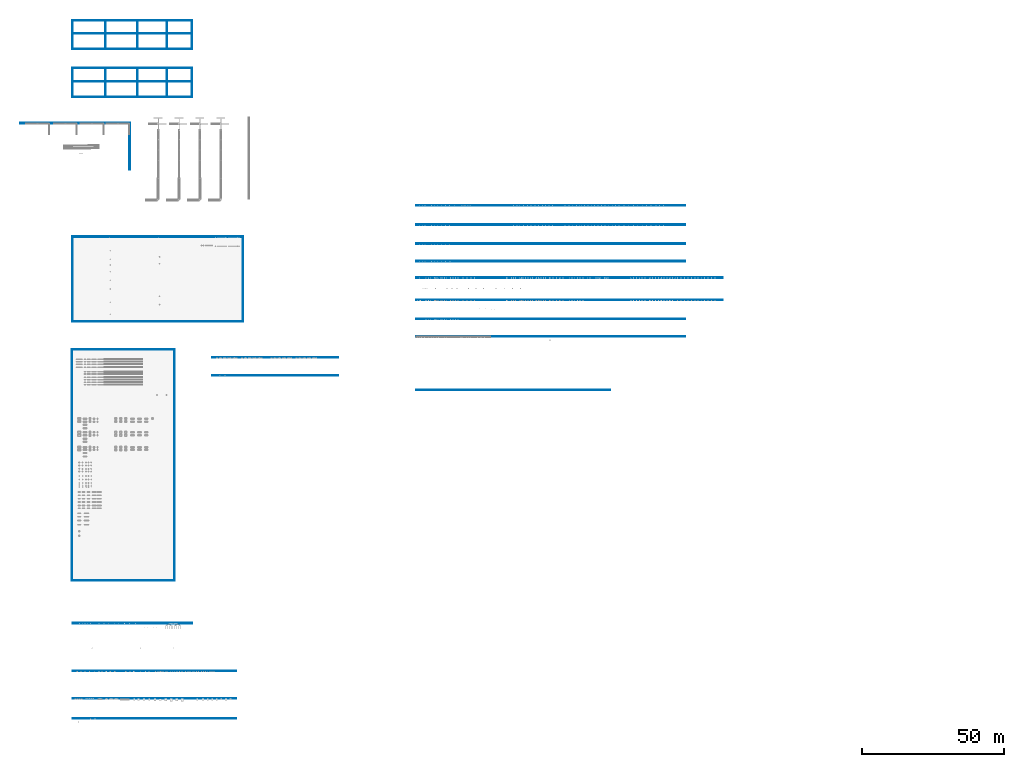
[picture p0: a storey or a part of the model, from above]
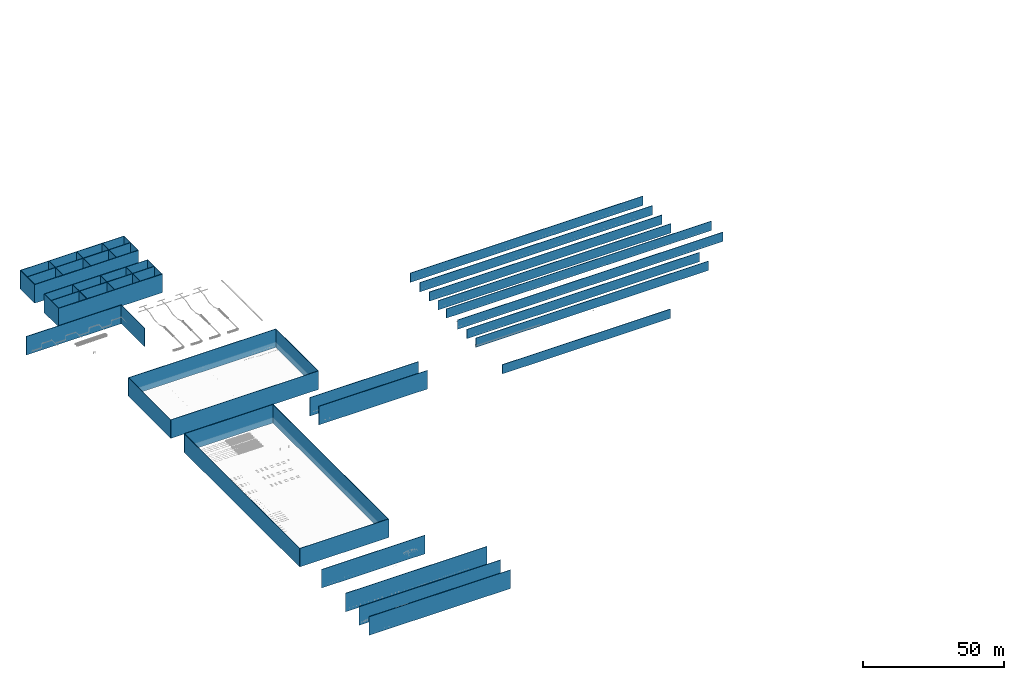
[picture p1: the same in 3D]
Properties of the parts of a building model (IFC2X3), part 1 of 5

# File
Description: ViewDefinition [CoordinationView_V2.0], RevitIdentifiers [ContentGUID: 6402ca86-c77d-4067-b1c1-b8176a6fbf7a, VersionGUID: b93e8563-b8f6-4420-bbab-752b2f349fee, NumberOfSaves: 58], CoordinateReference [CoordinateBase: Coordonnées partagées actuelles]
File name: 735-CAF31-Parvis-ELE.ifc
Time: 2026-01-16T10:17:38+01:00
Written by: ODA SDAI 24.6
Made in: Autodesk Revit 24.3.10.22 (FRA) - IFC 24.3.20.8

# IfcProject, PRO-DCE
LongName: REAMENAGEMENT DU PARVIS DE LA CAF RUE RIQUET A TOULOUSE; Phase: Etat du projet

# IfcSite, Default
RefLatitude: 48, 51, 23, 999633; RefLongitude: 2, 21, 3, 553905; RefElevation: 0 m

# IfcBuilding
Pset_BuildingCommon - NumberOfStoreys: 1

# IfcBuildingStorey: Niveau:Pointe 8 mm (3)
Name | LongName | Elevation (m)
Niveau 0 | Niveau 0 | 0
Niveau 1 | Niveau 1 | 4.58
Niveau 2 | Niveau 2 | 8

# IfcSpace: Espace 1 1:3743090, 1
In: Niveau 0
LongName: Espace 1; InteriorOrExteriorSpace: INTERNAL; Group: Par défaut:293242
Pset_SpaceCommon - Reference: Espace 1 1

# IfcSpace: Espace 2 2:3743092, 2
In: Niveau 0
LongName: Espace 2; InteriorOrExteriorSpace: INTERNAL; Group: Par défaut:293242
Pset_SpaceCommon - Reference: Espace 2 2

# IfcSpace: Espace 21:3744162, 21
In: Niveau 0
LongName: Espace; InteriorOrExteriorSpace: INTERNAL; Group: Par défaut:293242
Pset_SpaceCommon - Reference: Espace 21

# IfcSpace: Espace 22:3744163, 22
In: Niveau 0
LongName: Espace; InteriorOrExteriorSpace: INTERNAL; Group: Par défaut:293242
Pset_SpaceCommon - Reference: Espace 22

# IfcSpace: Espace 23:3744164, 23
In: Niveau 0
LongName: Espace; InteriorOrExteriorSpace: INTERNAL; Group: Par défaut:293242
Pset_SpaceCommon - Reference: Espace 23

# IfcSpace: Espace 24:3744165, 24
In: Niveau 0
LongName: Espace; InteriorOrExteriorSpace: INTERNAL; Group: Par défaut:293242
Pset_SpaceCommon - Reference: Espace 24

# IfcSpace: Espace 25:3744166, 25
In: Niveau 0
LongName: Espace; InteriorOrExteriorSpace: INTERNAL; Group: Par défaut:293242
Pset_SpaceCommon - Reference: Espace 25

# IfcSpace: Espace 26:3744167, 26
In: Niveau 0
LongName: Espace; InteriorOrExteriorSpace: INTERNAL; Group: Par défaut:293242
Pset_SpaceCommon - Reference: Espace 26

# IfcSpace: Espace 27:3744168, 27
In: Niveau 0
LongName: Espace; InteriorOrExteriorSpace: INTERNAL; Group: Par défaut:293242
Pset_SpaceCommon - Reference: Espace 27

# IfcSpace: Espace 28:3744169, 28
In: Niveau 0
LongName: Espace; InteriorOrExteriorSpace: INTERNAL; Group: Par défaut:293242
Pset_SpaceCommon - Reference: Espace 28

# IfcSpace: Espace 3 3:3743094, 3
In: Niveau 0
LongName: Espace 3; InteriorOrExteriorSpace: INTERNAL; Group: Par défaut:293242
Pset_SpaceCommon - Reference: Espace 3 3

# IfcSpace: Espace 4 4:3743096, 4
In: Niveau 0
LongName: Espace 4; InteriorOrExteriorSpace: INTERNAL; Group: Par défaut:293242
Pset_SpaceCommon - Reference: Espace 4 4

# IfcSpace: Espace 5 5:3743098, 5
In: Niveau 0
LongName: Espace 5; InteriorOrExteriorSpace: INTERNAL; Group: Par défaut:293242
Pset_SpaceCommon - Reference: Espace 5 5

# IfcSpace: Espace 6 6:3743100, 6
In: Niveau 0
LongName: Espace 6; InteriorOrExteriorSpace: INTERNAL; Group: Par défaut:293242
Pset_SpaceCommon - Reference: Espace 6 6

# IfcSpace: Espace 7 7:3743102, 7
In: Niveau 0
LongName: Espace 7; InteriorOrExteriorSpace: INTERNAL; Group: Par défaut:293242
Pset_SpaceCommon - Reference: Espace 7 7

# IfcSpace: Espace 8 8:3743104, 8
In: Niveau 0
LongName: Espace 8; InteriorOrExteriorSpace: INTERNAL; Group: Par défaut:293242
Pset_SpaceCommon - Reference: Espace 8 8

# IfcSpace: Pièce 1 21:3744182, 21
In: Niveau 0
LongName: Pièce 1; InteriorOrExteriorSpace: INTERNAL
Pset_SpaceCommon - Reference: Pièce 1 21

# IfcSpace: Pièce 1:3743132, 1
In: Niveau 0
LongName: Pièce; InteriorOrExteriorSpace: INTERNAL
Pset_SpaceCommon - Reference: Pièce 1

# IfcSpace: Pièce 2 22:3744183, 22
In: Niveau 0
LongName: Pièce 2; InteriorOrExteriorSpace: INTERNAL
Pset_SpaceCommon - Reference: Pièce 2 22

# IfcSpace: Pièce 2:3743134, 2
In: Niveau 0
LongName: Pièce; InteriorOrExteriorSpace: INTERNAL
Pset_SpaceCommon - Reference: Pièce 2

# IfcSpace: Pièce 3 23:3744184, 23
In: Niveau 0
LongName: Pièce 3; InteriorOrExteriorSpace: INTERNAL
Pset_SpaceCommon - Reference: Pièce 3 23

# IfcSpace: Pièce 3:3743136, 3
In: Niveau 0
LongName: Pièce; InteriorOrExteriorSpace: INTERNAL
Pset_SpaceCommon - Reference: Pièce 3

# IfcSpace: Pièce 4 24:3744185, 24
In: Niveau 0
LongName: Pièce 4; InteriorOrExteriorSpace: INTERNAL
Pset_SpaceCommon - Reference: Pièce 4 24

# IfcSpace: Pièce 4:3743138, 4
In: Niveau 0
LongName: Pièce; InteriorOrExteriorSpace: INTERNAL
Pset_SpaceCommon - Reference: Pièce 4

# IfcSpace: Pièce 5 25:3744186, 25
In: Niveau 0
LongName: Pièce 5; InteriorOrExteriorSpace: INTERNAL
Pset_SpaceCommon - Reference: Pièce 5 25

# IfcSpace: Pièce 5:3743140, 5
In: Niveau 0
LongName: Pièce; InteriorOrExteriorSpace: INTERNAL
Pset_SpaceCommon - Reference: Pièce 5

# IfcSpace: Pièce 6 26:3744187, 26
In: Niveau 0
LongName: Pièce 6; InteriorOrExteriorSpace: INTERNAL
Pset_SpaceCommon - Reference: Pièce 6 26

# IfcSpace: Pièce 6:3743142, 6
In: Niveau 0
LongName: Pièce; InteriorOrExteriorSpace: INTERNAL
Pset_SpaceCommon - Reference: Pièce 6

# IfcSpace: Pièce 7 27:3744188, 27
In: Niveau 0
LongName: Pièce 7; InteriorOrExteriorSpace: INTERNAL
Pset_SpaceCommon - Reference: Pièce 7 27

# IfcSpace: Pièce 7:3743144, 7
In: Niveau 0
LongName: Pièce; InteriorOrExteriorSpace: INTERNAL
Pset_SpaceCommon - Reference: Pièce 7

# IfcSpace: Pièce 8 28:3744189, 28
In: Niveau 0
LongName: Pièce 8; InteriorOrExteriorSpace: INTERNAL
Pset_SpaceCommon - Reference: Pièce 8 28

# IfcSpace: Pièce 8:3743146, 8
In: Niveau 0
LongName: Pièce; InteriorOrExteriorSpace: INTERNAL
Pset_SpaceCommon - Reference: Pièce 8

# IfcBuildingElementProxy: Armoire 950+500x1600:950+500x1600, Armoire 950+500x1600:950+500x1600:4182300
In: Niveau 0
Type - Material: A-PVC ARMOIRE 3 - POIGNE - RAL 7035, BETCE-BARILLET-RAL 9010, <Unnamed>, BETCE-ENVELOPPE-RAL 7035
Pset_BuildingElementProxyCommon - Reference: 950+500x1600; sets with these values: 2

# IfcBuildingElementProxy: Armoire double 3195x1600x630:3195X1600, Armoire double 3195x1600x630:3195X1600:4185073
In: Niveau 0
Type - Material: <Unnamed>, A-PEINTURE ARMOIRE 4 - POIGNE - RAL 7035, A-ACIER INOXIDABLE - BARILLET - RAL 9010, BETCE-BARILLET-RAL 9010, A-PEINTURE ARMOIRE 4 - ENVELOPPE - RAL 7035
Pset_BuildingElementProxyCommon - Reference: 3195X1600; sets with these values: 2

# IfcBuildingElementProxy: Armoire murale 2x725x1050:2x725x1050, Armoire murale 2x725x1050:2x725x1050:4176260
In: Niveau 0
Type - Material: A- PVC ARMOIRE 2 - POIGNE - RAL 7035, A- PVC ARMOIRE 2 - BARRILLET - RAL 9010, <Unnamed>, A- PVC ARMOIRE 2 - ENVELOPPE - RAL 7035
Pset_BuildingElementProxyCommon - Reference: 2x725x1050; sets with these values: 2

# IfcBuildingElementProxy: Armoire murale 600+350x1100:600+350X1100, Armoire murale 600+350x1100:600+350X1100:4174725
In: Niveau 0
Type - Material: A-PVC ARMOIRE - POIGNE -RAL 7035, A-PVC ARMOIRE - BARILLET -RAL 9010, <Unnamed>, A-PVC ARMOIRE - ENVELOPPE -RAL 7035
Pset_BuildingElementProxyCommon - Reference: 600+350X1100; sets with these values: 2

# IfcBuildingElementProxy: Armoire sur pied 2x600+300x2000:2x600+300x2000, Armoire sur pied 2x600+300x2000:2x600+300x2000:4173222
In: Niveau 0
Type - Material: BETCE-POIGNE-RAL 7035, BETCE-BARILLET-RAL 9010, <Unnamed>, BETCE-ENVELOPPE-RAL 7035
Pset_BuildingElementProxyCommon - Reference: 2x600+300x2000; sets with these values: 2

# IfcBuildingElementProxy: Arrêt d'urgence à voyant:A.U. GENERAL, Arrêt d'urgence à voyant:A.U. GENERAL:4813649
In: Niveau 0
Type - Material: PVC ROUGE, Verre, VOYANT ROUGE, VOYANT VERT
Pset_BuildingElementProxyCommon - Reference: A.U. GENERAL; sets with these values: 2

# IfcBuildingElementProxy: Arrêt d'urgence à voyant:A.U. VENTILLATION, Arrêt d'urgence à voyant:A.U. VENTILLATION:4813641
In: Niveau 0
Type - Material: PVC ROUGE, Verre, VOYANT ROUGE, VOYANT VERT
Pset_BuildingElementProxyCommon - Reference: A.U. VENTILLATION; sets with these values: 2

# IfcBuildingElementProxy: Arrêt d'urgence à voyant:Arrêt d'urgence à voyant, Arrêt d'urgence à voyant:Arrêt d'urgence à voyant:4811939
In: Niveau 0
Type - Material: PVC ROUGE, Verre, VOYANT ROUGE, VOYANT VERT
Pset_BuildingElementProxyCommon - Reference: Arrêt d'urgence à voyant; sets with these values: 2

# IfcBuildingElementProxy: Attente électrique-100e:FM CVC, Attente électrique-100e:FM CVC:4817656
In: Niveau 0
Type - Material: <Unnamed>
Pset_BuildingElementProxyCommon - Reference: FM CVC; sets with these values: 2

# IfcBuildingElementProxy: Attente électrique-100e:FM ELEC, Attente électrique-100e:FM ELEC:4817851
In: Niveau 0
Type - Material: <Unnamed>
Pset_BuildingElementProxyCommon - Reference: FM ELEC; sets with these values: 2

# IfcBuildingElementProxy: Attente électrique-50e:FM CVC (2)
In: Niveau 0
Type - Material: <Unnamed>
Pset_BuildingElementProxyCommon - Reference: FM CVC; sets with these values: 2
Name (Attente électrique-50e:FM CVC:...)
4815699
6239915

# IfcBuildingElementProxy: Attente électrique-50e:FM ELEC (7)
In: Niveau 0
Type - Material: <Unnamed>
Pset_BuildingElementProxyCommon - Reference: FM ELEC; sets with these values: 2
Name (Attente électrique-50e:FM ELEC:...)
4817803
6209736
6234142
6234843
6252051
6252059
6253986

# IfcBuildingElementProxy: Baie de brassage sur pied:24U-L=600_P=600_H=1226, Baie de brassage sur pied:24U-L=600_P=600_H=1226:4192028
In: Niveau 0
Type - Material: A-PVC NOIR, A-VERRE, <Unnamed>
Pset_BuildingElementProxyCommon - Reference: 24U-L=600_P=600_H=1226; sets with these values: 2

# IfcBuildingElementProxy: Baie de brassage sur pied:29U-L=600_P=600_H=1448, Baie de brassage sur pied:29U-L=600_P=600_H=1448:4192674
In: Niveau 0
Type - Material: A-PVC NOIR, A-VERRE, <Unnamed>
Pset_BuildingElementProxyCommon - Reference: 29U-L=600_P=600_H=1448; sets with these values: 2

# IfcBuildingElementProxy: Baie de brassage sur pied:33U-L=600_P=600_H=1626, Baie de brassage sur pied:33U-L=600_P=600_H=1626:4192862
In: Niveau 0
Type - Material: A-PVC NOIR, A-VERRE, <Unnamed>
Pset_BuildingElementProxyCommon - Reference: 33U-L=600_P=600_H=1626; sets with these values: 2

# IfcBuildingElementProxy: Baie de brassage sur pied:42U-L=600_P=600_H=2026, Baie de brassage sur pied:42U-L=600_P=600_H=2026:4192974
In: Niveau 0
Type - Material: A-PVC NOIR, A-VERRE, <Unnamed>
Pset_BuildingElementProxyCommon - Reference: 42U-L=600_P=600_H=2026; sets with these values: 2

# IfcBuildingElementProxy: Baie de brassage sur pied:42U-L=600_P=800_H=2026, Baie de brassage sur pied:42U-L=600_P=800_H=2026:4193102
In: Niveau 0
Type - Material: A-PVC NOIR, A-VERRE, <Unnamed>
Pset_BuildingElementProxyCommon - Reference: 42U-L=600_P=800_H=2026; sets with these values: 2

# IfcBuildingElementProxy: Baie de brassage sur pied:42U-L=800_P=1000_H=2026, Baie de brassage sur pied:42U-L=800_P=1000_H=2026:4193520
In: Niveau 0
Type - Material: A-PVC NOIR, A-VERRE, <Unnamed>
Pset_BuildingElementProxyCommon - Reference: 42U-L=800_P=1000_H=2026; sets with these values: 2

# IfcBuildingElementProxy: Baie de brassage sur pied:42U-L=800_P=600_H=2026, Baie de brassage sur pied:42U-L=800_P=600_H=2026:4193318
In: Niveau 0
Type - Material: A-PVC NOIR, A-VERRE, <Unnamed>
Pset_BuildingElementProxyCommon - Reference: 42U-L=800_P=600_H=2026; sets with these values: 2

# IfcBuildingElementProxy: Baie de brassage sur pied:42U-L=800_P=800_H=2026, Baie de brassage sur pied:42U-L=800_P=800_H=2026:4193430
In: Niveau 0
Type - Material: A-PVC NOIR, A-VERRE, <Unnamed>
Pset_BuildingElementProxyCommon - Reference: 42U-L=800_P=800_H=2026; sets with these values: 2

# IfcBuildingElementProxy: Baie de brassage sur pied:47U-L=800_P=1000_H=2248, Baie de brassage sur pied:47U-L=800_P=1000_H=2248:4193710
In: Niveau 0
Type - Material: A-PVC NOIR, A-VERRE, <Unnamed>
Pset_BuildingElementProxyCommon - Reference: 47U-L=800_P=1000_H=2248; sets with these values: 2

# IfcBuildingElementProxy: Baie de brassage sur pied:47U-L=800_P=800_H=2248, Baie de brassage sur pied:47U-L=800_P=800_H=2248:4193630
In: Niveau 0
Type - Material: A-PVC NOIR, A-VERRE, <Unnamed>
Pset_BuildingElementProxyCommon - Reference: 47U-L=800_P=800_H=2248; sets with these values: 2

# IfcBuildingElementProxy: Boitier sol 2x3 modules:2PCN+2RJ+1HDMI+1USB, Boitier sol 2x3 modules:2PCN+2RJ+1HDMI+1USB:5134745
In: Niveau 0
Type - Material: <Unnamed>, Legrand - Inox
Type - Pset_ManufacturerTypeInformation - Manufacturer: LEGRAND
Pset_BuildingElementProxyCommon - Reference: 2PCN+2RJ+1HDMI+1USB; sets with these values: 2

# IfcBuildingElementProxy: Boitier sol 3x3 modules:2PCN+2PCO+2RJ+1HDMI+1USB, Boitier sol 3x3 modules:2PCN+2PCO+2RJ+1HDMI+1USB:5141581
In: Niveau 0
Type - Material: <Unnamed>, Legrand - Inox
Type - Pset_ManufacturerTypeInformation - Manufacturer: LEGRAND
Pset_BuildingElementProxyCommon - Reference: 2PCN+2PCO+2RJ+1HDMI+1USB; sets with these values: 2

# IfcBuildingElementProxy: Boitier sol 3x3 modules:2PCN+2PCO+2RJ+2HDMI, Boitier sol 3x3 modules:2PCN+2PCO+2RJ+2HDMI:5141752
In: Niveau 0
Type - Material: <Unnamed>, Legrand - Inox
Type - Pset_ManufacturerTypeInformation - Manufacturer: LEGRAND
Pset_BuildingElementProxyCommon - Reference: 2PCN+2PCO+2RJ+2HDMI; sets with these values: 2

# IfcBuildingElementProxy: Boitier sol 3x3 modules:2PCN+2PCO+2RJ+2USB, Boitier sol 3x3 modules:2PCN+2PCO+2RJ+2USB:5141893
In: Niveau 0
Type - Material: <Unnamed>, Legrand - Inox
Type - Pset_ManufacturerTypeInformation - Manufacturer: LEGRAND
Pset_BuildingElementProxyCommon - Reference: 2PCN+2PCO+2RJ+2USB; sets with these values: 2

# IfcBuildingElementProxy: Boitier sol 3x4 modules:3PCN+3PCO+3RJ+1HDMI+1USB, Boitier sol 3x4 modules:3PCN+3PCO+3RJ+1HDMI+1USB:5148815
In: Niveau 0
Type - Material: <Unnamed>, Legrand - Inox
Type - Pset_ManufacturerTypeInformation - Manufacturer: LEGRAND
Pset_BuildingElementProxyCommon - Reference: 3PCN+3PCO+3RJ+1HDMI+1USB; sets with these values: 2

# IfcBuildingElementProxy: Boitier sol 3x4 modules:3PCN+3PCO+3RJ+2HDMI, Boitier sol 3x4 modules:3PCN+3PCO+3RJ+2HDMI:5148930
In: Niveau 0
Type - Material: <Unnamed>, Legrand - Inox
Type - Pset_ManufacturerTypeInformation - Manufacturer: LEGRAND
Pset_BuildingElementProxyCommon - Reference: 3PCN+3PCO+3RJ+2HDMI; sets with these values: 2

# IfcBuildingElementProxy: Boitier sol 3x4 modules:3PCN+3PCO+3RJ+2USB, Boitier sol 3x4 modules:3PCN+3PCO+3RJ+2USB:5149087
In: Niveau 0
Type - Material: <Unnamed>, Legrand - Inox
Type - Pset_ManufacturerTypeInformation - Manufacturer: LEGRAND
Pset_BuildingElementProxyCommon - Reference: 3PCN+3PCO+3RJ+2USB; sets with these values: 2

# IfcBuildingElementProxy: Boitier sol 4x4 modules:4PCN+4PCO+4RJ+1HDMI+1USB, Boitier sol 4x4 modules:4PCN+4PCO+4RJ+1HDMI+1USB:5157137
In: Niveau 0
Type - Material: <Unnamed>, Legrand - Inox
Type - Pset_ManufacturerTypeInformation - Manufacturer: LEGRAND
Pset_BuildingElementProxyCommon - Reference: 4PCN+4PCO+4RJ+1HDMI+1USB; sets with these values: 2

# IfcBuildingElementProxy: Boitier sol 4x4 modules:4PCN+4PCO+4RJ+2HDMI, Boitier sol 4x4 modules:4PCN+4PCO+4RJ+2HDMI:5157296
In: Niveau 0
Type - Material: <Unnamed>, Legrand - Inox
Type - Pset_ManufacturerTypeInformation - Manufacturer: LEGRAND
Pset_BuildingElementProxyCommon - Reference: 4PCN+4PCO+4RJ+2HDMI; sets with these values: 2

# IfcBuildingElementProxy: Boitier sol 4x4 modules:4PCN+4PCO+4RJ+2HDMI+2USB, Boitier sol 4x4 modules:4PCN+4PCO+4RJ+2HDMI+2USB:5157393
In: Niveau 0
Type - Material: <Unnamed>, Legrand - Inox
Type - Pset_ManufacturerTypeInformation - Manufacturer: LEGRAND
Pset_BuildingElementProxyCommon - Reference: 4PCN+4PCO+4RJ+2HDMI+2USB; sets with these values: 2

# IfcBuildingElementProxy: Boitier sol 4x4 modules:4PCN+4PCO+4RJ+2USB, Boitier sol 4x4 modules:4PCN+4PCO+4RJ+2USB:5157482
In: Niveau 0
Type - Material: <Unnamed>, Legrand - Inox
Type - Pset_ManufacturerTypeInformation - Manufacturer: LEGRAND
Pset_BuildingElementProxyCommon - Reference: 4PCN+4PCO+4RJ+2USB; sets with these values: 2

# IfcBuildingElementProxy: Bouton poussoir domotique encastré:BLEU, Bouton poussoir domotique encastré:BLEU:5246806
In: Niveau 0
Type - Material: BETCE-CADRE MARRON 152-112-16, <Unnamed>
Pset_BuildingElementProxyCommon - Reference: BLEU; sets with these values: 2

# IfcBuildingElementProxy: Bouton poussoir domotique encastré:MAGENTA, Bouton poussoir domotique encastré:MAGENTA:5247162
In: Niveau 0
Type - Material: BETCE-CADRE MARRON 152-112-16, <Unnamed>
Pset_BuildingElementProxyCommon - Reference: MAGENTA; sets with these values: 2

# IfcBuildingElementProxy: Bouton poussoir domotique encastré:MARRON, Bouton poussoir domotique encastré:MARRON:5247234
In: Niveau 0
Type - Material: BETCE-CADRE MARRON 152-112-16, <Unnamed>
Pset_BuildingElementProxyCommon - Reference: MARRON; sets with these values: 2

# IfcBuildingElementProxy: Bouton poussoir domotique encastré:NOIR, Bouton poussoir domotique encastré:NOIR:5247298
In: Niveau 0
Type - Material: BETCE-CADRE MARRON 152-112-16, <Unnamed>
Pset_BuildingElementProxyCommon - Reference: NOIR; sets with these values: 2

# IfcBuildingElementProxy: Bouton poussoir domotique encastré:ORANGE, Bouton poussoir domotique encastré:ORANGE:5247380
In: Niveau 0
Type - Material: BETCE-CADRE MARRON 152-112-16, <Unnamed>
Pset_BuildingElementProxyCommon - Reference: ORANGE; sets with these values: 2

# IfcBuildingElementProxy: Bouton poussoir domotique encastré:ROUGE, Bouton poussoir domotique encastré:ROUGE:5247480
In: Niveau 0
Type - Material: BETCE-CADRE MARRON 152-112-16, <Unnamed>
Pset_BuildingElementProxyCommon - Reference: ROUGE; sets with these values: 2

# IfcBuildingElementProxy: Bouton poussoir domotique encastré:VERT, Bouton poussoir domotique encastré:VERT:5247558
In: Niveau 0
Type - Material: BETCE-CADRE MARRON 152-112-16, <Unnamed>
Pset_BuildingElementProxyCommon - Reference: VERT; sets with these values: 2

# IfcBuildingElementProxy: Bouton poussoir encastré controle acces:BP sortie, Bouton poussoir encastré controle acces:BP sortie:4091872
In: Niveau 0
Type - Material: BETCE-DOIGT-BLANC, BETCE-ENJOLIVEUR-BLANC, <Unnamed>
Pset_BuildingElementProxyCommon - Reference: BP sortie; sets with these values: 2

# IfcBuildingElementProxy: Bouton poussoir saillie controle acces:BP sortie, Bouton poussoir saillie controle acces:BP sortie:6006362
In: Niveau 0
Type - Material: BETCE-CADRE-BLANC, BETCE-DOIGT-BLANC, BETCE-ENJOLIVEUR-BLANC
Pset_BuildingElementProxyCommon - Reference: BP sortie; sets with these values: 2

# IfcBuildingElementProxy: Centrale:Centrale control d'accés, Centrale:Centrale control d'accés:4087308
In: Niveau 0
Type - Material: <Unnamed>
Pset_BuildingElementProxyCommon - Reference: Centrale control d'accés; sets with these values: 2

# IfcBuildingElementProxy: Centrale:Centrale intrusion, Centrale:Centrale intrusion:4087595
In: Niveau 0
Type - Material: <Unnamed>
Pset_BuildingElementProxyCommon - Reference: Centrale intrusion; sets with these values: 2

# IfcBuildingElementProxy: Clavier:Clavier intrusion, Clavier:Clavier intrusion:4090489
In: Niveau 0
Type - Material: <Unnamed>
Type - Pset_ElementShading - Color: Black RAL9005
Type - Pset_ManufacturerTypeInformation - Manufacturer: Urmet S.p.A.Urmet S.p.A.
Classification: 80KP5300113 (Uniformat)
Pset_BuildingElementProxyCommon - Reference: Clavier intrusion; sets with these values: 2

# IfcBuildingElementProxy: Coffret UTL:UTL contrôle accés - alim non secourue-8E/4S, Coffret UTL:UTL contrôle accés - alim non secourue-8E/4S:4084620
In: Niveau 0
Type - Material: <Unnamed>
Pset_BuildingElementProxyCommon - Reference: UTL contrôle accés - alim non secourue-8E/4S; sets with these values: 2

# IfcBuildingElementProxy: Coffret UTL:UTL contrôle accés - alim secourue-8E/4S, Coffret UTL:UTL contrôle accés - alim secourue-8E/4S:4085028
In: Niveau 0
Type - Material: <Unnamed>
Pset_BuildingElementProxyCommon - Reference: UTL contrôle accés - alim secourue-8E/4S; sets with these values: 2

# IfcBuildingElementProxy: Coffret UTL:UTL intrusion - alim non secourue-8E/4S, Coffret UTL:UTL intrusion - alim non secourue-8E/4S:4085036
In: Niveau 0
Type - Material: <Unnamed>
Pset_BuildingElementProxyCommon - Reference: UTL intrusion - alim non secourue-8E/4S; sets with these values: 2

# IfcBuildingElementProxy: Coffret UTL:UTL intrusion - alim secourue-8E/4S, Coffret UTL:UTL intrusion - alim secourue-8E/4S:4085044
In: Niveau 0
Type - Material: <Unnamed>
Pset_BuildingElementProxyCommon - Reference: UTL intrusion - alim secourue-8E/4S; sets with these values: 2

# IfcBuildingElementProxy: Coffret de brassage mural:12U-600x600x635, Coffret de brassage mural:12U-600x600x635:4200865
In: Niveau 0
Type - Material: A-PVC NOIR, A-VERRE
Pset_BuildingElementProxyCommon - Reference: 12U-600x600x635; sets with these values: 2

# IfcBuildingElementProxy: Coffret de brassage mural:15U-600x600x770, Coffret de brassage mural:15U-600x600x770:4200817
In: Niveau 0
Type - Material: A-PVC NOIR, A-VERRE
Pset_BuildingElementProxyCommon - Reference: 15U-600x600x770; sets with these values: 2

# IfcBuildingElementProxy: Coffret de brassage mural:18U-600x600x900, Coffret de brassage mural:18U-600x600x900:4200691
In: Niveau 0
Type - Material: A-PVC NOIR, A-VERRE
Pset_BuildingElementProxyCommon - Reference: 18U-600x600x900; sets with these values: 2

# IfcBuildingElementProxy: Coffret de brassage mural:22U-600x600x1200, Coffret de brassage mural:22U-600x600x1200:4198581
In: Niveau 0
Type - Material: A-PVC NOIR, A-VERRE
Pset_BuildingElementProxyCommon - Reference: 22U-600x600x1200; sets with these values: 2

# IfcBuildingElementProxy: Coffret de brassage mural:6U-600x450x368, Coffret de brassage mural:6U-600x450x368:4201155
In: Niveau 0
Type - Material: A-PVC NOIR, A-VERRE
Pset_BuildingElementProxyCommon - Reference: 6U-600x450x368; sets with these values: 2

# IfcBuildingElementProxy: Coffret de brassage mural:6U-600x600x368, Coffret de brassage mural:6U-600x600x368:4201077
In: Niveau 0
Type - Material: A-PVC NOIR, A-VERRE
Pset_BuildingElementProxyCommon - Reference: 6U-600x600x368; sets with these values: 2

# IfcBuildingElementProxy: Coffret de brassage mural:9U-600x450x500, Coffret de brassage mural:9U-600x450x500:4201009
In: Niveau 0
Type - Material: A-PVC NOIR, A-VERRE
Pset_BuildingElementProxyCommon - Reference: 9U-600x450x500; sets with these values: 2

# IfcBuildingElementProxy: Coffret de brassage mural:9U-600x600x500, Coffret de brassage mural:9U-600x600x500:4200919
In: Niveau 0
Type - Material: A-PVC NOIR, A-VERRE
Pset_BuildingElementProxyCommon - Reference: 9U-600x600x500; sets with these values: 2

# IfcBuildingElementProxy: Coffret mural 18 modules avec porte:18M-1R, Coffret mural 18 modules avec porte:18M-1R:4139435
In: Niveau 0
Type - Material: BETCE-ANNEAU-CHROME, BETCE-TABLEAU-BLANC
Pset_BuildingElementProxyCommon - Reference: 18M-1R; sets with these values: 2

# IfcBuildingElementProxy: Coffret mural 18 modules avec porte:36M-2R, Coffret mural 18 modules avec porte:36M-2R:4154643
In: Niveau 0
Type - Material: BETCE-ANNEAU-CHROME, BETCE-TABLEAU-BLANC
Pset_BuildingElementProxyCommon - Reference: 36M-2R; sets with these values: 2

# IfcBuildingElementProxy: Coffret mural 18 modules avec porte:54M-3R, Coffret mural 18 modules avec porte:54M-3R:4154651
In: Niveau 0
Type - Material: BETCE-ANNEAU-CHROME, BETCE-TABLEAU-BLANC
Pset_BuildingElementProxyCommon - Reference: 54M-3R; sets with these values: 2

# IfcBuildingElementProxy: Coffret mural 18 modules avec porte:72M-4R, Coffret mural 18 modules avec porte:72M-4R:4154659
In: Niveau 0
Type - Material: BETCE-ANNEAU-CHROME, BETCE-TABLEAU-BLANC
Pset_BuildingElementProxyCommon - Reference: 72M-4R; sets with these values: 2

# IfcBuildingElementProxy: Coffret mural 18 modules:18M-1R, Coffret mural 18 modules:18M-1R:4156919
In: Niveau 0
Type - Material: BETCE-TABLEAU-BLANC
Pset_BuildingElementProxyCommon - Reference: 18M-1R; sets with these values: 2

# IfcBuildingElementProxy: Coffret mural 18 modules:36M-2R, Coffret mural 18 modules:36M-2R:4157181
In: Niveau 0
Type - Material: BETCE-TABLEAU-BLANC
Pset_BuildingElementProxyCommon - Reference: 36M-2R; sets with these values: 2

# IfcBuildingElementProxy: Coffret mural 18 modules:54M-3R, Coffret mural 18 modules:54M-3R:4157189
In: Niveau 0
Type - Material: BETCE-TABLEAU-BLANC
Pset_BuildingElementProxyCommon - Reference: 54M-3R; sets with these values: 2

# IfcBuildingElementProxy: Coffret mural 18 modules:72M-4R (2)
In: Niveau 0
Type - Material: BETCE-TABLEAU-BLANC
Pset_BuildingElementProxyCommon - Reference: 72M-4R; sets with these values: 2
Name (Coffret mural 18 modules:72M-4R:...)
4157197
6049605

# IfcBuildingElementProxy: Contact porte:Contact de porte, Contact porte:Contact de porte:4078686
In: Niveau 0
Type - Material: BETCE-CONTACT DE PORTE-BLANC
Pset_BuildingElementProxyCommon - Reference: Contact de porte; sets with these values: 2

# IfcBuildingElementProxy: Déclencheur manuel saillie controle acces:DM VERT, Déclencheur manuel saillie controle acces:DM VERT:4097846
In: Niveau 0
Type - Material: BETCE-DOIGT BLANC, BETCE-DM VERT
Pset_BuildingElementProxyCommon - Reference: DM VERT; sets with these values: 2

# IfcBuildingElementProxy: Détecteur intrusion:Détecteur, Détecteur intrusion:Détecteur:4077187
In: Niveau 0
Type - Material: BETCE-DETECTEUR INTRUSION-CELLULE-NOIR, BETCE-DETECTEUR INTRUSION-ENVELOPPE-BLANC
Pset_BuildingElementProxyCommon - Reference: Détecteur; sets with these values: 2

# IfcBuildingElementProxy: Détecteur mural 280° saillie:MURAL, Détecteur mural 280° saillie:MURAL:3557888
In: Niveau 0
Type - Material: Blanc froid, Verre
Type - Pset_ManufacturerTypeInformation - Manufacturer: B.E.G
Classification: D5010200 Low Tension Service & Distribution (Uniformat)
Pset_BuildingElementProxyCommon - Reference: MURAL; sets with these values: 2

# IfcBuildingElementProxy: Détecteur mural 280° saillie:MURAL DALI, Détecteur mural 280° saillie:MURAL DALI:3558010
In: Niveau 0
Type - Material: Blanc froid, Verre
Type - Pset_ManufacturerTypeInformation - Manufacturer: B.E.G
Classification: D5010200 Low Tension Service & Distribution (Uniformat)
Pset_BuildingElementProxyCommon - Reference: MURAL DALI; sets with these values: 2

# IfcBuildingElementProxy: Détecteur plafond 360° encastré:COULOIR, Détecteur plafond 360° encastré:COULOIR:3506113
In: Niveau 0
Type - Material: Blanc, Verre optique
Type - Pset_ManufacturerTypeInformation - Manufacturer: Legrand
Pset_BuildingElementProxyCommon - Reference: COULOIR; sets with these values: 2

# IfcBuildingElementProxy: Détecteur plafond 360° encastré:COULOIR-DALI, Détecteur plafond 360° encastré:COULOIR-DALI:3506451
In: Niveau 0
Type - Material: Blanc, Verre optique
Type - Pset_ManufacturerTypeInformation - Manufacturer: Legrand
Pset_BuildingElementProxyCommon - Reference: COULOIR-DALI; sets with these values: 2

# IfcBuildingElementProxy: Détecteur plafond 360° encastré:SALLE, Détecteur plafond 360° encastré:SALLE:3506462
In: Niveau 0
Type - Material: Blanc, Verre optique
Type - Pset_ManufacturerTypeInformation - Manufacturer: Legrand
Pset_BuildingElementProxyCommon - Reference: SALLE; sets with these values: 2

# IfcBuildingElementProxy: Détecteur plafond 360° encastré:SALLE-DALI, Détecteur plafond 360° encastré:SALLE-DALI:3506600
In: Niveau 0
Type - Material: Blanc, Verre optique
Type - Pset_ManufacturerTypeInformation - Manufacturer: Legrand
Pset_BuildingElementProxyCommon - Reference: SALLE-DALI; sets with these values: 2

# IfcBuildingElementProxy: Détecteur plafond 360° présence encastré:PRESENCE, Détecteur plafond 360° présence encastré:PRESENCE:3545483
In: Niveau 0
Type - Material: Gris, Verre, Blanc froid
Type - Pset_ManufacturerTypeInformation - Manufacturer: B.E.G.
Classification: D5010200 Low Tension Service & Distribution (Uniformat)
Pset_BuildingElementProxyCommon - Reference: PRESENCE; sets with these values: 2

# IfcBuildingElementProxy: Détecteur plafond 360° présence encastré:PRESENCE DALI, Détecteur plafond 360° présence encastré:PRESENCE DALI:3545034
In: Niveau 0
Type - Material: Gris, Verre, Blanc froid
Type - Pset_ManufacturerTypeInformation - Manufacturer: B.E.G.
Classification: D5010200 Low Tension Service & Distribution (Uniformat)
Pset_BuildingElementProxyCommon - Reference: PRESENCE DALI; sets with these values: 2

# IfcBuildingElementProxy: Détecteur plafond 360° présence saillie:PRESENCE, Détecteur plafond 360° présence saillie:PRESENCE:3553720
In: Niveau 0
Type - Material: Verre, Blanc froid
Type - Pset_ManufacturerTypeInformation - Manufacturer: B.E.G.
Classification: D5010200 Low Tension Service & Distribution (Uniformat)
Pset_BuildingElementProxyCommon - Reference: PRESENCE; sets with these values: 2

# IfcBuildingElementProxy: Détecteur plafond 360° présence saillie:PRESENCE DALI, Détecteur plafond 360° présence saillie:PRESENCE DALI:3554039
In: Niveau 0
Type - Material: Verre, Blanc froid
Type - Pset_ManufacturerTypeInformation - Manufacturer: B.E.G.
Classification: D5010200 Low Tension Service & Distribution (Uniformat)
Pset_BuildingElementProxyCommon - Reference: PRESENCE DALI; sets with these values: 2

# IfcBuildingElementProxy: Détecteur plafond 360° saillie:COULOIR, Détecteur plafond 360° saillie:COULOIR:3530025
In: Niveau 0
Type - Material: Verre, Blanc froid
Type - Pset_ManufacturerTypeInformation - Manufacturer: B.E.G.
Classification: D5010200 Low Tension Service & Distribution (Uniformat)
Pset_BuildingElementProxyCommon - Reference: COULOIR; sets with these values: 2

# IfcBuildingElementProxy: Détecteur plafond 360° saillie:COULOIR DALI, Détecteur plafond 360° saillie:COULOIR DALI:3530017
In: Niveau 0
Type - Material: Verre, Blanc froid
Type - Pset_ManufacturerTypeInformation - Manufacturer: B.E.G.
Classification: D5010200 Low Tension Service & Distribution (Uniformat)
Pset_BuildingElementProxyCommon - Reference: COULOIR DALI; sets with these values: 2

# IfcBuildingElementProxy: Détecteur plafond 360° saillie:SALLE, Détecteur plafond 360° saillie:SALLE:3530009
In: Niveau 0
Type - Material: Verre, Blanc froid
Type - Pset_ManufacturerTypeInformation - Manufacturer: B.E.G.
Classification: D5010200 Low Tension Service & Distribution (Uniformat)
Pset_BuildingElementProxyCommon - Reference: SALLE; sets with these values: 2

# IfcBuildingElementProxy: Détecteur plafond 360° saillie:SALLE DALI, Détecteur plafond 360° saillie:SALLE DALI:3529603
In: Niveau 0
Type - Material: Verre, Blanc froid
Type - Pset_ManufacturerTypeInformation - Manufacturer: B.E.G.
Classification: D5010200 Low Tension Service & Distribution (Uniformat)
Pset_BuildingElementProxyCommon - Reference: SALLE DALI; sets with these values: 2

# IfcBuildingElementProxy: Eclairage de sécurité encastré plafond:AMBIANCE, Eclairage de sécurité encastré plafond:AMBIANCE:3963456
In: Niveau 0
Type - Material: BETCE-ENVELOPPE-BLANC, BETCE-ETIQUETTE-VERT 0-193-0, BETCE-VITRE BAES-BLEU, BETCE-ETIQUETTE-BLANC
Pset_BuildingElementProxyCommon - Reference: AMBIANCE; sets with these values: 2

# IfcBuildingElementProxy: Eclairage de sécurité encastré plafond:BAS, Eclairage de sécurité encastré plafond:BAS:3963581
In: Niveau 0
Type - Material: BETCE-VITRE BAES-BLEU, BETCE-ETIQUETTE-BLANC, BETCE-ENVELOPPE-BLANC, BETCE-ETIQUETTE-VERT 0-193-0
Pset_BuildingElementProxyCommon - Reference: BAS; sets with these values: 2

# IfcBuildingElementProxy: Eclairage de sécurité encastré plafond:DROITE, Eclairage de sécurité encastré plafond:DROITE:3963708
In: Niveau 0
Type - Material: BETCE-ENVELOPPE-BLANC, BETCE-ETIQUETTE-VERT 0-193-0, BETCE-VITRE BAES-BLEU, BETCE-ETIQUETTE-BLANC
Pset_BuildingElementProxyCommon - Reference: DROITE; sets with these values: 2

# IfcBuildingElementProxy: Eclairage de sécurité encastré plafond:GAUCHE, Eclairage de sécurité encastré plafond:GAUCHE:3963800
In: Niveau 0
Type - Material: BETCE-ETIQUETTE-VERT 0-193-0, BETCE-ENVELOPPE-BLANC, BETCE-VITRE BAES-BLEU, BETCE-ETIQUETTE-BLANC
Pset_BuildingElementProxyCommon - Reference: GAUCHE; sets with these values: 2

# IfcBuildingElementProxy: Eclairage de sécurité encastré plafond:GAUCHE/DROITE, Eclairage de sécurité encastré plafond:GAUCHE/DROITE:3963856
In: Niveau 0
Type - Material: BETCE-ENVELOPPE-BLANC, BETCE-ETIQUETTE-VERT 0-193-0, BETCE-VITRE BAES-BLEU, BETCE-ETIQUETTE-BLANC
Pset_BuildingElementProxyCommon - Reference: GAUCHE/DROITE; sets with these values: 2

# IfcBuildingElementProxy: Eclairage de sécurité encastré plafond:SORTIE, Eclairage de sécurité encastré plafond:SORTIE:5908347
In: Niveau 0
Type - Material: BETCE-ETIQUETTE-VERT 0-193-0, BETCE-ETIQUETTE-BLANC, BETCE-VITRE BAES-BLEU
Pset_BuildingElementProxyCommon - Reference: SORTIE; sets with these values: 2

# IfcBuildingElementProxy: Eclairage de sécurité saillie mur:AMBIANCE, Eclairage de sécurité saillie mur:AMBIANCE:3964783
In: Niveau 0
Type - Material: BETCE-ETIQUETTE-BLANC, BETCE-ETIQUETTE-VERT 0-193-0, BETCE-VITRE BAES-BLEU, BETCE-ENVELOPPE BAES-BLANC
Pset_BuildingElementProxyCommon - Reference: AMBIANCE; sets with these values: 2

# IfcBuildingElementProxy: Eclairage de sécurité saillie mur:BAS, Eclairage de sécurité saillie mur:BAS:3964784
In: Niveau 0
Type - Material: BETCE-ENVELOPPE BAES-BLANC, BETCE-ETIQUETTE-VERT 0-193-0, BETCE-VITRE BAES-BLEU
Pset_BuildingElementProxyCommon - Reference: BAS; sets with these values: 2

# IfcBuildingElementProxy: Eclairage de sécurité saillie mur:DROITE, Eclairage de sécurité saillie mur:DROITE:3964785
In: Niveau 0
Type - Material: BETCE-ENVELOPPE BAES-BLANC, BETCE-ETIQUETTE-VERT 0-193-0, BETCE-VITRE BAES-BLEU
Pset_BuildingElementProxyCommon - Reference: DROITE; sets with these values: 2

# IfcBuildingElementProxy: Eclairage de sécurité saillie mur:GAUCHE, Eclairage de sécurité saillie mur:GAUCHE:3964786
In: Niveau 0
Type - Material: BETCE-ENVELOPPE BAES-BLANC, BETCE-ETIQUETTE-VERT 0-193-0, BETCE-VITRE BAES-BLEU
Pset_BuildingElementProxyCommon - Reference: GAUCHE; sets with these values: 2

# IfcBuildingElementProxy: Eclairage de sécurité saillie mur:GAUCHE/DROITE, Eclairage de sécurité saillie mur:GAUCHE/DROITE:3964787
In: Niveau 0
Type - Material: BETCE-ENVELOPPE BAES-BLANC, BETCE-ETIQUETTE-VERT 0-193-0, BETCE-VITRE BAES-BLEU
Pset_BuildingElementProxyCommon - Reference: GAUCHE/DROITE; sets with these values: 2

# IfcBuildingElementProxy: Eclairage de sécurité saillie mur:SORTIE, Eclairage de sécurité saillie mur:SORTIE:5859476
In: Niveau 0
Type - Material: BETCE-ETIQUETTE-BLANC, BETCE-ETIQUETTE-VERT 0-193-0, BETCE-VITRE BAES-BLEU, BETCE-ENVELOPPE BAES-BLANC
Pset_BuildingElementProxyCommon - Reference: SORTIE; sets with these values: 2

# IfcBuildingElementProxy: Eclairage de sécurité saillie plafond:AMBIANCE, Eclairage de sécurité saillie plafond:AMBIANCE:3982495
In: Niveau 0
Type - Material: BETCE-ETIQUETTE-BLANC, BETCE-ETIQUETTE-VERT 0-193-0, BETCE-VITRE BAES-BLEU, BETCE-ENVELOPPE-BLANC
Pset_BuildingElementProxyCommon - Reference: AMBIANCE; sets with these values: 2

# IfcBuildingElementProxy: Eclairage de sécurité saillie plafond:BAS, Eclairage de sécurité saillie plafond:BAS:3982553
In: Niveau 0
Type - Material: BETCE-ENVELOPPE-BLANC, BETCE-ETIQUETTE-VERT 0-193-0, BETCE-VITRE BAES-BLEU
Pset_BuildingElementProxyCommon - Reference: BAS; sets with these values: 2

# IfcBuildingElementProxy: Eclairage de sécurité saillie plafond:DROITE, Eclairage de sécurité saillie plafond:DROITE:3982633
In: Niveau 0
Type - Material: BETCE-ENVELOPPE-BLANC, BETCE-ETIQUETTE-VERT 0-193-0, BETCE-VITRE BAES-BLEU
Pset_BuildingElementProxyCommon - Reference: DROITE; sets with these values: 2

# IfcBuildingElementProxy: Eclairage de sécurité saillie plafond:GAUCHE, Eclairage de sécurité saillie plafond:GAUCHE:3982785
In: Niveau 0
Type - Material: BETCE-ENVELOPPE-BLANC, BETCE-ETIQUETTE-VERT 0-193-0, BETCE-VITRE BAES-BLEU
Pset_BuildingElementProxyCommon - Reference: GAUCHE; sets with these values: 2

# IfcBuildingElementProxy: Eclairage de sécurité saillie plafond:GAUCHE/DROITE, Eclairage de sécurité saillie plafond:GAUCHE/DROITE:3982839
In: Niveau 0
Type - Material: BETCE-ETIQUETTE-BLANC, BETCE-ETIQUETTE-VERT 0-193-0, BETCE-VITRE BAES-BLEU, BETCE-ENVELOPPE-BLANC
Pset_BuildingElementProxyCommon - Reference: GAUCHE/DROITE; sets with these values: 2

# IfcBuildingElementProxy: Eclairage de sécurité saillie plafond:SORTIE, Eclairage de sécurité saillie plafond:SORTIE:5873606
In: Niveau 0
Type - Material: BETCE-ETIQUETTE-VERT 0-193-0, BETCE-ENVELOPPE-BLANC, BETCE-VITRE BAES-BLEU
Pset_BuildingElementProxyCommon - Reference: SORTIE; sets with these values: 2

# IfcBuildingElementProxy: Eclairage de sécurité saillie étanche mur:AMBIANCE, Eclairage de sécurité saillie étanche mur:AMBIANCE:3964788
In: Niveau 0
Type - Material: BETCE-ETIQUETTE-BLANC, BETCE-ETIQUETTE-VERT 0-193-0, BETCE-VITRE BAES-BLEU, BETCE-ENVELOPPE BAES-BLANC
Pset_BuildingElementProxyCommon - Reference: AMBIANCE; sets with these values: 2

# IfcBuildingElementProxy: Eclairage de sécurité saillie étanche mur:BAS, Eclairage de sécurité saillie étanche mur:BAS:3964789
In: Niveau 0
Type - Material: BETCE-ENVELOPPE BAES-BLANC, BETCE-ETIQUETTE-VERT 0-193-0, BETCE-VITRE BAES-BLEU
Pset_BuildingElementProxyCommon - Reference: BAS; sets with these values: 2

# IfcBuildingElementProxy: Eclairage de sécurité saillie étanche mur:DROITE (2)
In: Niveau 0
Type - Material: BETCE-ENVELOPPE BAES-BLANC, BETCE-ETIQUETTE-VERT 0-193-0, BETCE-VITRE BAES-BLEU
Pset_BuildingElementProxyCommon - Reference: DROITE; sets with these values: 2
Name (Eclairage de sécurité saillie étanche mur:DROITE:...)
3964790
6178227

# IfcBuildingElementProxy: Eclairage de sécurité saillie étanche mur:GAUCHE (2)
In: Niveau 0
Type - Material: BETCE-ENVELOPPE BAES-BLANC, BETCE-ETIQUETTE-VERT 0-193-0, BETCE-VITRE BAES-BLEU
Pset_BuildingElementProxyCommon - Reference: GAUCHE; sets with these values: 2
Name (Eclairage de sécurité saillie étanche mur:GAUCHE:...)
3964791
6178125

# IfcBuildingElementProxy: Eclairage de sécurité saillie étanche mur:GAUCHE/DROITE, Eclairage de sécurité saillie étanche mur:GAUCHE/DROITE:3964792
In: Niveau 0
Type - Material: BETCE-ENVELOPPE BAES-BLANC, BETCE-ETIQUETTE-VERT 0-193-0, BETCE-VITRE BAES-BLEU
Pset_BuildingElementProxyCommon - Reference: GAUCHE/DROITE; sets with these values: 2

# IfcBuildingElementProxy: Eclairage de sécurité saillie étanche mur:SORTIE, Eclairage de sécurité saillie étanche mur:SORTIE:5859841
In: Niveau 0
Type - Material: BETCE-ETIQUETTE-BLANC, BETCE-ETIQUETTE-VERT 0-193-0, BETCE-VITRE BAES-BLEU, BETCE-ENVELOPPE BAES-BLANC
Pset_BuildingElementProxyCommon - Reference: SORTIE; sets with these values: 2

# IfcBuildingElementProxy: Eclairage de sécurité saillie étanche plafond:AMBIANCE, Eclairage de sécurité saillie étanche plafond:AMBIANCE:3975054
In: Niveau 0
Type - Material: BETCE-ETIQUETTE-BLANC, BETCE-ETIQUETTE-VERT 0-193-0, BETCE-VITRE BAES-BLEU, BETCE-ENVELOPPE-BLANC
Pset_BuildingElementProxyCommon - Reference: AMBIANCE; sets with these values: 2

# IfcBuildingElementProxy: Eclairage de sécurité saillie étanche plafond:BAS, Eclairage de sécurité saillie étanche plafond:BAS:3975179
In: Niveau 0
Type - Material: BETCE-ENVELOPPE-BLANC, BETCE-ETIQUETTE-VERT 0-193-0, BETCE-VITRE BAES-BLEU
Pset_BuildingElementProxyCommon - Reference: BAS; sets with these values: 2

# IfcBuildingElementProxy: Eclairage de sécurité saillie étanche plafond:DROITE, Eclairage de sécurité saillie étanche plafond:DROITE:3975305
In: Niveau 0
Type - Material: BETCE-ENVELOPPE-BLANC, BETCE-ETIQUETTE-VERT 0-193-0, BETCE-VITRE BAES-BLEU
Pset_BuildingElementProxyCommon - Reference: DROITE; sets with these values: 2

# IfcBuildingElementProxy: Eclairage de sécurité saillie étanche plafond:GAUCHE (2)
In: Niveau 0
Type - Material: BETCE-ENVELOPPE-BLANC, BETCE-ETIQUETTE-VERT 0-193-0, BETCE-VITRE BAES-BLEU
Pset_BuildingElementProxyCommon - Reference: GAUCHE; sets with these values: 2
Name (Eclairage de sécurité saillie étanche plafond:GAUCHE:...)
3975413
6178080

# IfcBuildingElementProxy: Eclairage de sécurité saillie étanche plafond:GAUCHE/DROITE, Eclairage de sécurité saillie étanche plafond:GAUCHE/DROITE:3975563
In: Niveau 0
Type - Material: BETCE-ETIQUETTE-VERT 0-193-0, BETCE-ENVELOPPE-BLANC, BETCE-VITRE BAES-BLEU
Pset_BuildingElementProxyCommon - Reference: GAUCHE/DROITE; sets with these values: 2

# IfcBuildingElementProxy: Eclairage de sécurité saillie étanche plafond:SORTIE (3)
In: Niveau 0
Type - Material: BETCE-ETIQUETTE-VERT 0-193-0, BETCE-ENVELOPPE-BLANC, BETCE-VITRE BAES-BLEU
Pset_BuildingElementProxyCommon - Reference: SORTIE; sets with these values: 2
Name (Eclairage de sécurité saillie étanche plafond:SORTIE:...)
5893869
6178060
6178117

# IfcBuildingElementProxy: Enceinte saillie:Enceinte 12W metal bi-directional, Enceinte saillie:Enceinte 12W metal bi-directional:5299802
In: Niveau 0
Type - Material: Screw - Bosch
Type - Pset_ManufacturerTypeInformation - Manufacturer: Bosch
Classification: E1010 Commercial Equipment (Uniformat); Material: Screw - Bosch, <Unnamed>, White (RAL 9010) - Bosch
Pset_BuildingElementProxyCommon - Reference: Enceinte 12W metal bi-directional; sets with these values: 2

# IfcBuildingElementProxy: Enceinte saillie:Enceinte 20W metal unidirectional, Enceinte saillie:Enceinte 20W metal unidirectional:5300409
In: Niveau 0
Type - Material: White (RAL 9010) - Bosch, Screw - Bosch, <Unnamed>
Type - Pset_ManufacturerTypeInformation - Manufacturer: Bosch
Classification: E1010 Commercial Equipment (Uniformat)
Pset_BuildingElementProxyCommon - Reference: Enceinte 20W metal unidirectional; sets with these values: 2

# IfcBuildingElementProxy: Inter à clé tous terminaux encastré:Inter à clé (3)
In: Niveau 0
Type - Material: A-ENJOLIVEUR BLANC, LG - Black, LG - Métal fiche, LG - White
Type - Pset_ManufacturerTypeInformation - Manufacturer: Legrand
Pset_BuildingElementProxyCommon - Reference: Inter à clé; sets with these values: 2
Name (Inter à clé tous terminaux encastré:Inter à clé:...)
3330867
6175141
6253580

# IfcBuildingElementProxy: Interrupteur double encastré étanche:Double allumage, Interrupteur double encastré étanche:Double allumage:3351710
In: Niveau 0
Type - Material: A-PVC GRIS 85-85-85, A PVC GRIS 177-177-177
Pset_BuildingElementProxyCommon - Reference: Double allumage; sets with these values: 2

# IfcBuildingElementProxy: Interrupteur double encastré étanche:Double bouton poussoir, Interrupteur double encastré étanche:Double bouton poussoir:3351402
In: Niveau 0
Type - Material: A-PVC GRIS 85-85-85, A PVC GRIS 177-177-177
Pset_BuildingElementProxyCommon - Reference: Double bouton poussoir; sets with these values: 2

# IfcBuildingElementProxy: Interrupteur double encastré étanche:Double va et vient, Interrupteur double encastré étanche:Double va et vient:3351902
In: Niveau 0
Type - Material: A-PVC GRIS 85-85-85, A PVC GRIS 177-177-177
Pset_BuildingElementProxyCommon - Reference: Double va et vient; sets with these values: 2

# IfcBuildingElementProxy: Interrupteur double encastré étanche:Simple allumage+Bouton poussoir, Interrupteur double encastré étanche:Simple allumage+Bouton poussoir:3352453
In: Niveau 0
Type - Material: A-PVC GRIS 85-85-85, A PVC GRIS 177-177-177
Pset_BuildingElementProxyCommon - Reference: Simple allumage+Bouton poussoir; sets with these values: 2

# IfcBuildingElementProxy: Interrupteur double encastré étanche:Simple allumage+Va et vient, Interrupteur double encastré étanche:Simple allumage+Va et vient:3352599
In: Niveau 0
Type - Material: A-PVC GRIS 85-85-85, A PVC GRIS 177-177-177
Pset_BuildingElementProxyCommon - Reference: Simple allumage+Va et vient; sets with these values: 2

# IfcBuildingElementProxy: Interrupteur double encastré étanche:Va et vient+Bouton poussoir, Interrupteur double encastré étanche:Va et vient+Bouton poussoir:3352761
In: Niveau 0
Type - Material: A-PVC GRIS 85-85-85, A PVC GRIS 177-177-177
Pset_BuildingElementProxyCommon - Reference: Va et vient+Bouton poussoir; sets with these values: 2

# IfcBuildingElementProxy: Interrupteur double encastré:Double allumage, Interrupteur double encastré:Double allumage:3330834
In: Niveau 0
Type - Material: BETCE-DOIGT-BLANC, BETCE-ENJOLIVEUR-BLANC, <Unnamed>
Pset_BuildingElementProxyCommon - Reference: Double allumage; sets with these values: 2

# IfcBuildingElementProxy: Interrupteur double encastré:Double bouton poussoir, Interrupteur double encastré:Double bouton poussoir:3330835
In: Niveau 0
Type - Material: BETCE-DOIGT-BLANC, BETCE-ENJOLIVEUR-BLANC, <Unnamed>
Pset_BuildingElementProxyCommon - Reference: Double bouton poussoir; sets with these values: 2

# IfcBuildingElementProxy: Interrupteur double encastré:Double va et vient, Interrupteur double encastré:Double va et vient:3330836
In: Niveau 0
Type - Material: BETCE-DOIGT-BLANC, BETCE-ENJOLIVEUR-BLANC, <Unnamed>
Pset_BuildingElementProxyCommon - Reference: Double va et vient; sets with these values: 2

# IfcBuildingElementProxy: Interrupteur double encastré:Simple allumage+Bouton poussoir, Interrupteur double encastré:Simple allumage+Bouton poussoir:3330837
In: Niveau 0
Type - Material: BETCE-DOIGT-BLANC, BETCE-ENJOLIVEUR-BLANC, <Unnamed>
Pset_BuildingElementProxyCommon - Reference: Simple allumage+Bouton poussoir; sets with these values: 2

# IfcBuildingElementProxy: Interrupteur double encastré:Simple allumage+Va et vient, Interrupteur double encastré:Simple allumage+Va et vient:3330838
In: Niveau 0
Type - Material: BETCE-DOIGT-BLANC, BETCE-ENJOLIVEUR-BLANC, <Unnamed>
Pset_BuildingElementProxyCommon - Reference: Simple allumage+Va et vient; sets with these values: 2

# IfcBuildingElementProxy: Interrupteur double encastré:Va et vient+Bouton poussoir, Interrupteur double encastré:Va et vient+Bouton poussoir:3330839
In: Niveau 0
Type - Material: BETCE-DOIGT-BLANC, BETCE-ENJOLIVEUR-BLANC, <Unnamed>
Pset_BuildingElementProxyCommon - Reference: Va et vient+Bouton poussoir; sets with these values: 2

# IfcBuildingElementProxy: Interrupteur double saillie étanche:Double allumage, Interrupteur double saillie étanche:Double allumage:3357135
In: Niveau 0
Type - Material: A PVC GRIS 177-177-177, A-PVC GRIS 85-85-85
Pset_BuildingElementProxyCommon - Reference: Double allumage; sets with these values: 2

# IfcBuildingElementProxy: Interrupteur double saillie étanche:Double bouton poussoir, Interrupteur double saillie étanche:Double bouton poussoir:3357379
In: Niveau 0
Type - Material: A PVC GRIS 177-177-177, A-PVC GRIS 85-85-85
Pset_BuildingElementProxyCommon - Reference: Double bouton poussoir; sets with these values: 2

# IfcBuildingElementProxy: Interrupteur double saillie étanche:Double va et vient, Interrupteur double saillie étanche:Double va et vient:3357553
In: Niveau 0
Type - Material: A PVC GRIS 177-177-177, A-PVC GRIS 85-85-85
Pset_BuildingElementProxyCommon - Reference: Double va et vient; sets with these values: 2

# IfcBuildingElementProxy: Interrupteur double saillie étanche:Simple allumage+Bouton poussoir, Interrupteur double saillie étanche:Simple allumage+Bouton poussoir:3357773
In: Niveau 0
Type - Material: A PVC GRIS 177-177-177, A-PVC GRIS 85-85-85
Pset_BuildingElementProxyCommon - Reference: Simple allumage+Bouton poussoir; sets with these values: 2

# IfcBuildingElementProxy: Interrupteur double saillie étanche:Simple allumage+Va et vient, Interrupteur double saillie étanche:Simple allumage+Va et vient:3357899
In: Niveau 0
Type - Material: A PVC GRIS 177-177-177, A-PVC GRIS 85-85-85
Pset_BuildingElementProxyCommon - Reference: Simple allumage+Va et vient; sets with these values: 2

# IfcBuildingElementProxy: Interrupteur double saillie étanche:Va et vient+Bouton poussoir, Interrupteur double saillie étanche:Va et vient+Bouton poussoir:3358027
In: Niveau 0
Type - Material: A PVC GRIS 177-177-177, A-PVC GRIS 85-85-85
Pset_BuildingElementProxyCommon - Reference: Va et vient+Bouton poussoir; sets with these values: 2

# IfcBuildingElementProxy: Interrupteur double saillie:Double allumage, Interrupteur double saillie:Double allumage:3330851
In: Niveau 0
Type - Material: BETCE-DOITGT-BLANC, BETCE-CADRE-BLANC, BETCE-ENJOLIVEUR-BLANC
Pset_BuildingElementProxyCommon - Reference: Double allumage; sets with these values: 2

# IfcBuildingElementProxy: Interrupteur double saillie:Double bouton poussoir, Interrupteur double saillie:Double bouton poussoir:3330850
In: Niveau 0
Type - Material: BETCE-DOITGT-BLANC, BETCE-CADRE-BLANC, BETCE-ENJOLIVEUR-BLANC
Pset_BuildingElementProxyCommon - Reference: Double bouton poussoir; sets with these values: 2

# IfcBuildingElementProxy: Interrupteur double saillie:Double va et vient, Interrupteur double saillie:Double va et vient:3330852
In: Niveau 0
Type - Material: BETCE-DOITGT-BLANC, BETCE-CADRE-BLANC, BETCE-ENJOLIVEUR-BLANC
Pset_BuildingElementProxyCommon - Reference: Double va et vient; sets with these values: 2

# IfcBuildingElementProxy: Interrupteur double saillie:Simple allumage+Bouton poussoir, Interrupteur double saillie:Simple allumage+Bouton poussoir:3330853
In: Niveau 0
Type - Material: BETCE-DOITGT-BLANC, BETCE-CADRE-BLANC, BETCE-ENJOLIVEUR-BLANC
Pset_BuildingElementProxyCommon - Reference: Simple allumage+Bouton poussoir; sets with these values: 2

# IfcBuildingElementProxy: Interrupteur double saillie:Simple allumage+Va et vient, Interrupteur double saillie:Simple allumage+Va et vient:3330854
In: Niveau 0
Type - Material: BETCE-DOITGT-BLANC, BETCE-CADRE-BLANC, BETCE-ENJOLIVEUR-BLANC
Pset_BuildingElementProxyCommon - Reference: Simple allumage+Va et vient; sets with these values: 2

# IfcBuildingElementProxy: Interrupteur double saillie:Va et vient+Bouton poussoir, Interrupteur double saillie:Va et vient+Bouton poussoir:3330855
In: Niveau 0
Type - Material: BETCE-DOITGT-BLANC, BETCE-CADRE-BLANC, BETCE-ENJOLIVEUR-BLANC
Pset_BuildingElementProxyCommon - Reference: Va et vient+Bouton poussoir; sets with these values: 2

# IfcBuildingElementProxy: Interrupteur simple encastré étanche:Bouton poussoir, Interrupteur simple encastré étanche:Bouton poussoir:3330875
In: Niveau 0
Type - Material: A-PVC GRIS 85-85-85, A PVC GRIS 177-177-177
Pset_BuildingElementProxyCommon - Reference: Bouton poussoir; sets with these values: 2

# IfcBuildingElementProxy: Interrupteur simple encastré étanche:Simple allumage, Interrupteur simple encastré étanche:Simple allumage:3330876
In: Niveau 0
Type - Material: A-PVC GRIS 85-85-85, A PVC GRIS 177-177-177
Pset_BuildingElementProxyCommon - Reference: Simple allumage; sets with these values: 2

# IfcBuildingElementProxy: Interrupteur simple encastré étanche:Va et vient, Interrupteur simple encastré étanche:Va et vient:3330877
In: Niveau 0
Type - Material: A-PVC GRIS 85-85-85, A PVC GRIS 177-177-177
Pset_BuildingElementProxyCommon - Reference: Va et vient; sets with these values: 2

# IfcBuildingElementProxy: Interrupteur simple encastré:Bouton poussoir, Interrupteur simple encastré:Bouton poussoir:3330831
In: Niveau 0
Type - Material: BETCE-DOIGT-BLANC, BETCE-ENJOLIVEUR-BLANC, <Unnamed>
Pset_BuildingElementProxyCommon - Reference: Bouton poussoir; sets with these values: 2

# IfcBuildingElementProxy: Interrupteur simple encastré:Simple allumage, Interrupteur simple encastré:Simple allumage:3330832
In: Niveau 0
Type - Material: BETCE-DOIGT-BLANC, BETCE-ENJOLIVEUR-BLANC, <Unnamed>
Pset_BuildingElementProxyCommon - Reference: Simple allumage; sets with these values: 2

# IfcBuildingElementProxy: Interrupteur simple encastré:Va et vient, Interrupteur simple encastré:Va et vient:3330833
In: Niveau 0
Type - Material: BETCE-DOIGT-BLANC, BETCE-ENJOLIVEUR-BLANC, <Unnamed>
Pset_BuildingElementProxyCommon - Reference: Va et vient; sets with these values: 2

# IfcBuildingElementProxy: Interrupteur simple saillie étanche:Bouton poussoir, Interrupteur simple saillie étanche:Bouton poussoir:3346601
In: Niveau 0
Type - Material: A-PVC GRIS 85-85-85, A PVC GRIS 177-177-177
Pset_BuildingElementProxyCommon - Reference: Bouton poussoir; sets with these values: 2

# IfcBuildingElementProxy: Interrupteur simple saillie étanche:Simple allumage, Interrupteur simple saillie étanche:Simple allumage:3346927
In: Niveau 0
Type - Material: A-PVC GRIS 85-85-85, A PVC GRIS 177-177-177
Pset_BuildingElementProxyCommon - Reference: Simple allumage; sets with these values: 2

# IfcBuildingElementProxy: Interrupteur simple saillie étanche:Va et vient, Interrupteur simple saillie étanche:Va et vient:3347101
In: Niveau 0
Type - Material: A-PVC GRIS 85-85-85, A PVC GRIS 177-177-177
Pset_BuildingElementProxyCommon - Reference: Va et vient; sets with these values: 2

# IfcBuildingElementProxy: Interrupteur simple saillie:Bouton poussoir, Interrupteur simple saillie:Bouton poussoir:3330847
In: Niveau 0
Type - Material: BETCE-CADRE-BLANC, BETCE-DOIGT-BLANC, BETCE-ENJOLIVEUR-BLANC
Pset_BuildingElementProxyCommon - Reference: Bouton poussoir; sets with these values: 2

# IfcBuildingElementProxy: Interrupteur simple saillie:Simple allumage, Interrupteur simple saillie:Simple allumage:3330848
In: Niveau 0
Type - Material: BETCE-CADRE-BLANC, BETCE-DOIGT-BLANC, BETCE-ENJOLIVEUR-BLANC
Pset_BuildingElementProxyCommon - Reference: Simple allumage; sets with these values: 2

# IfcBuildingElementProxy: Interrupteur simple saillie:Va et vient, Interrupteur simple saillie:Va et vient:3330849
In: Niveau 0
Type - Material: BETCE-CADRE-BLANC, BETCE-DOIGT-BLANC, BETCE-ENJOLIVEUR-BLANC
Pset_BuildingElementProxyCommon - Reference: Va et vient; sets with these values: 2

# IfcBuildingElementProxy: Interrupteur volet roulant encastré:ORANGE, Interrupteur volet roulant encastré:ORANGE:4918342
In: Niveau 0
Type - Material: BETCE-DOIGT VR-BLANC, BETCE-ENJOLIVEUR VR-BLANC, <Unnamed>
Pset_BuildingElementProxyCommon - Reference: ORANGE; sets with these values: 2

# IfcBuildingElementProxy: Interrupteur volet roulant encastré:VERT, Interrupteur volet roulant encastré:VERT:4918420
In: Niveau 0
Type - Material: BETCE-DOIGT VR-BLANC, BETCE-ENJOLIVEUR VR-BLANC, <Unnamed>
Pset_BuildingElementProxyCommon - Reference: VERT; sets with these values: 2

# IfcBuildingElementProxy: Interrupteur volet roulant encastré:Volet roulant, Interrupteur volet roulant encastré:Volet roulant:3330869
In: Niveau 0
Type - Material: BETCE-DOIGT VR-BLANC, BETCE-ENJOLIVEUR VR-BLANC, <Unnamed>
Pset_BuildingElementProxyCommon - Reference: Volet roulant; sets with these values: 2

# IfcBuildingElementProxy: Interrupteur volet roulant saillie étanche:NOIR, Interrupteur volet roulant saillie étanche:NOIR:3365082
In: Niveau 0
Type - Material: PLEXO_Gris cache, PLEXO_Gris, PLEXO_Gris_Gris
Type - Pset_ManufacturerTypeInformation - Manufacturer: Legrand
Pset_BuildingElementProxyCommon - Reference: NOIR; sets with these values: 2

# IfcBuildingElementProxy: Interrupteur volet roulant saillie étanche:ORANGE, Interrupteur volet roulant saillie étanche:ORANGE:4257692
In: Niveau 0
Type - Material: PLEXO_Gris cache, PLEXO_Gris, PLEXO_Gris_Gris
Type - Pset_ManufacturerTypeInformation - Manufacturer: Legrand
Pset_BuildingElementProxyCommon - Reference: ORANGE; sets with these values: 2

# IfcBuildingElementProxy: Interrupteur volet roulant saillie étanche:VERT, Interrupteur volet roulant saillie étanche:VERT:4257699
In: Niveau 0
Type - Material: PLEXO_Gris cache, PLEXO_Gris, PLEXO_Gris_Gris
Type - Pset_ManufacturerTypeInformation - Manufacturer: Legrand
Pset_BuildingElementProxyCommon - Reference: VERT; sets with these values: 2

# IfcBuildingElementProxy: Interrupteur volet roulant saillie:ORANGE, Interrupteur volet roulant saillie:ORANGE:4267560
In: Niveau 0
Type - Material: BETCE-DOIGT-BLANC, <Unnamed>, BETCE-ENJOLIVEUR PC-BLANC
Pset_BuildingElementProxyCommon - Reference: ORANGE; sets with these values: 2

# IfcBuildingElementProxy: Interrupteur volet roulant saillie:VERT, Interrupteur volet roulant saillie:VERT:4267690
In: Niveau 0
Type - Material: BETCE-DOIGT-BLANC, <Unnamed>, BETCE-ENJOLIVEUR PC-BLANC
Pset_BuildingElementProxyCommon - Reference: VERT; sets with these values: 2

# IfcBuildingElementProxy: Interrupteur volet roulant saillie:Volet roulant, Interrupteur volet roulant saillie:Volet roulant:3330870
In: Niveau 0
Type - Material: BETCE-DOIGT-BLANC, <Unnamed>, BETCE-ENJOLIVEUR PC-BLANC
Pset_BuildingElementProxyCommon - Reference: Volet roulant; sets with these values: 2

# IfcBuildingElementProxy: Interrupteur à clé éclairage encastré:Inter à clé, Interrupteur à clé éclairage encastré:Inter à clé:3330844
In: Niveau 0
Type - Material: A-ENJOLIVEUR BLANC, LG - Black, LG - Métal fiche, LG - White
Type - Pset_ManufacturerTypeInformation - Manufacturer: Legrand
Pset_BuildingElementProxyCommon - Reference: Inter à clé; sets with these values: 2

# IfcBuildingElementProxy: Lecteur de badge + clavier saillie controle acces:Bleu, Lecteur de badge + clavier saillie controle acces:Bleu:4103419
In: Niveau 0
Type - Material: BETCE-VOYANT-BLEU, BETCE-NUMEROTATION-BLANC, BETCE-CLAVIER-NOIR, BETCE-BOITIER-NOIR
Pset_BuildingElementProxyCommon - Reference: Bleu; sets with these values: 2

# IfcBuildingElementProxy: Lecteur de badge + clavier saillie controle acces:Gris, Lecteur de badge + clavier saillie controle acces:Gris:4109327
In: Niveau 0
Type - Material: BETCE-VOYANT-BLEU, BETCE-NUMEROTATION-BLANC, BETCE-CLAVIER-NOIR, BETCE-BOITIER-NOIR
Pset_BuildingElementProxyCommon - Reference: Gris; sets with these values: 2

# IfcBuildingElementProxy: Lecteur de badge + clavier saillie controle acces:Magenta, Lecteur de badge + clavier saillie controle acces:Magenta:4109399
In: Niveau 0
Type - Material: BETCE-VOYANT-BLEU, BETCE-NUMEROTATION-BLANC, BETCE-CLAVIER-NOIR, BETCE-BOITIER-NOIR
Pset_BuildingElementProxyCommon - Reference: Magenta; sets with these values: 2

# IfcBuildingElementProxy: Lecteur de badge + clavier saillie controle acces:Marron, Lecteur de badge + clavier saillie controle acces:Marron:4109461
In: Niveau 0
Type - Material: BETCE-VOYANT-BLEU, BETCE-NUMEROTATION-BLANC, BETCE-CLAVIER-NOIR, BETCE-BOITIER-NOIR
Pset_BuildingElementProxyCommon - Reference: Marron; sets with these values: 2

# IfcBuildingElementProxy: Lecteur de badge + clavier saillie controle acces:Noir, Lecteur de badge + clavier saillie controle acces:Noir:4109539
In: Niveau 0
Type - Material: BETCE-VOYANT-BLEU, BETCE-NUMEROTATION-BLANC, BETCE-CLAVIER-NOIR, BETCE-BOITIER-NOIR
Pset_BuildingElementProxyCommon - Reference: Noir; sets with these values: 2

# IfcBuildingElementProxy: Lecteur de badge + clavier saillie controle acces:Orange, Lecteur de badge + clavier saillie controle acces:Orange:4109619
In: Niveau 0
Type - Material: BETCE-VOYANT-BLEU, BETCE-NUMEROTATION-BLANC, BETCE-CLAVIER-NOIR, BETCE-BOITIER-NOIR
Pset_BuildingElementProxyCommon - Reference: Orange; sets with these values: 2

# IfcBuildingElementProxy: Lecteur de badge + clavier saillie controle acces:Rouge, Lecteur de badge + clavier saillie controle acces:Rouge:4109725
In: Niveau 0
Type - Material: BETCE-VOYANT-BLEU, BETCE-NUMEROTATION-BLANC, BETCE-CLAVIER-NOIR, BETCE-BOITIER-NOIR
Pset_BuildingElementProxyCommon - Reference: Rouge; sets with these values: 2

# IfcBuildingElementProxy: Lecteur de badge + clavier saillie controle acces:Vert, Lecteur de badge + clavier saillie controle acces:Vert:4109827
In: Niveau 0
Type - Material: BETCE-VOYANT-BLEU, BETCE-NUMEROTATION-BLANC, BETCE-CLAVIER-NOIR, BETCE-BOITIER-NOIR
Pset_BuildingElementProxyCommon - Reference: Vert; sets with these values: 2

# IfcBuildingElementProxy: Lecteur de badge saillie controle acces:BLEU, Lecteur de badge saillie controle acces:BLEU:4124062
In: Niveau 0
Type - Material: BETCE-VOYANT LECTEUR BADGE-VERT, BETCE-LECTEUR BADGE-NOIR
Pset_BuildingElementProxyCommon - Reference: BLEU; sets with these values: 2

# IfcBuildingElementProxy: Lecteur de badge saillie controle acces:GRIS, Lecteur de badge saillie controle acces:GRIS:4124174
In: Niveau 0
Type - Material: BETCE-VOYANT LECTEUR BADGE-VERT, BETCE-LECTEUR BADGE-NOIR
Pset_BuildingElementProxyCommon - Reference: GRIS; sets with these values: 2

# IfcBuildingElementProxy: Lecteur de badge saillie controle acces:MAGENTA, Lecteur de badge saillie controle acces:MAGENTA:4124222
In: Niveau 0
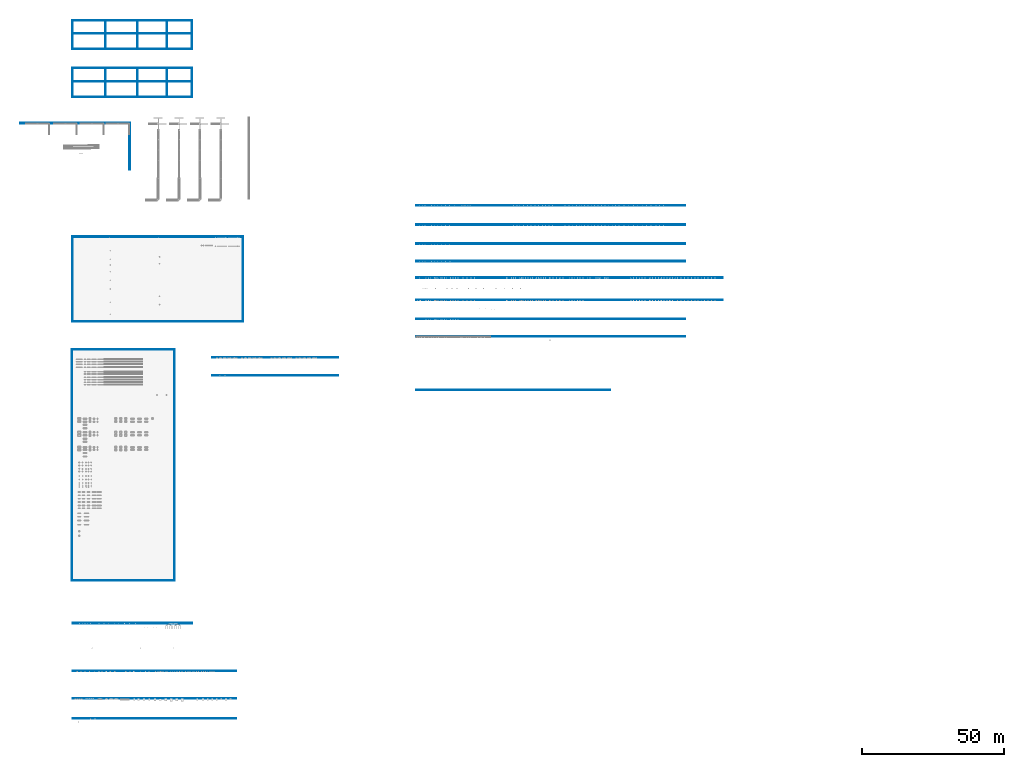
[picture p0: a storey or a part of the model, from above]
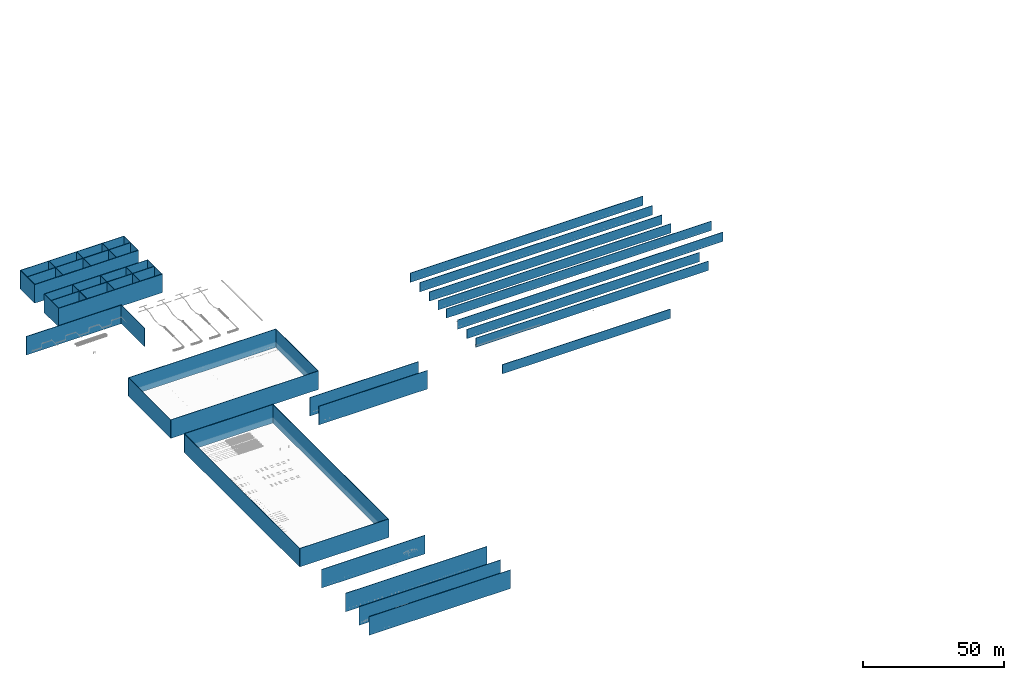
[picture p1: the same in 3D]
Properties of the parts of a building model (IFC2X3), part 2 of 5

# IfcBuildingElementProxy: Lecteur de badge saillie controle acces:MAGENTA, Lecteur de badge saillie controle acces:MAGENTA:4124222
Type - Material: BETCE-VOYANT LECTEUR BADGE-VERT, BETCE-LECTEUR BADGE-NOIR
Pset_BuildingElementProxyCommon - Reference: MAGENTA; sets with these values: 2

# IfcBuildingElementProxy: Lecteur de badge saillie controle acces:MARRON, Lecteur de badge saillie controle acces:MARRON:4124274
In: Niveau 0
Type - Material: BETCE-VOYANT LECTEUR BADGE-VERT, BETCE-LECTEUR BADGE-NOIR
Pset_BuildingElementProxyCommon - Reference: MARRON; sets with these values: 2

# IfcBuildingElementProxy: Lecteur de badge saillie controle acces:NOIR, Lecteur de badge saillie controle acces:NOIR:4124314
In: Niveau 0
Type - Material: BETCE-VOYANT LECTEUR BADGE-VERT, BETCE-LECTEUR BADGE-NOIR
Pset_BuildingElementProxyCommon - Reference: NOIR; sets with these values: 2

# IfcBuildingElementProxy: Lecteur de badge saillie controle acces:ORANGE, Lecteur de badge saillie controle acces:ORANGE:4124400
In: Niveau 0
Type - Material: BETCE-VOYANT LECTEUR BADGE-VERT, BETCE-LECTEUR BADGE-NOIR
Pset_BuildingElementProxyCommon - Reference: ORANGE; sets with these values: 2

# IfcBuildingElementProxy: Lecteur de badge saillie controle acces:ROUGE, Lecteur de badge saillie controle acces:ROUGE:4124502
In: Niveau 0
Type - Material: BETCE-VOYANT LECTEUR BADGE-VERT, BETCE-LECTEUR BADGE-NOIR
Pset_BuildingElementProxyCommon - Reference: ROUGE; sets with these values: 2

# IfcBuildingElementProxy: Lecteur de badge saillie controle acces:VERT, Lecteur de badge saillie controle acces:VERT:4124568
In: Niveau 0
Type - Material: BETCE-VOYANT LECTEUR BADGE-VERT, BETCE-LECTEUR BADGE-NOIR
Pset_BuildingElementProxyCommon - Reference: VERT; sets with these values: 2

# IfcBuildingElementProxy: Plot pour CDC:Plot pour CDC, Plot pour CDC:Plot pour CDC:3329415
In: Niveau 0
Type - Material: <Unnamed>
Pset_BuildingElementProxyCommon - Reference: Plot pour CDC; sets with these values: 2

# IfcBuildingElementProxy: Poste travail encastré 1x2 modules-1HDMI:1PCN+1HDMI, Poste travail encastré 1x2 modules-1HDMI:1PCN+1HDMI:4613957
In: Niveau 0
Type - Material: BETCE-ENJOLIVEUR PC-BLANC, <Unnamed>, BETCE-PCN-BLANC
Pset_BuildingElementProxyCommon - Reference: 1PCN+1HDMI; sets with these values: 2

# IfcBuildingElementProxy: Poste travail encastré 1x2 modules-1HDMI:1PCO+1HDMI, Poste travail encastré 1x2 modules-1HDMI:1PCO+1HDMI:4614197
In: Niveau 0
Type - Material: BETCE-ENJOLIVEUR PC-BLANC, BETCE-HDMI-BLANC, <Unnamed>, BETCE-PCO-ROUGE
Pset_BuildingElementProxyCommon - Reference: 1PCO+1HDMI; sets with these values: 2

# IfcBuildingElementProxy: Poste travail encastré 1x2 modules-1RJ:1PCN+1RJ, Poste travail encastré 1x2 modules-1RJ:1PCN+1RJ:3697498
In: Niveau 0
Type - Material: BETCE-ENJOLIVEUR PC-BLANC, BETCE-ETIQUETTE RJ-BLEU, <Unnamed>, BETCE-PCN-BLANC
Pset_BuildingElementProxyCommon - Reference: 1PCN+1RJ; sets with these values: 2

# IfcBuildingElementProxy: Poste travail encastré 1x2 modules-1RJ:1PCO+1RJ, Poste travail encastré 1x2 modules-1RJ:1PCO+1RJ:3697912
In: Niveau 0
Type - Material: BETCE-ENJOLIVEUR PC-BLANC, BETCE-ETIQUETTE RJ-BLEU, <Unnamed>, BETCE-PCO-ROUGE
Pset_BuildingElementProxyCommon - Reference: 1PCO+1RJ; sets with these values: 2

# IfcBuildingElementProxy: Poste travail encastré 1x2 modules-HDMI_USB sur sortie cable:1PCN+1HDMI+1USB, Poste travail encastré 1x2 modules-HDMI_USB sur sortie cable:1PCN+1HDMI+1USB:4955996
In: Niveau 0
Type - Material: <Unnamed>, BETCE-PCN-BLANC, BETCE-PVC-PRISE - BLANC, BETCE-PVC-ENJOLIVEUR - BLANC
Pset_BuildingElementProxyCommon - Reference: 1PCN+1HDMI+1USB; sets with these values: 2

# IfcBuildingElementProxy: Poste travail encastré 1x2 modules-HDMI_USB sur sortie cable:1PCN+2HDMI, Poste travail encastré 1x2 modules-HDMI_USB sur sortie cable:1PCN+2HDMI:4956080
In: Niveau 0
Type - Material: <Unnamed>, BETCE-PCN-BLANC, BETCE-PVC-PRISE - BLANC, BETCE-PVC-ENJOLIVEUR - BLANC
Pset_BuildingElementProxyCommon - Reference: 1PCN+2HDMI; sets with these values: 2

# IfcBuildingElementProxy: Poste travail encastré 1x2 modules-HDMI_USB sur sortie cable:1PCN+2USB, Poste travail encastré 1x2 modules-HDMI_USB sur sortie cable:1PCN+2USB:4956272
In: Niveau 0
Type - Material: <Unnamed>, BETCE-PCN-BLANC, BETCE-PVC-PRISE - BLANC, BETCE-PVC-ENJOLIVEUR - BLANC
Pset_BuildingElementProxyCommon - Reference: 1PCN+2USB; sets with these values: 2

# IfcBuildingElementProxy: Poste travail encastré 1x2 modules-HDMI_USB sur sortie cable:1PCO+1HDMI+1USB, Poste travail encastré 1x2 modules-HDMI_USB sur sortie cable:1PCO+1HDMI+1USB:4956386
In: Niveau 0
Type - Material: <Unnamed>, BETCE-PCN-BLANC, BETCE-PVC-PRISE - ROUGE, BETCE-PVC-ENJOLIVEUR - BLANC
Pset_BuildingElementProxyCommon - Reference: 1PCO+1HDMI+1USB; sets with these values: 2

# IfcBuildingElementProxy: Poste travail encastré 1x2 modules-HDMI_USB sur sortie cable:1PCO+2HDMI, Poste travail encastré 1x2 modules-HDMI_USB sur sortie cable:1PCO+2HDMI:4956454
In: Niveau 0
Type - Material: <Unnamed>, BETCE-PCN-BLANC, BETCE-PVC-PRISE - ROUGE, BETCE-PVC-ENJOLIVEUR - BLANC
Pset_BuildingElementProxyCommon - Reference: 1PCO+2HDMI; sets with these values: 2

# IfcBuildingElementProxy: Poste travail encastré 1x2 modules-HDMI_USB sur sortie cable:1PCO+2USB, Poste travail encastré 1x2 modules-HDMI_USB sur sortie cable:1PCO+2USB:4956524
In: Niveau 0
Type - Material: <Unnamed>, BETCE-PCN-BLANC, BETCE-PVC-PRISE - ROUGE, BETCE-PVC-ENJOLIVEUR - BLANC
Pset_BuildingElementProxyCommon - Reference: 1PCO+2USB; sets with these values: 2

# IfcBuildingElementProxy: Poste travail encastré 1x3 modules-1RJ+HDMI_USB sur sortie cable:1PCN+1RJ+1HDMI+1USB, Poste travail encastré 1x3 modules-1RJ+HDMI_USB sur sortie cable:1PCN+1RJ+1HDMI+1USB:3712207
In: Niveau 0
Type - Material: <Unnamed>, BETCE-PCN-BLANC, BETCE-ENJOLIVEUR PC-BLANC, BETCE-ETIQUETTE RJ-BLEU
Pset_BuildingElementProxyCommon - Reference: 1PCN+1RJ+1HDMI+1USB; sets with these values: 2

# IfcBuildingElementProxy: Poste travail encastré 1x3 modules-1RJ+HDMI_USB sur sortie cable:1PCN+1RJ+2HDMI, Poste travail encastré 1x3 modules-1RJ+HDMI_USB sur sortie cable:1PCN+1RJ+2HDMI:3713551
In: Niveau 0
Type - Material: <Unnamed>, BETCE-PCN-BLANC, BETCE-ENJOLIVEUR PC-BLANC, BETCE-ETIQUETTE RJ-BLEU
Pset_BuildingElementProxyCommon - Reference: 1PCN+1RJ+2HDMI; sets with these values: 2

# IfcBuildingElementProxy: Poste travail encastré 1x3 modules-1RJ+HDMI_USB sur sortie cable:1PCN+1RJ+2USB, Poste travail encastré 1x3 modules-1RJ+HDMI_USB sur sortie cable:1PCN+1RJ+2USB:3713641
In: Niveau 0
Type - Material: <Unnamed>, BETCE-PCN-BLANC, BETCE-ENJOLIVEUR PC-BLANC, BETCE-ETIQUETTE RJ-BLEU
Pset_BuildingElementProxyCommon - Reference: 1PCN+1RJ+2USB; sets with these values: 2

# IfcBuildingElementProxy: Poste travail encastré 1x3 modules-1RJ+HDMI_USB sur sortie cable:1PCO+1RJ+1HDMI+1USB, Poste travail encastré 1x3 modules-1RJ+HDMI_USB sur sortie cable:1PCO+1RJ+1HDMI+1USB:3713757
In: Niveau 0
Type - Material: <Unnamed>, BETCE-PCN-BLANC, BETCE-ENJOLIVEUR PC-BLANC, BETCE-ETIQUETTE RJ-BLEU, BETCE-PCO-ROUGE
Pset_BuildingElementProxyCommon - Reference: 1PCO+1RJ+1HDMI+1USB; sets with these values: 2

# IfcBuildingElementProxy: Poste travail encastré 1x3 modules-1RJ+HDMI_USB sur sortie cable:1PCO+1RJ+2HDMI, Poste travail encastré 1x3 modules-1RJ+HDMI_USB sur sortie cable:1PCO+1RJ+2HDMI:3713841
In: Niveau 0
Type - Material: <Unnamed>, BETCE-PCN-BLANC, BETCE-ENJOLIVEUR PC-BLANC, BETCE-ETIQUETTE RJ-BLEU, BETCE-PCO-ROUGE
Pset_BuildingElementProxyCommon - Reference: 1PCO+1RJ+2HDMI; sets with these values: 2

# IfcBuildingElementProxy: Poste travail encastré 1x3 modules-1RJ+HDMI_USB sur sortie cable:1PCO+1RJ+2USB, Poste travail encastré 1x3 modules-1RJ+HDMI_USB sur sortie cable:1PCO+1RJ+2USB:3713983
In: Niveau 0
Type - Material: <Unnamed>, BETCE-PCN-BLANC, BETCE-ENJOLIVEUR PC-BLANC, BETCE-ETIQUETTE RJ-BLEU, BETCE-PCO-ROUGE
Pset_BuildingElementProxyCommon - Reference: 1PCO+1RJ+2USB; sets with these values: 2

# IfcBuildingElementProxy: Poste travail encastré 1x4 modules-1RJ+1HDMI:1PCN+1PCO+1RJ+1HDMI, Poste travail encastré 1x4 modules-1RJ+1HDMI:1PCN+1PCO+1RJ+1HDMI:4637624
In: Niveau 0
Type - Material: BETCE-ENJOLIVEUR PC-BLANC, BETCE-ETIQUETTE RJ-BLEU, BETCE-HDMI-BLANC, <Unnamed>, BETCE-PCN-BLANC, BETCE-PCO-ROUGE
Pset_BuildingElementProxyCommon - Reference: 1PCN+1PCO+1RJ+1HDMI; sets with these values: 2

# IfcBuildingElementProxy: Poste travail encastré 1x4 modules-1RJ+1HDMI:2PCN+1RJ+1HDMI, Poste travail encastré 1x4 modules-1RJ+1HDMI:2PCN+1RJ+1HDMI:4637788
In: Niveau 0
Type - Material: BETCE-ENJOLIVEUR PC-BLANC, BETCE-ETIQUETTE RJ-BLEU, BETCE-HDMI-BLANC, <Unnamed>, BETCE-PCN-BLANC
Pset_BuildingElementProxyCommon - Reference: 2PCN+1RJ+1HDMI; sets with these values: 2

# IfcBuildingElementProxy: Poste travail encastré 1x4 modules-1RJ+1HDMI:2PCO+1RJ+1HDMI, Poste travail encastré 1x4 modules-1RJ+1HDMI:2PCO+1RJ+1HDMI:4637868
In: Niveau 0
Type - Material: BETCE-ENJOLIVEUR PC-BLANC, BETCE-ETIQUETTE RJ-BLEU, BETCE-HDMI-BLANC, <Unnamed>, BETCE-PCO-ROUGE
Pset_BuildingElementProxyCommon - Reference: 2PCO+1RJ+1HDMI; sets with these values: 2

# IfcBuildingElementProxy: Poste travail encastré 1x4 modules-1RJ+2HDMI:1PCN+1PCO+1RJ+2HDMI, Poste travail encastré 1x4 modules-1RJ+2HDMI:1PCN+1PCO+1RJ+2HDMI:4646416
In: Niveau 0
Type - Material: BETCE-ENJOLIVEUR PC-BLANC, BETCE-ETIQUETTE RJ-BLEU, BETCE-HDMI-BLANC, <Unnamed>, BETCE-PCN-BLANC, BETCE-PCO-ROUGE
Pset_BuildingElementProxyCommon - Reference: 1PCN+1PCO+1RJ+2HDMI; sets with these values: 2

# IfcBuildingElementProxy: Poste travail encastré 1x4 modules-1RJ+2HDMI:2PCN+1RJ+2HDMI, Poste travail encastré 1x4 modules-1RJ+2HDMI:2PCN+1RJ+2HDMI:4646642
In: Niveau 0
Type - Material: BETCE-ENJOLIVEUR PC-BLANC, BETCE-ETIQUETTE RJ-BLEU, BETCE-HDMI-BLANC, <Unnamed>, BETCE-PCN-BLANC
Pset_BuildingElementProxyCommon - Reference: 2PCN+1RJ+2HDMI; sets with these values: 2

# IfcBuildingElementProxy: Poste travail encastré 1x4 modules-1RJ+2HDMI:2PCO+1RJ+2HDMI, Poste travail encastré 1x4 modules-1RJ+2HDMI:2PCO+1RJ+2HDMI:4646722
In: Niveau 0
Type - Material: BETCE-ENJOLIVEUR PC-BLANC, BETCE-ETIQUETTE RJ-BLEU, BETCE-HDMI-BLANC, <Unnamed>, BETCE-PCO-ROUGE
Pset_BuildingElementProxyCommon - Reference: 2PCO+1RJ+2HDMI; sets with these values: 2

# IfcBuildingElementProxy: Poste travail encastré 1x4 modules-1RJ+HDMI_USB sur sortie cable:1PCN+1PCO+1RJ+1HDMI+1USB, Poste travail encastré 1x4 modules-1RJ+HDMI_USB sur sortie cable:1PCN+1PCO+1RJ+1HDMI+1USB:3721877
In: Niveau 0
Type - Material: <Unnamed>, BETCE-PCN-BLANC, BETCE-ENJOLIVEUR PC-BLANC, BETCE-ETIQUETTE RJ-BLEU, BETCE-PCO-ROUGE
Pset_BuildingElementProxyCommon - Reference: 1PCN+1PCO+1RJ+1HDMI+1USB; sets with these values: 2

# IfcBuildingElementProxy: Poste travail encastré 1x4 modules-1RJ+HDMI_USB sur sortie cable:1PCN+1PCO+1RJ+2HDMI, Poste travail encastré 1x4 modules-1RJ+HDMI_USB sur sortie cable:1PCN+1PCO+1RJ+2HDMI:3722263
In: Niveau 0
Type - Material: <Unnamed>, BETCE-PCN-BLANC, BETCE-ENJOLIVEUR PC-BLANC, BETCE-ETIQUETTE RJ-BLEU, BETCE-PCO-ROUGE
Pset_BuildingElementProxyCommon - Reference: 1PCN+1PCO+1RJ+2HDMI; sets with these values: 2

# IfcBuildingElementProxy: Poste travail encastré 1x4 modules-1RJ+HDMI_USB sur sortie cable:1PCN+1PCO+1RJ+2USB, Poste travail encastré 1x4 modules-1RJ+HDMI_USB sur sortie cable:1PCN+1PCO+1RJ+2USB:3722389
In: Niveau 0
Type - Material: <Unnamed>, BETCE-PCN-BLANC, BETCE-ENJOLIVEUR PC-BLANC, BETCE-ETIQUETTE RJ-BLEU, BETCE-PCO-ROUGE
Pset_BuildingElementProxyCommon - Reference: 1PCN+1PCO+1RJ+2USB; sets with these values: 2

# IfcBuildingElementProxy: Poste travail encastré 1x4 modules-1RJ+HDMI_USB sur sortie cable:2PCN+1RJ+1HDMI+1USB, Poste travail encastré 1x4 modules-1RJ+HDMI_USB sur sortie cable:2PCN+1RJ+1HDMI+1USB:3722491
In: Niveau 0
Type - Material: <Unnamed>, BETCE-PCN-BLANC, BETCE-ENJOLIVEUR PC-BLANC, BETCE-ETIQUETTE RJ-BLEU
Pset_BuildingElementProxyCommon - Reference: 2PCN+1RJ+1HDMI+1USB; sets with these values: 2

# IfcBuildingElementProxy: Poste travail encastré 1x4 modules-1RJ+HDMI_USB sur sortie cable:2PCN+1RJ+2HDMI, Poste travail encastré 1x4 modules-1RJ+HDMI_USB sur sortie cable:2PCN+1RJ+2HDMI:3722617
In: Niveau 0
Type - Material: <Unnamed>, BETCE-PCN-BLANC, BETCE-ENJOLIVEUR PC-BLANC, BETCE-ETIQUETTE RJ-BLEU
Pset_BuildingElementProxyCommon - Reference: 2PCN+1RJ+2HDMI; sets with these values: 2

# IfcBuildingElementProxy: Poste travail encastré 1x4 modules-1RJ+HDMI_USB sur sortie cable:2PCN+1RJ+2USB, Poste travail encastré 1x4 modules-1RJ+HDMI_USB sur sortie cable:2PCN+1RJ+2USB:3722703
In: Niveau 0
Type - Material: <Unnamed>, BETCE-PCN-BLANC, BETCE-ENJOLIVEUR PC-BLANC, BETCE-ETIQUETTE RJ-BLEU
Pset_BuildingElementProxyCommon - Reference: 2PCN+1RJ+2USB; sets with these values: 2

# IfcBuildingElementProxy: Poste travail encastré 1x4 modules-1RJ+HDMI_USB sur sortie cable:2PCO+1RJ+1HDMI+1USB, Poste travail encastré 1x4 modules-1RJ+HDMI_USB sur sortie cable:2PCO+1RJ+1HDMI+1USB:3722799
In: Niveau 0
Type - Material: <Unnamed>, BETCE-PCN-BLANC, BETCE-ENJOLIVEUR PC-BLANC, BETCE-ETIQUETTE RJ-BLEU, BETCE-PCO-ROUGE
Pset_BuildingElementProxyCommon - Reference: 2PCO+1RJ+1HDMI+1USB; sets with these values: 2

# IfcBuildingElementProxy: Poste travail encastré 1x4 modules-1RJ+HDMI_USB sur sortie cable:2PCO+1RJ+2HDMI, Poste travail encastré 1x4 modules-1RJ+HDMI_USB sur sortie cable:2PCO+1RJ+2HDMI:3722949
In: Niveau 0
Type - Material: <Unnamed>, BETCE-PCN-BLANC, BETCE-ENJOLIVEUR PC-BLANC, BETCE-ETIQUETTE RJ-BLEU, BETCE-PCO-ROUGE
Pset_BuildingElementProxyCommon - Reference: 2PCO+1RJ+2HDMI; sets with these values: 2

# IfcBuildingElementProxy: Poste travail encastré 1x4 modules-1RJ+HDMI_USB sur sortie cable:2PCO+1RJ+2USB, Poste travail encastré 1x4 modules-1RJ+HDMI_USB sur sortie cable:2PCO+1RJ+2USB:3723111
In: Niveau 0
Type - Material: <Unnamed>, BETCE-PCN-BLANC, BETCE-ENJOLIVEUR PC-BLANC, BETCE-ETIQUETTE RJ-BLEU, BETCE-PCO-ROUGE
Pset_BuildingElementProxyCommon - Reference: 2PCO+1RJ+2USB; sets with these values: 2

# IfcBuildingElementProxy: Poste travail encastré 2x2 modules-2RJ:1PCN+1PCO+2RJ, Poste travail encastré 2x2 modules-2RJ:1PCN+1PCO+2RJ:3680745
In: Niveau 0
Type - Material: BETCE-ENJOLIVEUR RJ-BLANC, BETCE-ETIQUETTE RJ-BLEU, BETCE-PCN-BLANC, <Unnamed>, BETCE-ENJOLIVEUR PC-BLANC, BETCE-PCO-ROUGE
Pset_BuildingElementProxyCommon - Reference: 1PCN+1PCO+2RJ; sets with these values: 2

# IfcBuildingElementProxy: Poste travail encastré 2x2 modules-2RJ:2PCN+2RJ, Poste travail encastré 2x2 modules-2RJ:2PCN+2RJ:3680845
In: Niveau 0
Type - Material: BETCE-ENJOLIVEUR RJ-BLANC, BETCE-ETIQUETTE RJ-BLEU, BETCE-PCN-BLANC, <Unnamed>, BETCE-ENJOLIVEUR PC-BLANC
Pset_BuildingElementProxyCommon - Reference: 2PCN+2RJ; sets with these values: 2

# IfcBuildingElementProxy: Poste travail encastré 2x2 modules-2RJ:2PCO+2RJ, Poste travail encastré 2x2 modules-2RJ:2PCO+2RJ:3680963
In: Niveau 0
Type - Material: BETCE-ENJOLIVEUR RJ-BLANC, BETCE-ETIQUETTE RJ-BLEU, BETCE-PCO-ROUGE, <Unnamed>, BETCE-ENJOLIVEUR PC-BLANC
Pset_BuildingElementProxyCommon - Reference: 2PCO+2RJ; sets with these values: 2

# IfcBuildingElementProxy: Poste travail encastré 2x3 modules-2RJ+1HDMI_1USB sur sortie cable:2PCN+1PCO+2RJ+2HDMI, Poste travail encastré 2x3 modules-2RJ+1HDMI_1USB sur sortie cable:2PCN+1PCO+2RJ+2HDMI:3731462
In: Niveau 0
Type - Material: <Unnamed>, A-PVC BLANC, A-ETIQUETTE RJ, A-ENJOLIVEUR BLANC
Pset_BuildingElementProxyCommon - Reference: 2PCN+1PCO+2RJ+2HDMI; sets with these values: 2

# IfcBuildingElementProxy: Poste travail encastré 2x3 modules-2RJ+1HDMI_1USB sur sortie cable:2PCN+1PCO+2RJ+2USB, Poste travail encastré 2x3 modules-2RJ+1HDMI_1USB sur sortie cable:2PCN+1PCO+2RJ+2USB:3731564
In: Niveau 0
Type - Material: <Unnamed>, A-PVC BLANC, A-ETIQUETTE RJ, A-ENJOLIVEUR BLANC
Pset_BuildingElementProxyCommon - Reference: 2PCN+1PCO+2RJ+2USB; sets with these values: 2

# IfcBuildingElementProxy: Poste travail encastré 2x3 modules-2RJ+1HDMI_1USB sur sortie cable:3PCN+2RJ+1HDMI+1USB, Poste travail encastré 2x3 modules-2RJ+1HDMI_1USB sur sortie cable:3PCN+2RJ+1HDMI+1USB:3731682
In: Niveau 0
Type - Material: <Unnamed>, A-PVC BLANC, A-ETIQUETTE RJ, A-ENJOLIVEUR BLANC
Pset_BuildingElementProxyCommon - Reference: 3PCN+2RJ+1HDMI+1USB; sets with these values: 2

# IfcBuildingElementProxy: Poste travail encastré 2x3 modules-2RJ+1HDMI_1USB sur sortie cable:3PCN+2RJ+2HDMI, Poste travail encastré 2x3 modules-2RJ+1HDMI_1USB sur sortie cable:3PCN+2RJ+2HDMI:3731790
In: Niveau 0
Type - Material: <Unnamed>, A-PVC BLANC, A-ETIQUETTE RJ, A-ENJOLIVEUR BLANC
Pset_BuildingElementProxyCommon - Reference: 3PCN+2RJ+2HDMI; sets with these values: 2

# IfcBuildingElementProxy: Poste travail encastré 2x3 modules-2RJ+1HDMI_1USB sur sortie cable:3PCN+2RJ+2USB, Poste travail encastré 2x3 modules-2RJ+1HDMI_1USB sur sortie cable:3PCN+2RJ+2USB:3731898
In: Niveau 0
Type - Material: <Unnamed>, A-PVC BLANC, A-ETIQUETTE RJ, A-ENJOLIVEUR BLANC
Pset_BuildingElementProxyCommon - Reference: 3PCN+2RJ+2USB; sets with these values: 2

# IfcBuildingElementProxy: Poste travail encastré 2x3 modules-2RJ+1HDMI_1USB sur sortie cable:3PCO+2RJ+1HDMI+1USB, Poste travail encastré 2x3 modules-2RJ+1HDMI_1USB sur sortie cable:3PCO+2RJ+1HDMI+1USB:3732062
In: Niveau 0
Type - Material: <Unnamed>, A-PVC BLANC, A-ETIQUETTE RJ, A-ENJOLIVEUR BLANC
Pset_BuildingElementProxyCommon - Reference: 3PCO+2RJ+1HDMI+1USB; sets with these values: 2

# IfcBuildingElementProxy: Poste travail encastré 2x3 modules-2RJ+1HDMI_1USB sur sortie cable:3PCO+2RJ+2HDMI, Poste travail encastré 2x3 modules-2RJ+1HDMI_1USB sur sortie cable:3PCO+2RJ+2HDMI:3732238
In: Niveau 0
Type - Material: <Unnamed>, A-PVC BLANC, A-ETIQUETTE RJ, A-ENJOLIVEUR BLANC
Pset_BuildingElementProxyCommon - Reference: 3PCO+2RJ+2HDMI; sets with these values: 2

# IfcBuildingElementProxy: Poste travail encastré 2x3 modules-2RJ+1HDMI_1USB sur sortie cable:3PCO+2RJ+2USB, Poste travail encastré 2x3 modules-2RJ+1HDMI_1USB sur sortie cable:3PCO+2RJ+2USB:3732346
In: Niveau 0
Type - Material: <Unnamed>, A-PVC BLANC, A-ETIQUETTE RJ, A-ENJOLIVEUR BLANC
Pset_BuildingElementProxyCommon - Reference: 3PCO+2RJ+2USB; sets with these values: 2

# IfcBuildingElementProxy: Poste travail encastré 2x3 modules-2RJ+HDMI_USB sur sortie cable:1PCN+2PCO+2RJ+1HDMI+1USB (2)
In: Niveau 0
Type - Material: <Unnamed>, BETCE-SORTIE CABLE-BLANC, BETCE-ETIQUETTE RJ-BLEU, BETCE-PCO-ROUGE, BETCE-PCN-BLANC, BETCE-ENJOLIVEUR PC-BLANC
Pset_BuildingElementProxyCommon - Reference: 1PCN+2PCO+2RJ+1HDMI+1USB; sets with these values: 2
Name (Poste travail encastré 2x3 modules-2RJ+HDMI_USB sur sortie cable:1PCN+2PCO+2RJ+1HDMI+1USB:...)
3730585
5476180

# IfcBuildingElementProxy: Poste travail encastré 2x3 modules-2RJ+HDMI_USB sur sortie cable:1PCN+2PCO+2RJ+2HDMI, Poste travail encastré 2x3 modules-2RJ+HDMI_USB sur sortie cable:1PCN+2PCO+2RJ+2HDMI:3731126
In: Niveau 0
Type - Material: <Unnamed>, BETCE-SORTIE CABLE-BLANC, BETCE-ETIQUETTE RJ-BLEU, BETCE-PCO-ROUGE, BETCE-PCN-BLANC, BETCE-ENJOLIVEUR PC-BLANC
Pset_BuildingElementProxyCommon - Reference: 1PCN+2PCO+2RJ+2HDMI; sets with these values: 2

# IfcBuildingElementProxy: Poste travail encastré 2x3 modules-2RJ+HDMI_USB sur sortie cable:1PCN+2PCO+2RJ+2USB, Poste travail encastré 2x3 modules-2RJ+HDMI_USB sur sortie cable:1PCN+2PCO+2RJ+2USB:3731238
In: Niveau 0
Type - Material: <Unnamed>, BETCE-SORTIE CABLE-BLANC, BETCE-ETIQUETTE RJ-BLEU, BETCE-PCO-ROUGE, BETCE-PCN-BLANC, BETCE-ENJOLIVEUR PC-BLANC
Pset_BuildingElementProxyCommon - Reference: 1PCN+2PCO+2RJ+2USB; sets with these values: 2

# IfcBuildingElementProxy: Poste travail encastré 2x3 modules-2RJ+HDMI_USB sur sortie cable:2PCN+1PCO+2RJ+1HDMI+1USB, Poste travail encastré 2x3 modules-2RJ+HDMI_USB sur sortie cable:2PCN+1PCO+2RJ+1HDMI+1USB:3731320
In: Niveau 0
Type - Material: <Unnamed>, BETCE-SORTIE CABLE-BLANC, BETCE-ETIQUETTE RJ-BLEU, BETCE-PCO-ROUGE, BETCE-PCN-BLANC, BETCE-ENJOLIVEUR PC-BLANC
Pset_BuildingElementProxyCommon - Reference: 2PCN+1PCO+2RJ+1HDMI+1USB; sets with these values: 2

# IfcBuildingElementProxy: Poste travail encastré 2x3 modules-2RJ:2PCN+2PCO+2RJ, Poste travail encastré 2x3 modules-2RJ:2PCN+2PCO+2RJ:3656159
In: Niveau 0
Type - Material: BETCE-ENJOLIVEUR RJ-BLANC, BETCE-ETIQUETTE RJ-BLEU, BETCE-PCO-ROUGE, <Unnamed>, BETCE-PCN-BLANC, BETCE-ENJOLIVEUR PC-BLANC
Pset_BuildingElementProxyCommon - Reference: 2PCN+2PCO+2RJ; sets with these values: 2

# IfcBuildingElementProxy: Poste travail encastré 2x3 modules-2RJ:4PCN+2RJ, Poste travail encastré 2x3 modules-2RJ:4PCN+2RJ:3656253
In: Niveau 0
Type - Material: BETCE-ENJOLIVEUR RJ-BLANC, BETCE-ETIQUETTE RJ-BLEU, BETCE-PCN-BLANC, <Unnamed>, BETCE-ENJOLIVEUR PC-BLANC
Pset_BuildingElementProxyCommon - Reference: 4PCN+2RJ; sets with these values: 2

# IfcBuildingElementProxy: Poste travail encastré 2x3 modules-2RJ:4PCO+2RJ, Poste travail encastré 2x3 modules-2RJ:4PCO+2RJ:3656383
In: Niveau 0
Type - Material: BETCE-ENJOLIVEUR RJ-BLANC, BETCE-ETIQUETTE RJ-BLEU, BETCE-PCO-ROUGE, <Unnamed>, BETCE-ENJOLIVEUR PC-BLANC
Pset_BuildingElementProxyCommon - Reference: 4PCO+2RJ; sets with these values: 2

# IfcBuildingElementProxy: Poste travail encastré 2x3 modules-3RJ:1PCN+2PCO+3RJ, Poste travail encastré 2x3 modules-3RJ:1PCN+2PCO+3RJ:3685381
In: Niveau 0
Type - Material: BETCE-ENJOLIVEUR RJ-BLANC, BETCE-ETIQUETTE RJ-BLEU, BETCE-PCO-ROUGE, <Unnamed>, BETCE-PCN-BLANC, BETCE-ENJOLIVEUR PC-BLANC
Pset_BuildingElementProxyCommon - Reference: 1PCN+2PCO+3RJ; sets with these values: 2

# IfcBuildingElementProxy: Poste travail encastré 2x3 modules-3RJ:2PCN+1PCO+3RJ, Poste travail encastré 2x3 modules-3RJ:2PCN+1PCO+3RJ:3690249
In: Niveau 0
Type - Material: BETCE-ENJOLIVEUR RJ-BLANC, BETCE-ETIQUETTE RJ-BLEU, BETCE-PCO-ROUGE, <Unnamed>, BETCE-PCN-BLANC, BETCE-ENJOLIVEUR PC-BLANC
Pset_BuildingElementProxyCommon - Reference: 2PCN+1PCO+3RJ; sets with these values: 2

# IfcBuildingElementProxy: Poste travail encastré 2x3 modules-3RJ:3PCN+3RJ, Poste travail encastré 2x3 modules-3RJ:3PCN+3RJ:3690371
In: Niveau 0
Type - Material: BETCE-ENJOLIVEUR RJ-BLANC, BETCE-ETIQUETTE RJ-BLEU, BETCE-PCN-BLANC, <Unnamed>, BETCE-ENJOLIVEUR PC-BLANC
Pset_BuildingElementProxyCommon - Reference: 3PCN+3RJ; sets with these values: 2

# IfcBuildingElementProxy: Poste travail encastré 2x3 modules-3RJ:3PCO+3RJ, Poste travail encastré 2x3 modules-3RJ:3PCO+3RJ:3690519
In: Niveau 0
Type - Material: BETCE-ENJOLIVEUR RJ-BLANC, BETCE-ETIQUETTE RJ-BLEU, BETCE-PCO-ROUGE, <Unnamed>, BETCE-ENJOLIVEUR PC-BLANC
Pset_BuildingElementProxyCommon - Reference: 3PCO+3RJ; sets with these values: 2

# IfcBuildingElementProxy: Poste travail encastré 2x4 modules-2RJ:2PCN+4PCO+2RJ, Poste travail encastré 2x4 modules-2RJ:2PCN+4PCO+2RJ:3673031
In: Niveau 0
Type - Material: <Unnamed>, BETCE-PCO-ROUGE, BETCE-ENJOLIVEUR RJ-BLANC, BETCE-ETIQUETTE RJ-BLEU, BETCE-PCN-BLANC, BETCE-ENJOLIVEUR PC-BLANC
Pset_BuildingElementProxyCommon - Reference: 2PCN+4PCO+2RJ; sets with these values: 2

# IfcBuildingElementProxy: Poste travail encastré 2x4 modules-2RJ:3PCN+3PCO+2RJ, Poste travail encastré 2x4 modules-2RJ:3PCN+3PCO+2RJ:3673153
In: Niveau 0
Type - Material: <Unnamed>, BETCE-PCN-BLANC, BETCE-PCO-ROUGE, BETCE-ENJOLIVEUR RJ-BLANC, BETCE-ETIQUETTE RJ-BLEU, BETCE-ENJOLIVEUR PC-BLANC
Pset_BuildingElementProxyCommon - Reference: 3PCN+3PCO+2RJ; sets with these values: 2

# IfcBuildingElementProxy: Poste travail encastré 2x4 modules-2RJ:4PCN+2PCO+2RJ, Poste travail encastré 2x4 modules-2RJ:4PCN+2PCO+2RJ:3673241
In: Niveau 0
Type - Material: <Unnamed>, BETCE-PCO-ROUGE, BETCE-ENJOLIVEUR RJ-BLANC, BETCE-ETIQUETTE RJ-BLEU, BETCE-PCN-BLANC, BETCE-ENJOLIVEUR PC-BLANC
Pset_BuildingElementProxyCommon - Reference: 4PCN+2PCO+2RJ; sets with these values: 2

# IfcBuildingElementProxy: Poste travail encastré 2x4 modules-2RJ:6PCN+2RJ, Poste travail encastré 2x4 modules-2RJ:6PCN+2RJ:3673353
In: Niveau 0
Type - Material: <Unnamed>, BETCE-PCN-BLANC, BETCE-ENJOLIVEUR RJ-BLANC, BETCE-ETIQUETTE RJ-BLEU, BETCE-ENJOLIVEUR PC-BLANC
Pset_BuildingElementProxyCommon - Reference: 6PCN+2RJ; sets with these values: 2

# IfcBuildingElementProxy: Poste travail encastré 2x4 modules-2RJ:6PCO+2RJ, Poste travail encastré 2x4 modules-2RJ:6PCO+2RJ:3673449
In: Niveau 0
Type - Material: <Unnamed>, BETCE-PCO-ROUGE, BETCE-ENJOLIVEUR RJ-BLANC, BETCE-ETIQUETTE RJ-BLEU, BETCE-ENJOLIVEUR PC-BLANC
Pset_BuildingElementProxyCommon - Reference: 6PCO+2RJ; sets with these values: 2

# IfcBuildingElementProxy: Poste travail encastré 2x5 modules-2RJ:2PCN+6PCO+2RJ, Poste travail encastré 2x5 modules-2RJ:2PCN+6PCO+2RJ:3632311
In: Niveau 0
Type - Material: BETCE-PCO-ROUGE, BETCE-ENJOLIVEUR RJ-BLANC, BETCE-ETIQUETTE RJ-BLEU, BETCE-PCN-BLANC, <Unnamed>, BETCE-ENJOLIVEUR PCN-BLANC
Pset_BuildingElementProxyCommon - Reference: 2PCN+6PCO+2RJ; sets with these values: 2

# IfcBuildingElementProxy: Poste travail encastré 2x5 modules-2RJ:4PCN+4PCO+2RJ, Poste travail encastré 2x5 modules-2RJ:4PCN+4PCO+2RJ:3632639
In: Niveau 0
Type - Material: BETCE-PCO-ROUGE, BETCE-PCN-BLANC, BETCE-ENJOLIVEUR RJ-BLANC, BETCE-ETIQUETTE RJ-BLEU, <Unnamed>, BETCE-ENJOLIVEUR PCN-BLANC
Pset_BuildingElementProxyCommon - Reference: 4PCN+4PCO+2RJ; sets with these values: 2

# IfcBuildingElementProxy: Poste travail encastré 2x5 modules-2RJ:6PCN+2PCO+2RJ, Poste travail encastré 2x5 modules-2RJ:6PCN+2PCO+2RJ:3632827
In: Niveau 0
Type - Material: BETCE-PCO-ROUGE, BETCE-PCN-BLANC, BETCE-ENJOLIVEUR RJ-BLANC, BETCE-ETIQUETTE RJ-BLEU, <Unnamed>, BETCE-ENJOLIVEUR PCN-BLANC
Pset_BuildingElementProxyCommon - Reference: 6PCN+2PCO+2RJ; sets with these values: 2

# IfcBuildingElementProxy: Poste travail encastré 2x5 modules-2RJ:8PCN+2RJ, Poste travail encastré 2x5 modules-2RJ:8PCN+2RJ:3633167
In: Niveau 0
Type - Material: BETCE-PCN-BLANC, BETCE-ENJOLIVEUR RJ-BLANC, BETCE-ETIQUETTE RJ-BLEU, <Unnamed>, BETCE-ENJOLIVEUR PCN-BLANC
Pset_BuildingElementProxyCommon - Reference: 8PCN+2RJ; sets with these values: 2

# IfcBuildingElementProxy: Poste travail encastré 2x5 modules-2RJ:8PCO+2RJ, Poste travail encastré 2x5 modules-2RJ:8PCO+2RJ:3633327
In: Niveau 0
Type - Material: BETCE-PCO-ROUGE, BETCE-ENJOLIVEUR RJ-BLANC, BETCE-ETIQUETTE RJ-BLEU, <Unnamed>, BETCE-ENJOLIVEUR PCN-BLANC
Pset_BuildingElementProxyCommon - Reference: 8PCO+2RJ; sets with these values: 2

# IfcBuildingElementProxy: Poste travail saillie 1x2 modules-1RJ:1PCN+1RJ, Poste travail saillie 1x2 modules-1RJ:1PCN+1RJ:4477159
In: Niveau 0
Type - Material: BETCE-ENJOLIVEUR PC-BLANC, BETCE-ENJOLIVEUR RJ-BLANC, BETCE-PCN-BLANC, BETCE-ETIQUETTE RJ-BLEU, <Unnamed>
Pset_BuildingElementProxyCommon - Reference: 1PCN+1RJ; sets with these values: 2

# IfcBuildingElementProxy: Poste travail saillie 1x2 modules-1RJ:1PCO+1RJ, Poste travail saillie 1x2 modules-1RJ:1PCO+1RJ:4477219
In: Niveau 0
Type - Material: BETCE-ENJOLIVEUR PC-BLANC, BETCE-ENJOLIVEUR RJ-BLANC, BETCE-PCO-ROUGE, BETCE-ETIQUETTE RJ-BLEU, <Unnamed>
Pset_BuildingElementProxyCommon - Reference: 1PCO+1RJ; sets with these values: 2

# IfcBuildingElementProxy: Poste travail saillie 1x2 modules-HDMI_USB sur sortie cable:1PCN+1HDMI+1USB, Poste travail saillie 1x2 modules-HDMI_USB sur sortie cable:1PCN+1HDMI+1USB:4488466
In: Niveau 0
Type - Material: BETCE-ENJOLIVEUR PC-BLANC, <Unnamed>, BETCE-SORTIE CABLE-BLANC, BETCE-PCN-BLANC
Pset_BuildingElementProxyCommon - Reference: 1PCN+1HDMI+1USB; sets with these values: 2

# IfcBuildingElementProxy: Poste travail saillie 1x2 modules-HDMI_USB sur sortie cable:1PCN+2HDMI, Poste travail saillie 1x2 modules-HDMI_USB sur sortie cable:1PCN+2HDMI:4488660
In: Niveau 0
Type - Material: BETCE-ENJOLIVEUR PC-BLANC, <Unnamed>, BETCE-SORTIE CABLE-BLANC, BETCE-PCN-BLANC
Pset_BuildingElementProxyCommon - Reference: 1PCN+2HDMI; sets with these values: 2

# IfcBuildingElementProxy: Poste travail saillie 1x2 modules-HDMI_USB sur sortie cable:1PCN+2USB, Poste travail saillie 1x2 modules-HDMI_USB sur sortie cable:1PCN+2USB:4488764
In: Niveau 0
Type - Material: BETCE-ENJOLIVEUR PC-BLANC, <Unnamed>, BETCE-SORTIE CABLE-BLANC, BETCE-PCN-BLANC
Pset_BuildingElementProxyCommon - Reference: 1PCN+2USB; sets with these values: 2

# IfcBuildingElementProxy: Poste travail saillie 1x2 modules-HDMI_USB sur sortie cable:1PCO+1HDMI+1USB, Poste travail saillie 1x2 modules-HDMI_USB sur sortie cable:1PCO+1HDMI+1USB:4488874
In: Niveau 0
Type - Material: BETCE-ENJOLIVEUR PC-BLANC, <Unnamed>, BETCE-SORTIE CABLE-BLANC, BETCE-PCO-ROUGE
Pset_BuildingElementProxyCommon - Reference: 1PCO+1HDMI+1USB; sets with these values: 2

# IfcBuildingElementProxy: Poste travail saillie 1x2 modules-HDMI_USB sur sortie cable:1PCO+2HDMI, Poste travail saillie 1x2 modules-HDMI_USB sur sortie cable:1PCO+2HDMI:4488932
In: Niveau 0
Type - Material: BETCE-ENJOLIVEUR PC-BLANC, <Unnamed>, BETCE-SORTIE CABLE-BLANC, BETCE-PCO-ROUGE
Pset_BuildingElementProxyCommon - Reference: 1PCO+2HDMI; sets with these values: 2

# IfcBuildingElementProxy: Poste travail saillie 1x2 modules-HDMI_USB sur sortie cable:1PCO+2USB, Poste travail saillie 1x2 modules-HDMI_USB sur sortie cable:1PCO+2USB:4489018
In: Niveau 0
Type - Material: BETCE-ENJOLIVEUR PC-BLANC, <Unnamed>, BETCE-SORTIE CABLE-BLANC, BETCE-PCO-ROUGE
Pset_BuildingElementProxyCommon - Reference: 1PCO+2USB; sets with these values: 2

# IfcBuildingElementProxy: Poste travail saillie 1x3 modules-1RJ+HDMI_USB sur sortie cable:1PCN+1RJ+1HDMI+1USB, Poste travail saillie 1x3 modules-1RJ+HDMI_USB sur sortie cable:1PCN+1RJ+1HDMI+1USB:5664248
In: Niveau 0
Type - Material: <Unnamed>, BETCE-PCN-BLANC, BETCE-ENJOLIVEUR PC-BLANC, BETCE-ETIQUETTE RJ-BLEU
Pset_BuildingElementProxyCommon - Reference: 1PCN+1RJ+1HDMI+1USB; sets with these values: 2

# IfcBuildingElementProxy: Poste travail saillie 1x3 modules-1RJ+HDMI_USB sur sortie cable:1PCN+1RJ+2HDMI, Poste travail saillie 1x3 modules-1RJ+HDMI_USB sur sortie cable:1PCN+1RJ+2HDMI:5676465
In: Niveau 0
Type - Material: <Unnamed>, BETCE-PCN-BLANC, BETCE-ENJOLIVEUR PC-BLANC, BETCE-ETIQUETTE RJ-BLEU
Pset_BuildingElementProxyCommon - Reference: 1PCN+1RJ+2HDMI; sets with these values: 2

# IfcBuildingElementProxy: Poste travail saillie 1x3 modules-1RJ+HDMI_USB sur sortie cable:1PCN+1RJ+2USB, Poste travail saillie 1x3 modules-1RJ+HDMI_USB sur sortie cable:1PCN+1RJ+2USB:5676513
In: Niveau 0
Type - Material: <Unnamed>, BETCE-PCN-BLANC, BETCE-ENJOLIVEUR PC-BLANC, BETCE-ETIQUETTE RJ-BLEU
Pset_BuildingElementProxyCommon - Reference: 1PCN+1RJ+2USB; sets with these values: 2

# IfcBuildingElementProxy: Poste travail saillie 1x3 modules-1RJ+HDMI_USB sur sortie cable:1PCO+1RJ+1HDMI+1USB, Poste travail saillie 1x3 modules-1RJ+HDMI_USB sur sortie cable:1PCO+1RJ+1HDMI+1USB:5676583
In: Niveau 0
Type - Material: <Unnamed>, BETCE-PCN-BLANC, BETCE-ENJOLIVEUR PC-BLANC, BETCE-ETIQUETTE RJ-BLEU, BETCE-PCO-ROUGE
Pset_BuildingElementProxyCommon - Reference: 1PCO+1RJ+1HDMI+1USB; sets with these values: 2

# IfcBuildingElementProxy: Poste travail saillie 1x3 modules-1RJ+HDMI_USB sur sortie cable:1PCO+1RJ+2HDMI, Poste travail saillie 1x3 modules-1RJ+HDMI_USB sur sortie cable:1PCO+1RJ+2HDMI:5676653
In: Niveau 0
Type - Material: <Unnamed>, BETCE-PCN-BLANC, BETCE-ENJOLIVEUR PC-BLANC, BETCE-ETIQUETTE RJ-BLEU, BETCE-PCO-ROUGE
Pset_BuildingElementProxyCommon - Reference: 1PCO+1RJ+2HDMI; sets with these values: 2

# IfcBuildingElementProxy: Poste travail saillie 1x3 modules-1RJ+HDMI_USB sur sortie cable:1PCO+1RJ+2USB, Poste travail saillie 1x3 modules-1RJ+HDMI_USB sur sortie cable:1PCO+1RJ+2USB:5676711
In: Niveau 0
Type - Material: <Unnamed>, BETCE-PCN-BLANC, BETCE-ENJOLIVEUR PC-BLANC, BETCE-ETIQUETTE RJ-BLEU, BETCE-PCO-ROUGE
Pset_BuildingElementProxyCommon - Reference: 1PCO+1RJ+2USB; sets with these values: 2

# IfcBuildingElementProxy: Poste travail saillie 1x4 modules-1RJ+HDMI_USB sur sortie cable:1PCN+1PCO+1RJ+1HDMI+1USB, Poste travail saillie 1x4 modules-1RJ+HDMI_USB sur sortie cable:1PCN+1PCO+1RJ+1HDMI+1USB:4527114
In: Niveau 0
Type - Material: BETCE-ENJOLIVEUR PC-BLANC, <Unnamed>, BETCE-PCN-BLANC, BETCE-ETIQUETTE RJ-BLEU, BETCE-PCO-ROUGE
Pset_BuildingElementProxyCommon - Reference: 1PCN+1PCO+1RJ+1HDMI+1USB; sets with these values: 2

# IfcBuildingElementProxy: Poste travail saillie 1x4 modules-1RJ+HDMI_USB sur sortie cable:1PCN+1PCO+1RJ+2HDMI, Poste travail saillie 1x4 modules-1RJ+HDMI_USB sur sortie cable:1PCN+1PCO+1RJ+2HDMI:4537468
In: Niveau 0
Type - Material: BETCE-ENJOLIVEUR PC-BLANC, <Unnamed>, BETCE-PCN-BLANC, BETCE-ETIQUETTE RJ-BLEU, BETCE-PCO-ROUGE
Pset_BuildingElementProxyCommon - Reference: 1PCN+1PCO+1RJ+2HDMI; sets with these values: 2

# IfcBuildingElementProxy: Poste travail saillie 1x4 modules-1RJ+HDMI_USB sur sortie cable:1PCN+1PCO+1RJ+2USB, Poste travail saillie 1x4 modules-1RJ+HDMI_USB sur sortie cable:1PCN+1PCO+1RJ+2USB:4537518
In: Niveau 0
Type - Material: BETCE-ENJOLIVEUR PC-BLANC, <Unnamed>, BETCE-PCN-BLANC, BETCE-ETIQUETTE RJ-BLEU, BETCE-PCO-ROUGE
Pset_BuildingElementProxyCommon - Reference: 1PCN+1PCO+1RJ+2USB; sets with these values: 2

# IfcBuildingElementProxy: Poste travail saillie 1x4 modules-1RJ+HDMI_USB sur sortie cable:2PCN+1RJ+1HDMI+1USB, Poste travail saillie 1x4 modules-1RJ+HDMI_USB sur sortie cable:2PCN+1RJ+1HDMI+1USB:4537566
In: Niveau 0
Type - Material: BETCE-ENJOLIVEUR PC-BLANC, <Unnamed>, BETCE-PCN-BLANC, BETCE-ETIQUETTE RJ-BLEU
Pset_BuildingElementProxyCommon - Reference: 2PCN+1RJ+1HDMI+1USB; sets with these values: 2

# IfcBuildingElementProxy: Poste travail saillie 1x4 modules-1RJ+HDMI_USB sur sortie cable:2PCN+1RJ+2HDMI, Poste travail saillie 1x4 modules-1RJ+HDMI_USB sur sortie cable:2PCN+1RJ+2HDMI:4537632
In: Niveau 0
Type - Material: BETCE-ENJOLIVEUR PC-BLANC, <Unnamed>, BETCE-PCN-BLANC, BETCE-ETIQUETTE RJ-BLEU
Pset_BuildingElementProxyCommon - Reference: 2PCN+1RJ+2HDMI; sets with these values: 2

# IfcBuildingElementProxy: Poste travail saillie 1x4 modules-1RJ+HDMI_USB sur sortie cable:2PCN+1RJ+2USB, Poste travail saillie 1x4 modules-1RJ+HDMI_USB sur sortie cable:2PCN+1RJ+2USB:4537684
In: Niveau 0
Type - Material: BETCE-ENJOLIVEUR PC-BLANC, <Unnamed>, BETCE-PCN-BLANC, BETCE-ETIQUETTE RJ-BLEU
Pset_BuildingElementProxyCommon - Reference: 2PCN+1RJ+2USB; sets with these values: 2

# IfcBuildingElementProxy: Poste travail saillie 1x4 modules-1RJ+HDMI_USB sur sortie cable:2PCO+1RJ+1HDMI+1USB, Poste travail saillie 1x4 modules-1RJ+HDMI_USB sur sortie cable:2PCO+1RJ+1HDMI+1USB:4537720
In: Niveau 0
Type - Material: BETCE-ENJOLIVEUR PC-BLANC, <Unnamed>, BETCE-PCN-BLANC, BETCE-ETIQUETTE RJ-BLEU, BETCE-PCO-ROUGE
Pset_BuildingElementProxyCommon - Reference: 2PCO+1RJ+1HDMI+1USB; sets with these values: 2

# IfcBuildingElementProxy: Poste travail saillie 1x4 modules-1RJ+HDMI_USB sur sortie cable:2PCO+1RJ+2HDMI, Poste travail saillie 1x4 modules-1RJ+HDMI_USB sur sortie cable:2PCO+1RJ+2HDMI:4537782
In: Niveau 0
Type - Material: BETCE-ENJOLIVEUR PC-BLANC, <Unnamed>, BETCE-PCN-BLANC, BETCE-ETIQUETTE RJ-BLEU, BETCE-PCO-ROUGE
Pset_BuildingElementProxyCommon - Reference: 2PCO+1RJ+2HDMI; sets with these values: 2

# IfcBuildingElementProxy: Poste travail saillie 1x4 modules-1RJ+HDMI_USB sur sortie cable:2PCO+1RJ+2USB, Poste travail saillie 1x4 modules-1RJ+HDMI_USB sur sortie cable:2PCO+1RJ+2USB:4537844
In: Niveau 0
Type - Material: BETCE-ENJOLIVEUR PC-BLANC, <Unnamed>, BETCE-PCN-BLANC, BETCE-ETIQUETTE RJ-BLEU, BETCE-PCO-ROUGE
Pset_BuildingElementProxyCommon - Reference: 2PCO+1RJ+2USB; sets with these values: 2

# IfcBuildingElementProxy: Poste travail saillie 2x2 modules-2RJ:1PCN+1PCO+2RJ, Poste travail saillie 2x2 modules-2RJ:1PCN+1PCO+2RJ:4461397
In: Niveau 0
Type - Material: BETCE-ENJOLIVEUR PC-BLANC, BETCE-ENJOLIVEUR RJ-BLANC, BETCE-PCN-BLANC, BETCE-PCO-ROUGE, BETCE-ETIQUETTE RJ-BLEU, <Unnamed>
Pset_BuildingElementProxyCommon - Reference: 1PCN+1PCO+2RJ; sets with these values: 2

# IfcBuildingElementProxy: Poste travail saillie 2x2 modules-2RJ:2PCN+2RJ, Poste travail saillie 2x2 modules-2RJ:2PCN+2RJ:4461497
In: Niveau 0
Type - Material: BETCE-ENJOLIVEUR PC-BLANC, BETCE-ENJOLIVEUR RJ-BLANC, BETCE-PCN-BLANC, BETCE-ETIQUETTE RJ-BLEU, <Unnamed>
Pset_BuildingElementProxyCommon - Reference: 2PCN+2RJ; sets with these values: 2

# IfcBuildingElementProxy: Poste travail saillie 2x2 modules-2RJ:2PCO+2RJ, Poste travail saillie 2x2 modules-2RJ:2PCO+2RJ:4461595
In: Niveau 0
Type - Material: BETCE-ENJOLIVEUR PC-BLANC, BETCE-ENJOLIVEUR RJ-BLANC, BETCE-PCO-ROUGE, BETCE-ETIQUETTE RJ-BLEU, <Unnamed>
Pset_BuildingElementProxyCommon - Reference: 2PCO+2RJ; sets with these values: 2

# IfcBuildingElementProxy: Poste travail saillie 2x3 modules-2RJ+HDMI_USB sur sortie cable:1PCN+2PCO+2RJ+1HDMI+1USB, Poste travail saillie 2x3 modules-2RJ+HDMI_USB sur sortie cable:1PCN+2PCO+2RJ+1HDMI+1USB:4582846
In: Niveau 0
Type - Material: <Unnamed>, BETCE-ENJOLIVEUR RJ-BLANC, BETCE-ENJOLIVEUR PC-BLANC, BETCE-PCO-ROUGE, BETCE-PCN-BLANC, BETCE-ETIQUETTE RJ-BLEU
Pset_BuildingElementProxyCommon - Reference: 1PCN+2PCO+2RJ+1HDMI+1USB; sets with these values: 2

# IfcBuildingElementProxy: Poste travail saillie 2x3 modules-2RJ+HDMI_USB sur sortie cable:1PCN+2PCO+2RJ+2HDMI, Poste travail saillie 2x3 modules-2RJ+HDMI_USB sur sortie cable:1PCN+2PCO+2RJ+2HDMI:4582964
In: Niveau 0
Type - Material: <Unnamed>, BETCE-ENJOLIVEUR RJ-BLANC, BETCE-ENJOLIVEUR PC-BLANC, BETCE-PCO-ROUGE, BETCE-PCN-BLANC, BETCE-ETIQUETTE RJ-BLEU
Pset_BuildingElementProxyCommon - Reference: 1PCN+2PCO+2RJ+2HDMI; sets with these values: 2

# IfcBuildingElementProxy: Poste travail saillie 2x3 modules-2RJ+HDMI_USB sur sortie cable:1PCN+2PCO+2RJ+2USB, Poste travail saillie 2x3 modules-2RJ+HDMI_USB sur sortie cable:1PCN+2PCO+2RJ+2USB:4583016
In: Niveau 0
Type - Material: <Unnamed>, BETCE-ENJOLIVEUR RJ-BLANC, BETCE-ENJOLIVEUR PC-BLANC, BETCE-PCO-ROUGE, BETCE-PCN-BLANC, BETCE-ETIQUETTE RJ-BLEU
Pset_BuildingElementProxyCommon - Reference: 1PCN+2PCO+2RJ+2USB; sets with these values: 2

# IfcBuildingElementProxy: Poste travail saillie 2x3 modules-2RJ+HDMI_USB sur sortie cable:2PCN+1PCO+2RJ+1HDMI+1USB, Poste travail saillie 2x3 modules-2RJ+HDMI_USB sur sortie cable:2PCN+1PCO+2RJ+1HDMI+1USB:4583098
In: Niveau 0
Type - Material: <Unnamed>, BETCE-ENJOLIVEUR RJ-BLANC, BETCE-ENJOLIVEUR PC-BLANC, BETCE-PCO-ROUGE, BETCE-PCN-BLANC, BETCE-ETIQUETTE RJ-BLEU
Pset_BuildingElementProxyCommon - Reference: 2PCN+1PCO+2RJ+1HDMI+1USB; sets with these values: 2

# IfcBuildingElementProxy: Poste travail saillie 2x3 modules-2RJ+HDMI_USB sur sortie cable:2PCN+1PCO+2RJ+2HDMI, Poste travail saillie 2x3 modules-2RJ+HDMI_USB sur sortie cable:2PCN+1PCO+2RJ+2HDMI:4583148
In: Niveau 0
Type - Material: <Unnamed>, BETCE-ENJOLIVEUR RJ-BLANC, BETCE-ENJOLIVEUR PC-BLANC, BETCE-PCO-ROUGE, BETCE-PCN-BLANC, BETCE-ETIQUETTE RJ-BLEU
Pset_BuildingElementProxyCommon - Reference: 2PCN+1PCO+2RJ+2HDMI; sets with these values: 2

# IfcBuildingElementProxy: Poste travail saillie 2x3 modules-2RJ+HDMI_USB sur sortie cable:2PCN+1PCO+2RJ+2USB, Poste travail saillie 2x3 modules-2RJ+HDMI_USB sur sortie cable:2PCN+1PCO+2RJ+2USB:4583192
In: Niveau 0
Type - Material: <Unnamed>, BETCE-ENJOLIVEUR RJ-BLANC, BETCE-ENJOLIVEUR PC-BLANC, BETCE-PCO-ROUGE, BETCE-PCN-BLANC, BETCE-ETIQUETTE RJ-BLEU
Pset_BuildingElementProxyCommon - Reference: 2PCN+1PCO+2RJ+2USB; sets with these values: 2

# IfcBuildingElementProxy: Poste travail saillie 2x3 modules-2RJ+HDMI_USB sur sortie cable:3PCN+2RJ+1HDMI+1USB, Poste travail saillie 2x3 modules-2RJ+HDMI_USB sur sortie cable:3PCN+2RJ+1HDMI+1USB:4583274
In: Niveau 0
Type - Material: <Unnamed>, BETCE-ENJOLIVEUR RJ-BLANC, BETCE-ENJOLIVEUR PC-BLANC, BETCE-PCN-BLANC, BETCE-ETIQUETTE RJ-BLEU
Pset_BuildingElementProxyCommon - Reference: 3PCN+2RJ+1HDMI+1USB; sets with these values: 2

# IfcBuildingElementProxy: Poste travail saillie 2x3 modules-2RJ+HDMI_USB sur sortie cable:3PCN+2RJ+2HDMI, Poste travail saillie 2x3 modules-2RJ+HDMI_USB sur sortie cable:3PCN+2RJ+2HDMI:4583340
In: Niveau 0
Type - Material: <Unnamed>, BETCE-ENJOLIVEUR RJ-BLANC, BETCE-ENJOLIVEUR PC-BLANC, BETCE-PCN-BLANC, BETCE-ETIQUETTE RJ-BLEU
Pset_BuildingElementProxyCommon - Reference: 3PCN+2RJ+2HDMI; sets with these values: 2

# IfcBuildingElementProxy: Poste travail saillie 2x3 modules-2RJ+HDMI_USB sur sortie cable:3PCN+2RJ+2USB, Poste travail saillie 2x3 modules-2RJ+HDMI_USB sur sortie cable:3PCN+2RJ+2USB:4583398
In: Niveau 0
Type - Material: <Unnamed>, BETCE-ENJOLIVEUR RJ-BLANC, BETCE-ENJOLIVEUR PC-BLANC, BETCE-PCN-BLANC, BETCE-ETIQUETTE RJ-BLEU
Pset_BuildingElementProxyCommon - Reference: 3PCN+2RJ+2USB; sets with these values: 2

# IfcBuildingElementProxy: Poste travail saillie 2x3 modules-2RJ+HDMI_USB sur sortie cable:3PCO+2RJ+1HDMI+1USB, Poste travail saillie 2x3 modules-2RJ+HDMI_USB sur sortie cable:3PCO+2RJ+1HDMI+1USB:4583454
In: Niveau 0
Type - Material: <Unnamed>, BETCE-ENJOLIVEUR RJ-BLANC, BETCE-ENJOLIVEUR PC-BLANC, BETCE-PCO-ROUGE, BETCE-ETIQUETTE RJ-BLEU
Pset_BuildingElementProxyCommon - Reference: 3PCO+2RJ+1HDMI+1USB; sets with these values: 2

# IfcBuildingElementProxy: Poste travail saillie 2x3 modules-2RJ+HDMI_USB sur sortie cable:3PCO+2RJ+2HDMI, Poste travail saillie 2x3 modules-2RJ+HDMI_USB sur sortie cable:3PCO+2RJ+2HDMI:4583504
In: Niveau 0
Type - Material: <Unnamed>, BETCE-ENJOLIVEUR RJ-BLANC, BETCE-ENJOLIVEUR PC-BLANC, BETCE-PCO-ROUGE, BETCE-ETIQUETTE RJ-BLEU
Pset_BuildingElementProxyCommon - Reference: 3PCO+2RJ+2HDMI; sets with these values: 2

# IfcBuildingElementProxy: Poste travail saillie 2x3 modules-2RJ+HDMI_USB sur sortie cable:3PCO+2RJ+2USB, Poste travail saillie 2x3 modules-2RJ+HDMI_USB sur sortie cable:3PCO+2RJ+2USB:4583590
In: Niveau 0
Type - Material: <Unnamed>, BETCE-ENJOLIVEUR RJ-BLANC, BETCE-ENJOLIVEUR PC-BLANC, BETCE-PCO-ROUGE, BETCE-ETIQUETTE RJ-BLEU
Pset_BuildingElementProxyCommon - Reference: 3PCO+2RJ+2USB; sets with these values: 2

# IfcBuildingElementProxy: Poste travail saillie 2x3 modules-2RJ:2PCN+2PCO+2RJ, Poste travail saillie 2x3 modules-2RJ:2PCN+2PCO+2RJ:4425468
In: Niveau 0
Type - Material: BETCE-ENJOLIVEUR PC-BLANC, BETCE-ENJOLIVEUR RJ-BLANC, BETCE-PCO-ROUGE, BETCE-PCN-BLANC, BETCE-ETIQUETTE RJ-BLEU, <Unnamed>
Pset_BuildingElementProxyCommon - Reference: 2PCN+2PCO+2RJ; sets with these values: 2

# IfcBuildingElementProxy: Poste travail saillie 2x3 modules-2RJ:4PCN+2RJ, Poste travail saillie 2x3 modules-2RJ:4PCN+2RJ:4425746
In: Niveau 0
Type - Material: BETCE-ENJOLIVEUR PC-BLANC, BETCE-ENJOLIVEUR RJ-BLANC, BETCE-PCN-BLANC, BETCE-ETIQUETTE RJ-BLEU, <Unnamed>
Pset_BuildingElementProxyCommon - Reference: 4PCN+2RJ; sets with these values: 2

# IfcBuildingElementProxy: Poste travail saillie 2x3 modules-2RJ:4PCO+2RJ, Poste travail saillie 2x3 modules-2RJ:4PCO+2RJ:4425830
In: Niveau 0
Type - Material: BETCE-ENJOLIVEUR PC-BLANC, BETCE-ENJOLIVEUR RJ-BLANC, BETCE-PCO-ROUGE, BETCE-ETIQUETTE RJ-BLEU, <Unnamed>
Pset_BuildingElementProxyCommon - Reference: 4PCO+2RJ; sets with these values: 2

# IfcBuildingElementProxy: Poste travail saillie 2x3 modules-3RJ:1PCN+2PCO+3RJ, Poste travail saillie 2x3 modules-3RJ:1PCN+2PCO+3RJ:4468843
In: Niveau 0
Type - Material: BETCE-ENJOLIVEUR PC-BLANC, BETCE-ENJOLIVEUR RJ-BLANC, BETCE-PCO-ROUGE, BETCE-PCN-BLANC, BETCE-ETIQUETTE RJ-BLEU, <Unnamed>
Pset_BuildingElementProxyCommon - Reference: 1PCN+2PCO+3RJ; sets with these values: 2

# IfcBuildingElementProxy: Poste travail saillie 2x3 modules-3RJ:2PCN+1PCO+3RJ, Poste travail saillie 2x3 modules-3RJ:2PCN+1PCO+3RJ:4468927
In: Niveau 0
Type - Material: BETCE-ENJOLIVEUR PC-BLANC, BETCE-ENJOLIVEUR RJ-BLANC, BETCE-PCO-ROUGE, BETCE-PCN-BLANC, BETCE-ETIQUETTE RJ-BLEU, <Unnamed>
Pset_BuildingElementProxyCommon - Reference: 2PCN+1PCO+3RJ; sets with these values: 2

# IfcBuildingElementProxy: Poste travail saillie 2x3 modules-3RJ:3PCN+3RJ, Poste travail saillie 2x3 modules-3RJ:3PCN+3RJ:4468957
In: Niveau 0
Type - Material: BETCE-ENJOLIVEUR PC-BLANC, BETCE-ENJOLIVEUR RJ-BLANC, BETCE-PCN-BLANC, BETCE-ETIQUETTE RJ-BLEU, <Unnamed>
Pset_BuildingElementProxyCommon - Reference: 3PCN+3RJ; sets with these values: 2

# IfcBuildingElementProxy: Poste travail saillie 2x3 modules-3RJ:3PCO+3RJ, Poste travail saillie 2x3 modules-3RJ:3PCO+3RJ:4469027
In: Niveau 0
Type - Material: BETCE-ENJOLIVEUR PC-BLANC, BETCE-ENJOLIVEUR RJ-BLANC, BETCE-PCO-ROUGE, BETCE-ETIQUETTE RJ-BLEU, <Unnamed>
Pset_BuildingElementProxyCommon - Reference: 3PCO+3RJ; sets with these values: 2

# IfcBuildingElementProxy: Poste travail saillie 2x4 modules-2RJ:2PCN+4PCO+2RJ, Poste travail saillie 2x4 modules-2RJ:2PCN+4PCO+2RJ:4440135
In: Niveau 0
Type - Material: BETCE-ENJOLIVEUR PC-BLANC, BETCE-PCO-ROUGE, BETCE-PCN-BLANC, BETCE-ENJOLIVEUR RJ-BLANC, BETCE-ETIQUETTE RJ-BLEU, <Unnamed>
Pset_BuildingElementProxyCommon - Reference: 2PCN+4PCO+2RJ; sets with these values: 2

# IfcBuildingElementProxy: Poste travail saillie 2x4 modules-2RJ:3PCN+3PCO+2RJ, Poste travail saillie 2x4 modules-2RJ:3PCN+3PCO+2RJ:4440235
In: Niveau 0
Type - Material: BETCE-ENJOLIVEUR PC-BLANC, BETCE-PCN-BLANC, BETCE-PCO-ROUGE, BETCE-ENJOLIVEUR RJ-BLANC, BETCE-ETIQUETTE RJ-BLEU, <Unnamed>
Pset_BuildingElementProxyCommon - Reference: 3PCN+3PCO+2RJ; sets with these values: 2

# IfcBuildingElementProxy: Poste travail saillie 2x4 modules-2RJ:4PCN+2PCO+2RJ, Poste travail saillie 2x4 modules-2RJ:4PCN+2PCO+2RJ:4440297
In: Niveau 0
Type - Material: BETCE-ENJOLIVEUR PC-BLANC, BETCE-PCO-ROUGE, BETCE-PCN-BLANC, BETCE-ENJOLIVEUR RJ-BLANC, BETCE-ETIQUETTE RJ-BLEU, <Unnamed>
Pset_BuildingElementProxyCommon - Reference: 4PCN+2PCO+2RJ; sets with these values: 2

# IfcBuildingElementProxy: Poste travail saillie 2x4 modules-2RJ:6PCN+2RJ, Poste travail saillie 2x4 modules-2RJ:6PCN+2RJ:4440375
In: Niveau 0
Type - Material: BETCE-ENJOLIVEUR PC-BLANC, BETCE-PCN-BLANC, BETCE-ENJOLIVEUR RJ-BLANC, BETCE-ETIQUETTE RJ-BLEU, <Unnamed>
Pset_BuildingElementProxyCommon - Reference: 6PCN+2RJ; sets with these values: 2

# IfcBuildingElementProxy: Poste travail saillie 2x4 modules-2RJ:6PCO+2RJ, Poste travail saillie 2x4 modules-2RJ:6PCO+2RJ:4440417
In: Niveau 0
Type - Material: BETCE-ENJOLIVEUR PC-BLANC, BETCE-PCO-ROUGE, BETCE-ENJOLIVEUR RJ-BLANC, BETCE-ETIQUETTE RJ-BLEU, <Unnamed>
Pset_BuildingElementProxyCommon - Reference: 6PCO+2RJ; sets with these values: 2

# IfcBuildingElementProxy: Poste travail saillie 2x5 modules-2RJ:2PCN+6PCO+2RJ, Poste travail saillie 2x5 modules-2RJ:2PCN+6PCO+2RJ:4448483
In: Niveau 0
Type - Material: BETCE-ENJOLIVEUR PC-BLANC, BETCE-PCO-ROUGE, BETCE-ENJOLIVEUR RJ-BLANC, BETCE-PCN-BLANC, BETCE-ETIQUETTE RJ-BLEU, <Unnamed>
Pset_BuildingElementProxyCommon - Reference: 2PCN+6PCO+2RJ; sets with these values: 2

# IfcBuildingElementProxy: Poste travail saillie 2x5 modules-2RJ:4PCN+4PCO+2RJ, Poste travail saillie 2x5 modules-2RJ:4PCN+4PCO+2RJ:4448583
In: Niveau 0
Type - Material: BETCE-ENJOLIVEUR PC-BLANC, BETCE-PCO-ROUGE, BETCE-PCN-BLANC, BETCE-ENJOLIVEUR RJ-BLANC, BETCE-ETIQUETTE RJ-BLEU, <Unnamed>
Pset_BuildingElementProxyCommon - Reference: 4PCN+4PCO+2RJ; sets with these values: 2

# IfcBuildingElementProxy: Poste travail saillie 2x5 modules-2RJ:6PCN+2PCO+2RJ, Poste travail saillie 2x5 modules-2RJ:6PCN+2PCO+2RJ:4448655
In: Niveau 0
Type - Material: BETCE-ENJOLIVEUR PC-BLANC, BETCE-PCO-ROUGE, BETCE-PCN-BLANC, BETCE-ENJOLIVEUR RJ-BLANC, BETCE-ETIQUETTE RJ-BLEU, <Unnamed>
Pset_BuildingElementProxyCommon - Reference: 6PCN+2PCO+2RJ; sets with these values: 2

# IfcBuildingElementProxy: Poste travail saillie 2x5 modules-2RJ:8PCN+2RJ, Poste travail saillie 2x5 modules-2RJ:8PCN+2RJ:4448725
In: Niveau 0
Type - Material: BETCE-ENJOLIVEUR PC-BLANC, BETCE-PCN-BLANC, BETCE-ENJOLIVEUR RJ-BLANC, BETCE-ETIQUETTE RJ-BLEU, <Unnamed>
Pset_BuildingElementProxyCommon - Reference: 8PCN+2RJ; sets with these values: 2

# IfcBuildingElementProxy: Poste travail saillie 2x5 modules-2RJ:8PCO+2RJ, Poste travail saillie 2x5 modules-2RJ:8PCO+2RJ:4448783
In: Niveau 0
Type - Material: BETCE-ENJOLIVEUR PC-BLANC, BETCE-PCO-ROUGE, BETCE-ENJOLIVEUR RJ-BLANC, BETCE-ETIQUETTE RJ-BLEU, <Unnamed>
Pset_BuildingElementProxyCommon - Reference: 8PCO+2RJ; sets with these values: 2

# IfcBuildingElementProxy: Prise HDMI+USB goulotte sur sortie de câble:1HDMI+1USB, Prise HDMI+USB goulotte sur sortie de câble:1HDMI+1USB:4237945
In: Niveau 0
Type - Material: <Unnamed>, BETCE-ENVELOPPE SORTIE CABLE-BLANC
Pset_BuildingElementProxyCommon - Reference: 1HDMI+1USB; sets with these values: 2

# IfcBuildingElementProxy: Prise HDMI+USB goulotte sur sortie de câble:2HDMI, Prise HDMI+USB goulotte sur sortie de câble:2HDMI:4238051
In: Niveau 0
Type - Material: <Unnamed>, BETCE-ENVELOPPE SORTIE CABLE-BLANC
Pset_BuildingElementProxyCommon - Reference: 2HDMI; sets with these values: 2

# IfcBuildingElementProxy: Prise HDMI+USB goulotte sur sortie de câble:2USB, Prise HDMI+USB goulotte sur sortie de câble:2USB:4238059
In: Niveau 0
Type - Material: <Unnamed>, BETCE-ENVELOPPE SORTIE CABLE-BLANC
Pset_BuildingElementProxyCommon - Reference: 2USB; sets with these values: 2

# IfcBuildingElementProxy: Prise double HDMI goulotte:2HDMI, Prise double HDMI goulotte:2HDMI:4249860
In: Niveau 0
Type - Material: BETCE-ENJOLIVEUR HDMI-BLANC
Pset_BuildingElementProxyCommon - Reference: 2HDMI; sets with these values: 2

# IfcBuildingElementProxy: Prise double RJ45 goulotte horizontale:2RJ45, Prise double RJ45 goulotte horizontale:2RJ45:4213401
In: Niveau 0
Type - Material: BETCE-ENJOLIVEUR PC-BLANC, BETCE-ETIQUETTE RJ-BLEU
Pset_BuildingElementProxyCommon - Reference: 2RJ45; sets with these values: 2

# IfcBuildingElementProxy: Prise double USB goulotte:2USB, Prise double USB goulotte:2USB:4253642
In: Niveau 0
Type - Material: BETCE-ENJOLIVEUR USB-BLANC
Pset_BuildingElementProxyCommon - Reference: 2USB; sets with these values: 2

# IfcBuildingElementProxy: Prise double encastré horizontale:PC20A, Prise double encastré horizontale:PC20A:3570447
In: Niveau 0
Type - Material: BETCE-ENJOLIVEUR PC-BLANC, <Unnamed>, BETCE-PCN-BLANC
Pset_BuildingElementProxyCommon - Reference: PC20A; sets with these values: 2

# IfcBuildingElementProxy: Prise double encastré horizontale:PCM, Prise double encastré horizontale:PCM:3570143
In: Niveau 0
Type - Material: BETCE-ENJOLIVEUR PC-BLANC, <Unnamed>, BETCE-PCN-BLANC
Pset_BuildingElementProxyCommon - Reference: PCM; sets with these values: 2

# IfcBuildingElementProxy: Prise double encastré horizontale:PCN, Prise double encastré horizontale:PCN:3570247
In: Niveau 0
Type - Material: BETCE-ENJOLIVEUR PC-BLANC, <Unnamed>, BETCE-PCN-BLANC
Pset_BuildingElementProxyCommon - Reference: PCN; sets with these values: 2

# IfcBuildingElementProxy: Prise double encastré horizontale:PCO, Prise double encastré horizontale:PCO:3570343
In: Niveau 0
Type - Material: BETCE-ENJOLIVEUR PC-BLANC, <Unnamed>, BETCE-PCO-ROUGE
Pset_BuildingElementProxyCommon - Reference: PCO; sets with these values: 2

# IfcBuildingElementProxy: Prise double goulotte horizontale:PCM, Prise double goulotte horizontale:PCM:4223120
In: Niveau 0
Type - Material: <Unnamed>, BETCE-PCN-BLANC
Pset_BuildingElementProxyCommon - Reference: PCM; sets with these values: 2

# IfcBuildingElementProxy: Prise double goulotte horizontale:PCN, Prise double goulotte horizontale:PCN:4223128
In: Niveau 0
Type - Material: <Unnamed>, BETCE-PCN-BLANC
Pset_BuildingElementProxyCommon - Reference: PCN; sets with these values: 2

# IfcBuildingElementProxy: Prise double goulotte horizontale:PCO, Prise double goulotte horizontale:PCO:4223136
In: Niveau 0
Type - Material: <Unnamed>, BETCE-PCO-ROUGE
Pset_BuildingElementProxyCommon - Reference: PCO; sets with these values: 2

# IfcBuildingElementProxy: Prise double saillie horizontale:PC20A, Prise double saillie horizontale:PC20A:4402927
In: Niveau 0
Type - Material: <Unnamed>, BETCE-PCN-BLANC, BETCE-ENJOLIVEUR PC-BLANC
Pset_BuildingElementProxyCommon - Reference: PC20A; sets with these values: 2

# IfcBuildingElementProxy: Prise double saillie horizontale:PCM, Prise double saillie horizontale:PCM:4399463
In: Niveau 0
Type - Material: <Unnamed>, BETCE-PCN-BLANC, BETCE-ENJOLIVEUR PC-BLANC
Pset_BuildingElementProxyCommon - Reference: PCM; sets with these values: 2

# IfcBuildingElementProxy: Prise double saillie horizontale:PCN, Prise double saillie horizontale:PCN:4399695
In: Niveau 0
Type - Material: <Unnamed>, BETCE-PCN-BLANC, BETCE-ENJOLIVEUR PC-BLANC
Pset_BuildingElementProxyCommon - Reference: PCN; sets with these values: 2

# IfcBuildingElementProxy: Prise double saillie horizontale:PCO, Prise double saillie horizontale:PCO:4399769
In: Niveau 0
Type - Material: <Unnamed>, BETCE-PCO-ROUGE, BETCE-ENJOLIVEUR PC-BLANC
Pset_BuildingElementProxyCommon - Reference: PCO; sets with these values: 2

# IfcBuildingElementProxy: Prise double saillie étanche horizontale:PC20A, Prise double saillie étanche horizontale:PC20A:4604112
In: Niveau 0
Type - Material: A PVC GRIS 177-177-177, <Unnamed>, A-PVC GRIS 85-85-85
Pset_BuildingElementProxyCommon - Reference: PC20A; sets with these values: 2

# IfcBuildingElementProxy: Prise double saillie étanche horizontale:PCM, Prise double saillie étanche horizontale:PCM:4603700
In: Niveau 0
Type - Material: A PVC GRIS 177-177-177, <Unnamed>, A-PVC GRIS 85-85-85
Pset_BuildingElementProxyCommon - Reference: PCM; sets with these values: 2

# IfcBuildingElementProxy: Prise double saillie étanche horizontale:PCN, Prise double saillie étanche horizontale:PCN:4603920
In: Niveau 0
Type - Material: A PVC GRIS 177-177-177, <Unnamed>, A-PVC GRIS 85-85-85
Pset_BuildingElementProxyCommon - Reference: PCN; sets with these values: 2

# IfcBuildingElementProxy: Prise double saillie étanche horizontale:PCO, Prise double saillie étanche horizontale:PCO:4604046
In: Niveau 0
Type - Material: A PVC GRIS 177-177-177, <Unnamed>, A-PVC GRIS 85-85-85
Pset_BuildingElementProxyCommon - Reference: PCO; sets with these values: 2

# IfcBuildingElementProxy: Prise quadruple RJ45 goulotte horizontale:4RJ45, Prise quadruple RJ45 goulotte horizontale:4RJ45:4217815
In: Niveau 0
Type - Material: BETCE-ENJOLIVEUR RJ-BLANC, BETCE-ETIQUETTE RJ-BLEU
Pset_BuildingElementProxyCommon - Reference: 4RJ45; sets with these values: 2

# IfcBuildingElementProxy: Prise quadruple encastré horizontale:PC20A, Prise quadruple encastré horizontale:PC20A:3581651
In: Niveau 0
Type - Material: <Unnamed>, BETCE-PCN-BLANC, BETCE-ENJOLIVEUR PC-BLANC
Pset_BuildingElementProxyCommon - Reference: PC20A; sets with these values: 2

# IfcBuildingElementProxy: Prise quadruple encastré horizontale:PCM, Prise quadruple encastré horizontale:PCM:3581269
In: Niveau 0
Type - Material: <Unnamed>, BETCE-PCN-BLANC, BETCE-ENJOLIVEUR PC-BLANC
Pset_BuildingElementProxyCommon - Reference: PCM; sets with these values: 2

# IfcBuildingElementProxy: Prise quadruple encastré horizontale:PCN, Prise quadruple encastré horizontale:PCN:3581483
In: Niveau 0
Type - Material: <Unnamed>, BETCE-PCN-BLANC, BETCE-ENJOLIVEUR PC-BLANC
Pset_BuildingElementProxyCommon - Reference: PCN; sets with these values: 2

# IfcBuildingElementProxy: Prise quadruple encastré horizontale:PCO, Prise quadruple encastré horizontale:PCO:3581579
In: Niveau 0
Type - Material: <Unnamed>, BETCE-PCO-ROUGE, BETCE-ENJOLIVEUR PC-BLANC
Pset_BuildingElementProxyCommon - Reference: PCO; sets with these values: 2

# IfcBuildingElementProxy: Prise quadruple goulotte horizontale:PCM, Prise quadruple goulotte horizontale:PCM:4227278
In: Niveau 0
Type - Material: <Unnamed>, BETCE-PCN-BLANC
Pset_BuildingElementProxyCommon - Reference: PCM; sets with these values: 2

# IfcBuildingElementProxy: Prise quadruple goulotte horizontale:PCN, Prise quadruple goulotte horizontale:PCN:4227286
In: Niveau 0
Type - Material: <Unnamed>, BETCE-PCN-BLANC
Pset_BuildingElementProxyCommon - Reference: PCN; sets with these values: 2

# IfcBuildingElementProxy: Prise quadruple goulotte horizontale:PCO, Prise quadruple goulotte horizontale:PCO:4227294
In: Niveau 0
Type - Material: <Unnamed>, BETCE-PCO-ROUGE
Pset_BuildingElementProxyCommon - Reference: PCO; sets with these values: 2

# IfcBuildingElementProxy: Prise quadruple saillie horizontale:PC20A, Prise quadruple saillie horizontale:PC20A:4419034
In: Niveau 0
Type - Material: <Unnamed>, BETCE-PCN-BLANC, BETCE-ENJOLIVEUR PC-BLANC
Pset_BuildingElementProxyCommon - Reference: PC20A; sets with these values: 2

# IfcBuildingElementProxy: Prise quadruple saillie horizontale:PCM, Prise quadruple saillie horizontale:PCM:4418678
In: Niveau 0
Type - Material: <Unnamed>, BETCE-PCN-BLANC, BETCE-ENJOLIVEUR PC-BLANC
Pset_BuildingElementProxyCommon - Reference: PCM; sets with these values: 2

# IfcBuildingElementProxy: Prise quadruple saillie horizontale:PCN, Prise quadruple saillie horizontale:PCN:4418870
In: Niveau 0
Type - Material: <Unnamed>, BETCE-PCN-BLANC, BETCE-ENJOLIVEUR PC-BLANC
Pset_BuildingElementProxyCommon - Reference: PCN; sets with these values: 2

# IfcBuildingElementProxy: Prise quadruple saillie horizontale:PCO, Prise quadruple saillie horizontale:PCO:4418932
In: Niveau 0
Type - Material: <Unnamed>, BETCE-PCO-ROUGE, BETCE-ENJOLIVEUR PC-BLANC
Pset_BuildingElementProxyCommon - Reference: PCO; sets with these values: 2

# IfcBuildingElementProxy: Prise simple HDMI goulotte:1HDMI, Prise simple HDMI goulotte:1HDMI:4246653
In: Niveau 0
Type - Material: BETCE-ENJOLIVEUR HDMI-BLANC
Pset_BuildingElementProxyCommon - Reference: 1HDMI; sets with these values: 2

# IfcBuildingElementProxy: Prise simple RJ45 goulotte:1RJ45, Prise simple RJ45 goulotte:1RJ45:4210680
In: Niveau 0
Type - Material: BETCE-ENJOLIVEUR PC-BLANC, BETCE-ETIQUETTE RJ-BLEU
Pset_BuildingElementProxyCommon - Reference: 1RJ45; sets with these values: 2

# IfcBuildingElementProxy: Prise simple USB goulotte:1USB, Prise simple USB goulotte:1USB:4251689
In: Niveau 0
Type - Material: BETCE-ENJOLIVEUR USB-BLANC
Pset_BuildingElementProxyCommon - Reference: 1USB; sets with these values: 2

# IfcBuildingElementProxy: Prise simple encastré:PC20A, Prise simple encastré:PC20A:3564143
In: Niveau 0
Type - Material: BETCE-ENJOLIVEUR PC-BLANC, <Unnamed>, BETCE-PCN-BLANC
Pset_BuildingElementProxyCommon - Reference: PC20A; sets with these values: 2

# IfcBuildingElementProxy: Prise simple encastré:PCM, Prise simple encastré:PCM:3559803
In: Niveau 0
Type - Material: BETCE-ENJOLIVEUR PC-BLANC, <Unnamed>, BETCE-PCN-BLANC
Pset_BuildingElementProxyCommon - Reference: PCM; sets with these values: 2

# IfcBuildingElementProxy: Prise simple encastré:PCN, Prise simple encastré:PCN:3560243
In: Niveau 0
Type - Material: BETCE-ENJOLIVEUR PC-BLANC, <Unnamed>, BETCE-PCN-BLANC
Pset_BuildingElementProxyCommon - Reference: PCN; sets with these values: 2

# IfcBuildingElementProxy: Prise simple encastré:PCO, Prise simple encastré:PCO:3560383
In: Niveau 0
Type - Material: BETCE-ENJOLIVEUR PC-BLANC, <Unnamed>, BETCE-PCO-ROUGE
Pset_BuildingElementProxyCommon - Reference: PCO; sets with these values: 2

# IfcBuildingElementProxy: Prise simple goulotte:PCM, Prise simple goulotte:PCM:4221181
In: Niveau 0
Type - Material: <Unnamed>, BETCE-PCN-BLANC
Pset_BuildingElementProxyCommon - Reference: PCM; sets with these values: 2

# IfcBuildingElementProxy: Prise simple goulotte:PCN, Prise simple goulotte:PCN:4221182
In: Niveau 0
Type - Material: <Unnamed>, BETCE-PCN-BLANC
Pset_BuildingElementProxyCommon - Reference: PCN; sets with these values: 2

# IfcBuildingElementProxy: Prise simple goulotte:PCO, Prise simple goulotte:PCO:4221183
In: Niveau 0
Type - Material: <Unnamed>, BETCE-PCO-ROUGE
Pset_BuildingElementProxyCommon - Reference: PCO; sets with these values: 2

# IfcBuildingElementProxy: Prise simple saillie étanche:PC20A, Prise simple saillie étanche:PC20A:4601629
In: Niveau 0
Type - Material: <Unnamed>, A PVC GRIS 177-177-177, A-PVC GRIS 85-85-85
Pset_BuildingElementProxyCommon - Reference: PC20A; sets with these values: 2

# IfcBuildingElementProxy: Prise simple saillie étanche:PCM, Prise simple saillie étanche:PCM:4597341
In: Niveau 0
Type - Material: <Unnamed>, A PVC GRIS 177-177-177, A-PVC GRIS 85-85-85
Pset_BuildingElementProxyCommon - Reference: PCM; sets with these values: 2

# IfcBuildingElementProxy: Prise simple saillie étanche:PCN, Prise simple saillie étanche:PCN:4597485
In: Niveau 0
Type - Material: <Unnamed>, A PVC GRIS 177-177-177, A-PVC GRIS 85-85-85
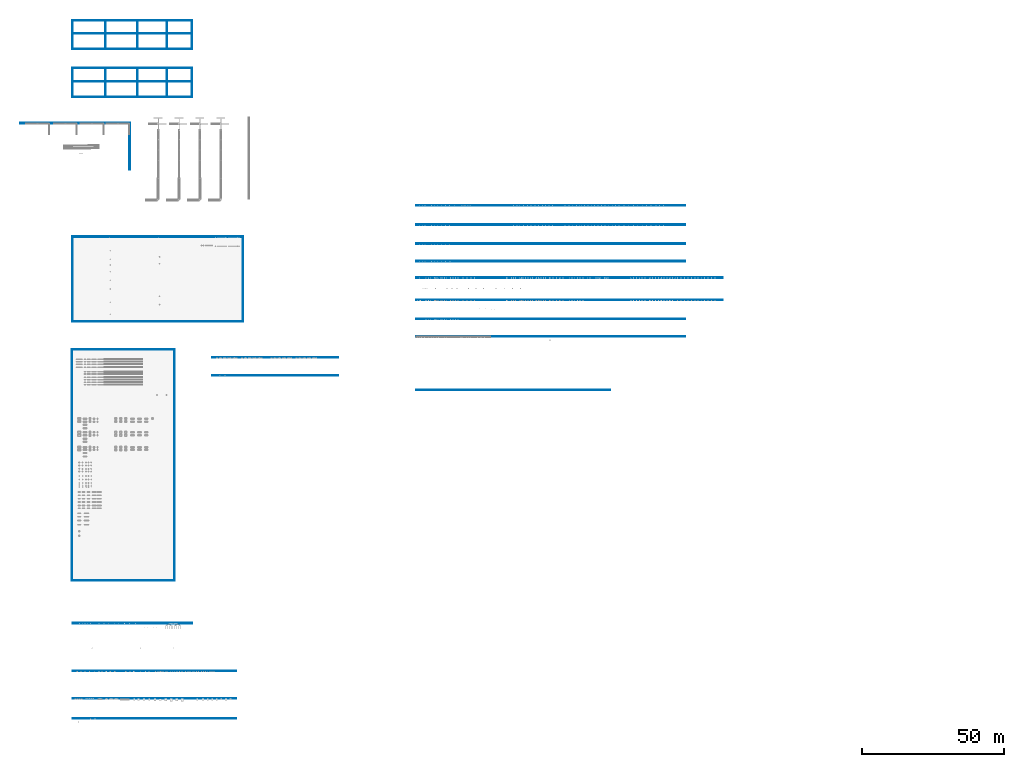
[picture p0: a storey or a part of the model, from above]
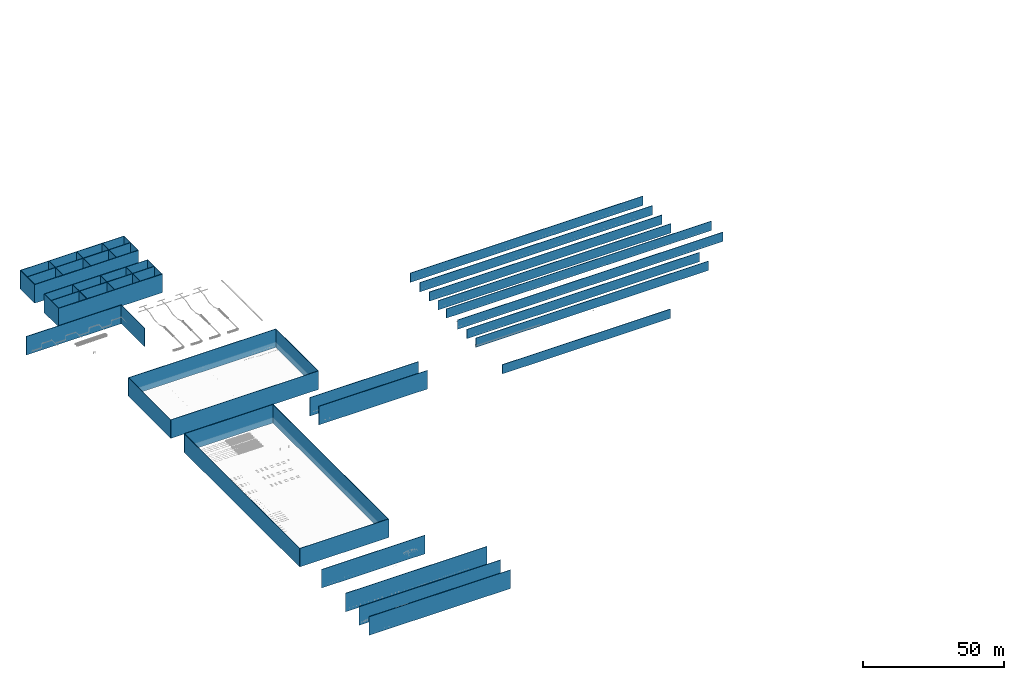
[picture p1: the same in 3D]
Properties of the parts of a building model (IFC2X3), part 3 of 5

# IfcBuildingElementProxy: Prise simple saillie étanche:PCN, Prise simple saillie étanche:PCN:4597485
Pset_BuildingElementProxyCommon - Reference: PCN; sets with these values: 2

# IfcBuildingElementProxy: Prise simple saillie étanche:PCO, Prise simple saillie étanche:PCO:4597599
In: Niveau 0
Type - Material: <Unnamed>, A PVC GRIS 177-177-177, A-PVC GRIS 85-85-85
Pset_BuildingElementProxyCommon - Reference: PCO; sets with these values: 2

# IfcBuildingElementProxy: Prise simple saillie:PC20A, Prise simple saillie:PC20A:4382763
In: Niveau 0
Type - Material: <Unnamed>, BETCE-PCN-BLANC, BETCE-ENJOLIVEUR PC-BLANC
Pset_BuildingElementProxyCommon - Reference: PC20A; sets with these values: 2

# IfcBuildingElementProxy: Prise simple saillie:PCM, Prise simple saillie:PCM:4382859
In: Niveau 0
Type - Material: <Unnamed>, BETCE-PCN-BLANC, BETCE-ENJOLIVEUR PC-BLANC
Pset_BuildingElementProxyCommon - Reference: PCM; sets with these values: 2

# IfcBuildingElementProxy: Prise simple saillie:PCN, Prise simple saillie:PCN:4382979
In: Niveau 0
Type - Material: <Unnamed>, BETCE-PCN-BLANC, BETCE-ENJOLIVEUR PC-BLANC
Pset_BuildingElementProxyCommon - Reference: PCN; sets with these values: 2

# IfcBuildingElementProxy: Prise simple saillie:PCO, Prise simple saillie:PCO:4383095
In: Niveau 0
Type - Material: <Unnamed>, BETCE-PCO-ROUGE, BETCE-ENJOLIVEUR PC-BLANC
Pset_BuildingElementProxyCommon - Reference: PCO; sets with these values: 2

# IfcBuildingElementProxy: Prise simple sol:PC20A, Prise simple sol:PC20A:3585891
In: Niveau 0
Type - Material: A-ENJOLIVEUR BLANC, <Unnamed>
Pset_BuildingElementProxyCommon - Reference: PC20A; sets with these values: 2

# IfcBuildingElementProxy: Prise simple sol:PCM, Prise simple sol:PCM:3585801
In: Niveau 0
Type - Material: A-ENJOLIVEUR BLANC, <Unnamed>
Pset_BuildingElementProxyCommon - Reference: PCM; sets with these values: 2

# IfcBuildingElementProxy: Prise simple sol:PCN, Prise simple sol:PCN:3583584
In: Niveau 0
Type - Material: A-ENJOLIVEUR BLANC, <Unnamed>
Pset_BuildingElementProxyCommon - Reference: PCN; sets with these values: 2

# IfcBuildingElementProxy: Prise simple sol:PCO, Prise simple sol:PCO:3585883
In: Niveau 0
Type - Material: A-ENJOLIVEUR BLANC, <Unnamed>
Pset_BuildingElementProxyCommon - Reference: PCO; sets with these values: 2

# IfcBuildingElementProxy: Prise triple RJ45 goulotte horizontale:3RJ45, Prise triple RJ45 goulotte horizontale:3RJ45:4215544
In: Niveau 0
Type - Material: BETCE-ENJOLIVEUR PC-BLANC, BETCE-ETIQUETTE RJ-BLEU
Pset_BuildingElementProxyCommon - Reference: 3RJ45; sets with these values: 2

# IfcBuildingElementProxy: Prise triple encastré horizontale:PC20A, Prise triple encastré horizontale:PC20A:3576718
In: Niveau 0
Type - Material: <Unnamed>, BETCE-PCN-BLANC, BETCE-ENJOLIVEUR PC-BLANC
Pset_BuildingElementProxyCommon - Reference: PC20A; sets with these values: 2

# IfcBuildingElementProxy: Prise triple encastré horizontale:PCM, Prise triple encastré horizontale:PCM:3576240
In: Niveau 0
Type - Material: <Unnamed>, BETCE-PCN-BLANC, BETCE-ENJOLIVEUR PC-BLANC
Pset_BuildingElementProxyCommon - Reference: PCM; sets with these values: 2

# IfcBuildingElementProxy: Prise triple encastré horizontale:PCN, Prise triple encastré horizontale:PCN:3576512
In: Niveau 0
Type - Material: <Unnamed>, BETCE-PCN-BLANC, BETCE-ENJOLIVEUR PC-BLANC
Pset_BuildingElementProxyCommon - Reference: PCN; sets with these values: 2

# IfcBuildingElementProxy: Prise triple encastré horizontale:PCO, Prise triple encastré horizontale:PCO:3576580
In: Niveau 0
Type - Material: <Unnamed>, BETCE-PCO-ROUGE, BETCE-ENJOLIVEUR PC-BLANC
Pset_BuildingElementProxyCommon - Reference: PCO; sets with these values: 2

# IfcBuildingElementProxy: Prise triple saillie horizontale:PC20A, Prise triple saillie horizontale:PC20A:4415525
In: Niveau 0
Type - Material: <Unnamed>, BETCE-PCN-BLANC, BETCE-ENJOLIVEUR PC-BLANC
Pset_BuildingElementProxyCommon - Reference: PC20A; sets with these values: 2

# IfcBuildingElementProxy: Prise triple saillie horizontale:PCM, Prise triple saillie horizontale:PCM:4412169
In: Niveau 0
Type - Material: <Unnamed>, BETCE-PCN-BLANC, BETCE-ENJOLIVEUR PC-BLANC
Pset_BuildingElementProxyCommon - Reference: PCM; sets with these values: 2

# IfcBuildingElementProxy: Prise triple saillie horizontale:PCN, Prise triple saillie horizontale:PCN:4415379
In: Niveau 0
Type - Material: <Unnamed>, BETCE-PCN-BLANC, BETCE-ENJOLIVEUR PC-BLANC
Pset_BuildingElementProxyCommon - Reference: PCN; sets with these values: 2

# IfcBuildingElementProxy: Prise triple saillie horizontale:PCO, Prise triple saillie horizontale:PCO:4415447
In: Niveau 0
Type - Material: <Unnamed>, BETCE-PCO-ROUGE, BETCE-ENJOLIVEUR PC-BLANC
Pset_BuildingElementProxyCommon - Reference: PCO; sets with these values: 2

# IfcBuildingElementProxy: Prise triple saillie étanche horizontale:PC20A, Prise triple saillie étanche horizontale:PC20A:4606643
In: Niveau 0
Type - Material: A PVC GRIS 177-177-177, <Unnamed>, A-PVC GRIS 85-85-85
Pset_BuildingElementProxyCommon - Reference: PC20A; sets with these values: 2

# IfcBuildingElementProxy: Prise triple saillie étanche horizontale:PCM, Prise triple saillie étanche horizontale:PCM:4606355
In: Niveau 0
Type - Material: A PVC GRIS 177-177-177, <Unnamed>, A-PVC GRIS 85-85-85
Pset_BuildingElementProxyCommon - Reference: PCM; sets with these values: 2

# IfcBuildingElementProxy: Prise triple saillie étanche horizontale:PCN, Prise triple saillie étanche horizontale:PCN:4606517
In: Niveau 0
Type - Material: A PVC GRIS 177-177-177, <Unnamed>, A-PVC GRIS 85-85-85
Pset_BuildingElementProxyCommon - Reference: PCN; sets with these values: 2

# IfcBuildingElementProxy: Prise triple saillie étanche horizontale:PCO, Prise triple saillie étanche horizontale:PCO:4606593
In: Niveau 0
Type - Material: A PVC GRIS 177-177-177, <Unnamed>, A-PVC GRIS 85-85-85
Pset_BuildingElementProxyCommon - Reference: PCO; sets with these values: 2

# IfcBuildingElementProxy: Sirene exterieur intrusion:Sirene exterieur intrusion, Sirene exterieur intrusion:Sirene exterieur intrusion:4075321
In: Niveau 0
Type - Material: <Unnamed>
Type - Pset_ElementShading - Color: painted silver
Type - Pset_ManufacturerTypeInformation - Manufacturer: Urmet S.p.A.Urmet S.p.A.
Classification: 80HP8600211 (Uniformat)
Pset_BuildingElementProxyCommon - Reference: Sirene exterieur intrusion; sets with these values: 2

# IfcBuildingElementProxy: Sirene_Sonnerie interieur:Diffuseur sonor et visuel visiophone, Sirene_Sonnerie interieur:Diffuseur sonor et visuel visiophone:4071507
In: Niveau 0
Type - Material: <Unnamed>
Type - Pset_ElementShading - Color: White RAL9003
Type - Pset_ManufacturerTypeInformation - Manufacturer: Urmet S.p.A.Urmet S.p.A.
Classification: 80HP1B00211 (Uniformat)
Pset_BuildingElementProxyCommon - Reference: Diffuseur sonor et visuel visiophone; sets with these values: 2

# IfcBuildingElementProxy: Sirene_Sonnerie interieur:Diffuseur sonor interieur intrusion, Sirene_Sonnerie interieur:Diffuseur sonor interieur intrusion:4071387
In: Niveau 0
Type - Material: <Unnamed>
Type - Pset_ElementShading - Color: White RAL9003
Type - Pset_ManufacturerTypeInformation - Manufacturer: Urmet S.p.A.Urmet S.p.A.
Classification: 80HP1B00211 (Uniformat)
Pset_BuildingElementProxyCommon - Reference: Diffuseur sonor interieur intrusion; sets with these values: 2

# IfcBuildingElementProxy: Sirene_Sonnerie interieur:Diffuseur sonor visiophone, Sirene_Sonnerie interieur:Diffuseur sonor visiophone:4071500
In: Niveau 0
Type - Material: <Unnamed>
Type - Pset_ElementShading - Color: White RAL9003
Type - Pset_ManufacturerTypeInformation - Manufacturer: Urmet S.p.A.Urmet S.p.A.
Classification: 80HP1B00211 (Uniformat)
Pset_BuildingElementProxyCommon - Reference: Diffuseur sonor visiophone; sets with these values: 2

# IfcBuildingElementProxy: Socle béton-borne 4:Socle béton-borne 4, Socle béton-borne 4:Socle béton-borne 4:6171600
In: Niveau 0
Type - Material: <Unnamed>
Pset_BuildingElementProxyCommon - Reference: Socle béton-borne 4; sets with these values: 2

# IfcBuildingElementProxy: Tableau commande 1x4 modules encastré:1 SA + 1 BP + 2 VV, Tableau commande 1x4 modules encastré:1 SA + 1 BP + 2 VV:3383102
In: Niveau 0
Type - Material: <Unnamed>, BETCE-DOIGT-BLANC, BETCE-ENJOLIVEUR-BLANC
Pset_BuildingElementProxyCommon - Reference: 1 SA + 1 BP + 2 VV; sets with these values: 2

# IfcBuildingElementProxy: Tableau commande 1x4 modules encastré:1 SA + 1 VV + 2BP, Tableau commande 1x4 modules encastré:1 SA + 1 VV + 2BP:3383274
In: Niveau 0
Type - Material: <Unnamed>, BETCE-DOIGT-BLANC, BETCE-ENJOLIVEUR-BLANC
Pset_BuildingElementProxyCommon - Reference: 1 SA + 1 VV + 2BP; sets with these values: 2

# IfcBuildingElementProxy: Tableau commande 1x4 modules encastré:1 SA + 3 BP, Tableau commande 1x4 modules encastré:1 SA + 3 BP:3383422
In: Niveau 0
Type - Material: <Unnamed>, BETCE-DOIGT-BLANC, BETCE-ENJOLIVEUR-BLANC
Pset_BuildingElementProxyCommon - Reference: 1 SA + 3 BP; sets with these values: 2

# IfcBuildingElementProxy: Tableau commande 1x4 modules encastré:1 VV + 3 BP, Tableau commande 1x4 modules encastré:1 VV + 3 BP:3383568
In: Niveau 0
Type - Material: <Unnamed>, BETCE-DOIGT-BLANC, BETCE-ENJOLIVEUR-BLANC
Pset_BuildingElementProxyCommon - Reference: 1 VV + 3 BP; sets with these values: 2

# IfcBuildingElementProxy: Tableau commande 1x4 modules encastré:2 SA + 1 BP + 1 VV, Tableau commande 1x4 modules encastré:2 SA + 1 BP + 1 VV:3383704
In: Niveau 0
Type - Material: <Unnamed>, BETCE-DOIGT-BLANC, BETCE-ENJOLIVEUR-BLANC
Pset_BuildingElementProxyCommon - Reference: 2 SA + 1 BP + 1 VV; sets with these values: 2

# IfcBuildingElementProxy: Tableau commande 1x4 modules encastré:2 SA + 2 BP, Tableau commande 1x4 modules encastré:2 SA + 2 BP:3383836
In: Niveau 0
Type - Material: <Unnamed>, BETCE-DOIGT-BLANC, BETCE-ENJOLIVEUR-BLANC
Pset_BuildingElementProxyCommon - Reference: 2 SA + 2 BP; sets with these values: 2

# IfcBuildingElementProxy: Tableau commande 1x4 modules encastré:2 VV + 2 BP, Tableau commande 1x4 modules encastré:2 VV + 2 BP:3383954
In: Niveau 0
Type - Material: <Unnamed>, BETCE-DOIGT-BLANC, BETCE-ENJOLIVEUR-BLANC
Pset_BuildingElementProxyCommon - Reference: 2 VV + 2 BP; sets with these values: 2

# IfcBuildingElementProxy: Tableau commande 1x4 modules encastré:3 SA + 1 BP, Tableau commande 1x4 modules encastré:3 SA + 1 BP:3384076
In: Niveau 0
Type - Material: <Unnamed>, BETCE-DOIGT-BLANC, BETCE-ENJOLIVEUR-BLANC
Pset_BuildingElementProxyCommon - Reference: 3 SA + 1 BP; sets with these values: 2

# IfcBuildingElementProxy: Tableau commande 1x4 modules encastré:3 VV + 1 BP, Tableau commande 1x4 modules encastré:3 VV + 1 BP:3384246
In: Niveau 0
Type - Material: <Unnamed>, BETCE-DOIGT-BLANC, BETCE-ENJOLIVEUR-BLANC
Pset_BuildingElementProxyCommon - Reference: 3 VV + 1 BP; sets with these values: 2

# IfcBuildingElementProxy: Tableau commande 1x4 modules encastré:4 BP, Tableau commande 1x4 modules encastré:4 BP:3375255
In: Niveau 0
Type - Material: <Unnamed>, BETCE-DOIGT-BLANC, BETCE-ENJOLIVEUR-BLANC
Pset_BuildingElementProxyCommon - Reference: 4 BP; sets with these values: 2

# IfcBuildingElementProxy: Tableau commande 1x4 modules encastré:4 SA, Tableau commande 1x4 modules encastré:4 SA:3382830
In: Niveau 0
Type - Material: <Unnamed>, BETCE-DOIGT-BLANC, BETCE-ENJOLIVEUR-BLANC
Pset_BuildingElementProxyCommon - Reference: 4 SA; sets with these values: 2

# IfcBuildingElementProxy: Tableau commande 1x4 modules encastré:4 VV, Tableau commande 1x4 modules encastré:4 VV:3382948
In: Niveau 0
Type - Material: <Unnamed>, BETCE-DOIGT-BLANC, BETCE-ENJOLIVEUR-BLANC
Pset_BuildingElementProxyCommon - Reference: 4 VV; sets with these values: 2

# IfcBuildingElementProxy: Tableau commande 1x4 modules saillie:1 SA + 1 BP + 2 VV, Tableau commande 1x4 modules saillie:1 SA + 1 BP + 2 VV:3414011
In: Niveau 0
Type - Material: BETCE-DOIGT-BLANC, BETCE-CADRE-BLANC, BETCE-ENJOLIVEUR-BLANC
Pset_BuildingElementProxyCommon - Reference: 1 SA + 1 BP + 2 VV; sets with these values: 2

# IfcBuildingElementProxy: Tableau commande 1x4 modules saillie:1 SA + 1 VV + 2 BP, Tableau commande 1x4 modules saillie:1 SA + 1 VV + 2 BP:3414143
In: Niveau 0
Type - Material: BETCE-DOIGT-BLANC, BETCE-CADRE-BLANC, BETCE-ENJOLIVEUR-BLANC
Pset_BuildingElementProxyCommon - Reference: 1 SA + 1 VV + 2 BP; sets with these values: 2

# IfcBuildingElementProxy: Tableau commande 1x4 modules saillie:1 SA + 3 BP, Tableau commande 1x4 modules saillie:1 SA + 3 BP:3414243
In: Niveau 0
Type - Material: BETCE-DOIGT-BLANC, BETCE-CADRE-BLANC, BETCE-ENJOLIVEUR-BLANC
Pset_BuildingElementProxyCommon - Reference: 1 SA + 3 BP; sets with these values: 2

# IfcBuildingElementProxy: Tableau commande 1x4 modules saillie:1 VV + 3 BP, Tableau commande 1x4 modules saillie:1 VV + 3 BP:3414325
In: Niveau 0
Type - Material: BETCE-DOIGT-BLANC, BETCE-CADRE-BLANC, BETCE-ENJOLIVEUR-BLANC
Pset_BuildingElementProxyCommon - Reference: 1 VV + 3 BP; sets with these values: 2

# IfcBuildingElementProxy: Tableau commande 1x4 modules saillie:2 SA + 1 BP + 1 VV, Tableau commande 1x4 modules saillie:2 SA + 1 BP + 1 VV:3414375
In: Niveau 0
Type - Material: BETCE-DOIGT-BLANC, BETCE-CADRE-BLANC, BETCE-ENJOLIVEUR-BLANC
Pset_BuildingElementProxyCommon - Reference: 2 SA + 1 BP + 1 VV; sets with these values: 2

# IfcBuildingElementProxy: Tableau commande 1x4 modules saillie:2 SA + 2 BP, Tableau commande 1x4 modules saillie:2 SA + 2 BP:3414495
In: Niveau 0
Type - Material: BETCE-DOIGT-BLANC, BETCE-CADRE-BLANC, BETCE-ENJOLIVEUR-BLANC
Pset_BuildingElementProxyCommon - Reference: 2 SA + 2 BP; sets with these values: 2

# IfcBuildingElementProxy: Tableau commande 1x4 modules saillie:2 VV + 2 BP, Tableau commande 1x4 modules saillie:2 VV + 2 BP:3414607
In: Niveau 0
Type - Material: BETCE-DOIGT-BLANC, BETCE-CADRE-BLANC, BETCE-ENJOLIVEUR-BLANC
Pset_BuildingElementProxyCommon - Reference: 2 VV + 2 BP; sets with these values: 2

# IfcBuildingElementProxy: Tableau commande 1x4 modules saillie:3 SA + 1 BP, Tableau commande 1x4 modules saillie:3 SA + 1 BP:3414757
In: Niveau 0
Type - Material: BETCE-DOIGT-BLANC, BETCE-CADRE-BLANC, BETCE-ENJOLIVEUR-BLANC
Pset_BuildingElementProxyCommon - Reference: 3 SA + 1 BP; sets with these values: 2

# IfcBuildingElementProxy: Tableau commande 1x4 modules saillie:3 VV + 1 BP, Tableau commande 1x4 modules saillie:3 VV + 1 BP:3414851
In: Niveau 0
Type - Material: BETCE-DOIGT-BLANC, BETCE-CADRE-BLANC, BETCE-ENJOLIVEUR-BLANC
Pset_BuildingElementProxyCommon - Reference: 3 VV + 1 BP; sets with these values: 2

# IfcBuildingElementProxy: Tableau commande 1x4 modules saillie:4 BP, Tableau commande 1x4 modules saillie:4 BP:3398740
In: Niveau 0
Type - Material: BETCE-DOIGT-BLANC, BETCE-CADRE-BLANC, BETCE-ENJOLIVEUR-BLANC
Pset_BuildingElementProxyCommon - Reference: 4 BP; sets with these values: 2

# IfcBuildingElementProxy: Tableau commande 1x4 modules saillie:4 SA, Tableau commande 1x4 modules saillie:4 SA:3398969
In: Niveau 0
Type - Material: BETCE-DOIGT-BLANC, BETCE-CADRE-BLANC, BETCE-ENJOLIVEUR-BLANC
Pset_BuildingElementProxyCommon - Reference: 4 SA; sets with these values: 2

# IfcBuildingElementProxy: Tableau commande 1x4 modules saillie:4 VV, Tableau commande 1x4 modules saillie:4 VV:3413893
In: Niveau 0
Type - Material: BETCE-DOIGT-BLANC, BETCE-CADRE-BLANC, BETCE-ENJOLIVEUR-BLANC
Pset_BuildingElementProxyCommon - Reference: 4 VV; sets with these values: 2

# IfcBuildingElementProxy: Tableau commande 2x4 modules encastré:1 BP + 7 SA, Tableau commande 2x4 modules encastré:1 BP + 7 SA:3431603
In: Niveau 0
Type - Material: <Unnamed>, BETCE-DOIGT-BLANC, BETCE-ENJOLIVEUR-BLANC
Pset_BuildingElementProxyCommon - Reference: 1 BP + 7 SA; sets with these values: 2

# IfcBuildingElementProxy: Tableau commande 2x4 modules encastré:1 BP + 7 VV, Tableau commande 2x4 modules encastré:1 BP + 7 VV:3432521
In: Niveau 0
Type - Material: <Unnamed>, BETCE-DOIGT-BLANC, BETCE-ENJOLIVEUR-BLANC
Pset_BuildingElementProxyCommon - Reference: 1 BP + 7 VV; sets with these values: 2

# IfcBuildingElementProxy: Tableau commande 2x4 modules encastré:1 SA + 7 VV, Tableau commande 2x4 modules encastré:1 SA + 7 VV:3449216
In: Niveau 0
Type - Material: <Unnamed>, BETCE-DOIGT-BLANC, BETCE-ENJOLIVEUR-BLANC
Pset_BuildingElementProxyCommon - Reference: 1 SA + 7 VV; sets with these values: 2

# IfcBuildingElementProxy: Tableau commande 2x4 modules encastré:2 BP + 2 SA + 4 VV, Tableau commande 2x4 modules encastré:2 BP + 2 SA + 4 VV:3449922
In: Niveau 0
Type - Material: <Unnamed>, BETCE-DOIGT-BLANC, BETCE-ENJOLIVEUR-BLANC
Pset_BuildingElementProxyCommon - Reference: 2 BP + 2 SA + 4 VV; sets with these values: 2

# IfcBuildingElementProxy: Tableau commande 2x4 modules encastré:2 BP + 4 SA + 2 VV, Tableau commande 2x4 modules encastré:2 BP + 4 SA + 2 VV:3465859
In: Niveau 0
Type - Material: <Unnamed>, BETCE-DOIGT-BLANC, BETCE-ENJOLIVEUR-BLANC
Pset_BuildingElementProxyCommon - Reference: 2 BP + 4 SA + 2 VV; sets with these values: 2

# IfcBuildingElementProxy: Tableau commande 2x4 modules encastré:2 BP + 6 SA, Tableau commande 2x4 modules encastré:2 BP + 6 SA:3431717
In: Niveau 0
Type - Material: <Unnamed>, BETCE-DOIGT-BLANC, BETCE-ENJOLIVEUR-BLANC
Pset_BuildingElementProxyCommon - Reference: 2 BP + 6 SA; sets with these values: 2

# IfcBuildingElementProxy: Tableau commande 2x4 modules encastré:2 BP + 6 VV, Tableau commande 2x4 modules encastré:2 BP + 6 VV:3432659
In: Niveau 0
Type - Material: <Unnamed>, BETCE-DOIGT-BLANC, BETCE-ENJOLIVEUR-BLANC
Pset_BuildingElementProxyCommon - Reference: 2 BP + 6 VV; sets with these values: 2

# IfcBuildingElementProxy: Tableau commande 2x4 modules encastré:2 SA + 6 VV, Tableau commande 2x4 modules encastré:2 SA + 6 VV:3449342
In: Niveau 0
Type - Material: <Unnamed>, BETCE-DOIGT-BLANC, BETCE-ENJOLIVEUR-BLANC
Pset_BuildingElementProxyCommon - Reference: 2 SA + 6 VV; sets with these values: 2

# IfcBuildingElementProxy: Tableau commande 2x4 modules encastré:3 BP + 5 SA, Tableau commande 2x4 modules encastré:3 BP + 5 SA:3431837
In: Niveau 0
Type - Material: <Unnamed>, BETCE-DOIGT-BLANC, BETCE-ENJOLIVEUR-BLANC
Pset_BuildingElementProxyCommon - Reference: 3 BP + 5 SA; sets with these values: 2

# IfcBuildingElementProxy: Tableau commande 2x4 modules encastré:3 BP + 5 VV, Tableau commande 2x4 modules encastré:3 BP + 5 VV:3432791
In: Niveau 0
Type - Material: <Unnamed>, BETCE-DOIGT-BLANC, BETCE-ENJOLIVEUR-BLANC
Pset_BuildingElementProxyCommon - Reference: 3 BP + 5 VV; sets with these values: 2

# IfcBuildingElementProxy: Tableau commande 2x4 modules encastré:3 SA + 5 VV, Tableau commande 2x4 modules encastré:3 SA + 5 VV:3449474
In: Niveau 0
Type - Material: <Unnamed>, BETCE-DOIGT-BLANC, BETCE-ENJOLIVEUR-BLANC
Pset_BuildingElementProxyCommon - Reference: 3 SA + 5 VV; sets with these values: 2

# IfcBuildingElementProxy: Tableau commande 2x4 modules encastré:4 BP + 2 SA + 2 VV, Tableau commande 2x4 modules encastré:4 BP + 2 SA + 2 VV:3465973
In: Niveau 0
Type - Material: <Unnamed>, BETCE-DOIGT-BLANC, BETCE-ENJOLIVEUR-BLANC
Pset_BuildingElementProxyCommon - Reference: 4 BP + 2 SA + 2 VV; sets with these values: 2

# IfcBuildingElementProxy: Tableau commande 2x4 modules encastré:4 BP + 4 SA, Tableau commande 2x4 modules encastré:4 BP + 4 SA:3431985
In: Niveau 0
Type - Material: <Unnamed>, BETCE-DOIGT-BLANC, BETCE-ENJOLIVEUR-BLANC
Pset_BuildingElementProxyCommon - Reference: 4 BP + 4 SA; sets with these values: 2

# IfcBuildingElementProxy: Tableau commande 2x4 modules encastré:4 BP + 4 VV, Tableau commande 2x4 modules encastré:4 BP + 4 VV:3448712
In: Niveau 0
Type - Material: <Unnamed>, BETCE-DOIGT-BLANC, BETCE-ENJOLIVEUR-BLANC
Pset_BuildingElementProxyCommon - Reference: 4 BP + 4 VV; sets with these values: 2

# IfcBuildingElementProxy: Tableau commande 2x4 modules encastré:4 SA + 4 VV, Tableau commande 2x4 modules encastré:4 SA + 4 VV:3449596
In: Niveau 0
Type - Material: <Unnamed>, BETCE-DOIGT-BLANC, BETCE-ENJOLIVEUR-BLANC
Pset_BuildingElementProxyCommon - Reference: 4 SA + 4 VV; sets with these values: 2

# IfcBuildingElementProxy: Tableau commande 2x4 modules encastré:5 BP + 3 SA, Tableau commande 2x4 modules encastré:5 BP + 3 SA:3432093
In: Niveau 0
Type - Material: <Unnamed>, BETCE-DOIGT-BLANC, BETCE-ENJOLIVEUR-BLANC
Pset_BuildingElementProxyCommon - Reference: 5 BP + 3 SA; sets with these values: 2

# IfcBuildingElementProxy: Tableau commande 2x4 modules encastré:5 BP + 3 VV, Tableau commande 2x4 modules encastré:5 BP + 3 VV:3448812
In: Niveau 0
Type - Material: <Unnamed>, BETCE-DOIGT-BLANC, BETCE-ENJOLIVEUR-BLANC
Pset_BuildingElementProxyCommon - Reference: 5 BP + 3 VV; sets with these values: 2

# IfcBuildingElementProxy: Tableau commande 2x4 modules encastré:5 SA + 3 VV, Tableau commande 2x4 modules encastré:5 SA + 3 VV:3449706
In: Niveau 0
Type - Material: <Unnamed>, BETCE-DOIGT-BLANC, BETCE-ENJOLIVEUR-BLANC
Pset_BuildingElementProxyCommon - Reference: 5 SA + 3 VV; sets with these values: 2

# IfcBuildingElementProxy: Tableau commande 2x4 modules encastré:6 BP + 2 SA, Tableau commande 2x4 modules encastré:6 BP + 2 SA:3432229
In: Niveau 0
Type - Material: <Unnamed>, BETCE-DOIGT-BLANC, BETCE-ENJOLIVEUR-BLANC
Pset_BuildingElementProxyCommon - Reference: 6 BP + 2 SA; sets with these values: 2

# IfcBuildingElementProxy: Tableau commande 2x4 modules encastré:6 BP + 2 VV, Tableau commande 2x4 modules encastré:6 BP + 2 VV:3448932
In: Niveau 0
Type - Material: <Unnamed>, BETCE-DOIGT-BLANC, BETCE-ENJOLIVEUR-BLANC
Pset_BuildingElementProxyCommon - Reference: 6 BP + 2 VV; sets with these values: 2

# IfcBuildingElementProxy: Tableau commande 2x4 modules encastré:6 SA + 2 VV, Tableau commande 2x4 modules encastré:6 SA + 2 VV:3449786
In: Niveau 0
Type - Material: <Unnamed>, BETCE-DOIGT-BLANC, BETCE-ENJOLIVEUR-BLANC
Pset_BuildingElementProxyCommon - Reference: 6 SA + 2 VV; sets with these values: 2

# IfcBuildingElementProxy: Tableau commande 2x4 modules encastré:7 BP + 1 SA, Tableau commande 2x4 modules encastré:7 BP + 1 SA:3432331
In: Niveau 0
Type - Material: <Unnamed>, BETCE-DOIGT-BLANC, BETCE-ENJOLIVEUR-BLANC
Pset_BuildingElementProxyCommon - Reference: 7 BP + 1 SA; sets with these values: 2

# IfcBuildingElementProxy: Tableau commande 2x4 modules encastré:7 BP + 1 VV, Tableau commande 2x4 modules encastré:7 BP + 1 VV:3449060
In: Niveau 0
Type - Material: <Unnamed>, BETCE-DOIGT-BLANC, BETCE-ENJOLIVEUR-BLANC
Pset_BuildingElementProxyCommon - Reference: 7 BP + 1 VV; sets with these values: 2

# IfcBuildingElementProxy: Tableau commande 2x4 modules encastré:7 SA + 1 VV, Tableau commande 2x4 modules encastré:7 SA + 1 VV:3449858
In: Niveau 0
Type - Material: <Unnamed>, BETCE-DOIGT-BLANC, BETCE-ENJOLIVEUR-BLANC
Pset_BuildingElementProxyCommon - Reference: 7 SA + 1 VV; sets with these values: 2

# IfcBuildingElementProxy: Tableau commande 2x4 modules encastré:8 BP, Tableau commande 2x4 modules encastré:8 BP:3430863
In: Niveau 0
Type - Material: <Unnamed>, BETCE-DOIGT-BLANC, BETCE-ENJOLIVEUR-BLANC
Pset_BuildingElementProxyCommon - Reference: 8 BP; sets with these values: 2

# IfcBuildingElementProxy: Tableau commande 2x4 modules encastré:8 SA, Tableau commande 2x4 modules encastré:8 SA:3431479
In: Niveau 0
Type - Material: <Unnamed>, BETCE-DOIGT-BLANC, BETCE-ENJOLIVEUR-BLANC
Pset_BuildingElementProxyCommon - Reference: 8 SA; sets with these values: 2

# IfcBuildingElementProxy: Tableau commande 2x4 modules encastré:8 VV, Tableau commande 2x4 modules encastré:8 VV:3431553
In: Niveau 0
Type - Material: <Unnamed>, BETCE-DOIGT-BLANC, BETCE-ENJOLIVEUR-BLANC
Pset_BuildingElementProxyCommon - Reference: 8 VV; sets with these values: 2

# IfcBuildingElementProxy: Tableau commande 2x4 modules saillie:1 BP + 7 SA, Tableau commande 2x4 modules saillie:1 BP + 7 SA:3483822
In: Niveau 0
Type - Material: BETCE-CADRE-BLANC, BETCE-DOIGT-BLANC, BETCE-ENJOLIVEUR-BLANC
Pset_BuildingElementProxyCommon - Reference: 1 BP + 7 SA; sets with these values: 2

# IfcBuildingElementProxy: Tableau commande 2x4 modules saillie:1 BP + 7 VV, Tableau commande 2x4 modules saillie:1 BP + 7 VV:3484554
In: Niveau 0
Type - Material: BETCE-CADRE-BLANC, BETCE-DOIGT-BLANC, BETCE-ENJOLIVEUR-BLANC
Pset_BuildingElementProxyCommon - Reference: 1 BP + 7 VV; sets with these values: 2

# IfcBuildingElementProxy: Tableau commande 2x4 modules saillie:1 SA + 7 VV, Tableau commande 2x4 modules saillie:1 SA + 7 VV:3485258
In: Niveau 0
Type - Material: BETCE-CADRE-BLANC, BETCE-DOIGT-BLANC, BETCE-ENJOLIVEUR-BLANC
Pset_BuildingElementProxyCommon - Reference: 1 SA + 7 VV; sets with these values: 2

# IfcBuildingElementProxy: Tableau commande 2x4 modules saillie:2 BP + 2 SA + 4 VV, Tableau commande 2x4 modules saillie:2 BP + 2 SA + 4 VV:3486028
In: Niveau 0
Type - Material: BETCE-CADRE-BLANC, BETCE-DOIGT-BLANC, BETCE-ENJOLIVEUR-BLANC
Pset_BuildingElementProxyCommon - Reference: 2 BP + 2 SA + 4 VV; sets with these values: 2

# IfcBuildingElementProxy: Tableau commande 2x4 modules saillie:2 BP + 4 SA + 2 VV, Tableau commande 2x4 modules saillie:2 BP + 4 SA + 2 VV:3486144
In: Niveau 0
Type - Material: BETCE-CADRE-BLANC, BETCE-DOIGT-BLANC, BETCE-ENJOLIVEUR-BLANC
Pset_BuildingElementProxyCommon - Reference: 2 BP + 4 SA + 2 VV; sets with these values: 2

# IfcBuildingElementProxy: Tableau commande 2x4 modules saillie:2 BP + 6 SA, Tableau commande 2x4 modules saillie:2 BP + 6 SA:3483958
In: Niveau 0
Type - Material: BETCE-CADRE-BLANC, BETCE-DOIGT-BLANC, BETCE-ENJOLIVEUR-BLANC
Pset_BuildingElementProxyCommon - Reference: 2 BP + 6 SA; sets with these values: 2

# IfcBuildingElementProxy: Tableau commande 2x4 modules saillie:2 BP + 6 VV, Tableau commande 2x4 modules saillie:2 BP + 6 VV:3484646
In: Niveau 0
Type - Material: BETCE-CADRE-BLANC, BETCE-DOIGT-BLANC, BETCE-ENJOLIVEUR-BLANC
Pset_BuildingElementProxyCommon - Reference: 2 BP + 6 VV; sets with these values: 2

# IfcBuildingElementProxy: Tableau commande 2x4 modules saillie:2 SA + 6 VV, Tableau commande 2x4 modules saillie:2 SA + 6 VV:3485342
In: Niveau 0
Type - Material: BETCE-CADRE-BLANC, BETCE-DOIGT-BLANC, BETCE-ENJOLIVEUR-BLANC
Pset_BuildingElementProxyCommon - Reference: 2 SA + 6 VV; sets with these values: 2

# IfcBuildingElementProxy: Tableau commande 2x4 modules saillie:3 BP + 5 SA, Tableau commande 2x4 modules saillie:3 BP + 5 SA:3484080
In: Niveau 0
Type - Material: BETCE-CADRE-BLANC, BETCE-DOIGT-BLANC, BETCE-ENJOLIVEUR-BLANC
Pset_BuildingElementProxyCommon - Reference: 3 BP + 5 SA; sets with these values: 2

# IfcBuildingElementProxy: Tableau commande 2x4 modules saillie:3 BP + 5 VV, Tableau commande 2x4 modules saillie:3 BP + 5 VV:3484760
In: Niveau 0
Type - Material: BETCE-CADRE-BLANC, BETCE-DOIGT-BLANC, BETCE-ENJOLIVEUR-BLANC
Pset_BuildingElementProxyCommon - Reference: 3 BP + 5 VV; sets with these values: 2

# IfcBuildingElementProxy: Tableau commande 2x4 modules saillie:3 SA + 5 VV, Tableau commande 2x4 modules saillie:3 SA + 5 VV:3485438
In: Niveau 0
Type - Material: BETCE-CADRE-BLANC, BETCE-DOIGT-BLANC, BETCE-ENJOLIVEUR-BLANC
Pset_BuildingElementProxyCommon - Reference: 3 SA + 5 VV; sets with these values: 2

# IfcBuildingElementProxy: Tableau commande 2x4 modules saillie:4 BP + 2 SA + 2 VV, Tableau commande 2x4 modules saillie:4 BP + 2 SA + 2 VV:3486290
In: Niveau 0
Type - Material: BETCE-CADRE-BLANC, BETCE-DOIGT-BLANC, BETCE-ENJOLIVEUR-BLANC
Pset_BuildingElementProxyCommon - Reference: 4 BP + 2 SA + 2 VV; sets with these values: 2

# IfcBuildingElementProxy: Tableau commande 2x4 modules saillie:4 BP + 4 SA, Tableau commande 2x4 modules saillie:4 BP + 4 SA:3484206
In: Niveau 0
Type - Material: BETCE-CADRE-BLANC, BETCE-DOIGT-BLANC, BETCE-ENJOLIVEUR-BLANC
Pset_BuildingElementProxyCommon - Reference: 4 BP + 4 SA; sets with these values: 2

# IfcBuildingElementProxy: Tableau commande 2x4 modules saillie:4 BP + 4 VV, Tableau commande 2x4 modules saillie:4 BP + 4 VV:3484836
In: Niveau 0
Type - Material: BETCE-CADRE-BLANC, BETCE-DOIGT-BLANC, BETCE-ENJOLIVEUR-BLANC
Pset_BuildingElementProxyCommon - Reference: 4 BP + 4 VV; sets with these values: 2

# IfcBuildingElementProxy: Tableau commande 2x4 modules saillie:4 SA + 4 VV, Tableau commande 2x4 modules saillie:4 SA + 4 VV:3485586
In: Niveau 0
Type - Material: BETCE-CADRE-BLANC, BETCE-DOIGT-BLANC, BETCE-ENJOLIVEUR-BLANC
Pset_BuildingElementProxyCommon - Reference: 4 SA + 4 VV; sets with these values: 2

# IfcBuildingElementProxy: Tableau commande 2x4 modules saillie:5 BP + 3 SA, Tableau commande 2x4 modules saillie:5 BP + 3 SA:3484338
In: Niveau 0
Type - Material: BETCE-CADRE-BLANC, BETCE-DOIGT-BLANC, BETCE-ENJOLIVEUR-BLANC
Pset_BuildingElementProxyCommon - Reference: 5 BP + 3 SA; sets with these values: 2

# IfcBuildingElementProxy: Tableau commande 2x4 modules saillie:5 BP + 3 VV, Tableau commande 2x4 modules saillie:5 BP + 3 VV:3484896
In: Niveau 0
Type - Material: BETCE-CADRE-BLANC, BETCE-DOIGT-BLANC, BETCE-ENJOLIVEUR-BLANC
Pset_BuildingElementProxyCommon - Reference: 5 BP + 3 VV; sets with these values: 2

# IfcBuildingElementProxy: Tableau commande 2x4 modules saillie:5 SA + 3 VV, Tableau commande 2x4 modules saillie:5 SA + 3 VV:3485694
In: Niveau 0
Type - Material: BETCE-CADRE-BLANC, BETCE-DOIGT-BLANC, BETCE-ENJOLIVEUR-BLANC
Pset_BuildingElementProxyCommon - Reference: 5 SA + 3 VV; sets with these values: 2

# IfcBuildingElementProxy: Tableau commande 2x4 modules saillie:6 BP + 2 SA, Tableau commande 2x4 modules saillie:6 BP + 2 SA:3484420
In: Niveau 0
Type - Material: BETCE-CADRE-BLANC, BETCE-DOIGT-BLANC, BETCE-ENJOLIVEUR-BLANC
Pset_BuildingElementProxyCommon - Reference: 6 BP + 2 SA; sets with these values: 2

# IfcBuildingElementProxy: Tableau commande 2x4 modules saillie:6 BP + 2 VV, Tableau commande 2x4 modules saillie:6 BP + 2 VV:3484972
In: Niveau 0
Type - Material: BETCE-CADRE-BLANC, BETCE-DOIGT-BLANC, BETCE-ENJOLIVEUR-BLANC
Pset_BuildingElementProxyCommon - Reference: 6 BP + 2 VV; sets with these values: 2

# IfcBuildingElementProxy: Tableau commande 2x4 modules saillie:6 SA + 2 VV, Tableau commande 2x4 modules saillie:6 SA + 2 VV:3485798
In: Niveau 0
Type - Material: BETCE-CADRE-BLANC, BETCE-DOIGT-BLANC, BETCE-ENJOLIVEUR-BLANC
Pset_BuildingElementProxyCommon - Reference: 6 SA + 2 VV; sets with these values: 2

# IfcBuildingElementProxy: Tableau commande 2x4 modules saillie:7 BP + 1 SA, Tableau commande 2x4 modules saillie:7 BP + 1 SA:3484490
In: Niveau 0
Type - Material: BETCE-CADRE-BLANC, BETCE-DOIGT-BLANC, BETCE-ENJOLIVEUR-BLANC
Pset_BuildingElementProxyCommon - Reference: 7 BP + 1 SA; sets with these values: 2

# IfcBuildingElementProxy: Tableau commande 2x4 modules saillie:7 BP + 1 VV, Tableau commande 2x4 modules saillie:7 BP + 1 VV:3485168
In: Niveau 0
Type - Material: BETCE-CADRE-BLANC, BETCE-DOIGT-BLANC, BETCE-ENJOLIVEUR-BLANC
Pset_BuildingElementProxyCommon - Reference: 7 BP + 1 VV; sets with these values: 2

# IfcBuildingElementProxy: Tableau commande 2x4 modules saillie:7 SA + 1 VV, Tableau commande 2x4 modules saillie:7 SA + 1 VV:3485896
In: Niveau 0
Type - Material: BETCE-CADRE-BLANC, BETCE-DOIGT-BLANC, BETCE-ENJOLIVEUR-BLANC
Pset_BuildingElementProxyCommon - Reference: 7 SA + 1 VV; sets with these values: 2

# IfcBuildingElementProxy: Tableau commande 2x4 modules saillie:8 BP, Tableau commande 2x4 modules saillie:8 BP:3483216
In: Niveau 0
Type - Material: BETCE-CADRE-BLANC, BETCE-DOIGT-BLANC, BETCE-ENJOLIVEUR-BLANC
Pset_BuildingElementProxyCommon - Reference: 8 BP; sets with these values: 2

# IfcBuildingElementProxy: Tableau commande 2x4 modules saillie:8 SA, Tableau commande 2x4 modules saillie:8 SA:3483664
In: Niveau 0
Type - Material: BETCE-CADRE-BLANC, BETCE-DOIGT-BLANC, BETCE-ENJOLIVEUR-BLANC
Pset_BuildingElementProxyCommon - Reference: 8 SA; sets with these values: 2

# IfcBuildingElementProxy: Tableau commande 2x4 modules saillie:8 VV, Tableau commande 2x4 modules saillie:8 VV:3483740
In: Niveau 0
Type - Material: BETCE-CADRE-BLANC, BETCE-DOIGT-BLANC, BETCE-ENJOLIVEUR-BLANC
Pset_BuildingElementProxyCommon - Reference: 8 VV; sets with these values: 2

# IfcCovering: Plafond composé:Quadrillage 600 x 600 mm (2)
In: Niveau 0
Type - PredefinedType: CEILING
Type - Pset_CoveringCommon - TotalThickness: 0.052 m
Material: Par défaut 0.036 m, Panneau de plafond 600 x 600 0.016 m
Pset_CoveringCommon - Reference: Quadrillage 600 x 600 mm; Finish: Panneau de plafond 600 x 600;
Pset_QuantityTakeOff - Reference: Quadrillage 600 x 600 mm
Name (Plafond composé:Quadrillage 600 x 600 mm:...)
3494377
3745763

# IfcDistributionControlElement: Attente incendie 100e:DAS, Attente incendie 100e:DAS:4059825
In: Niveau 0
Type - Material: <Unnamed>
Pset_QuantityTakeOff - Reference: DAS

# IfcDistributionControlElement: Attente incendie 100e:DESENFUMAGE, Attente incendie 100e:DESENFUMAGE:4059929
In: Niveau 0
Type - Material: <Unnamed>
Pset_QuantityTakeOff - Reference: DESENFUMAGE

# IfcDistributionControlElement: Attente incendie 50e:DAS, Attente incendie 50e:DAS:4059600
In: Niveau 0
Type - Material: <Unnamed>
Pset_QuantityTakeOff - Reference: DAS

# IfcDistributionControlElement: Attente incendie 50e:DESENFUMAGE, Attente incendie 50e:DESENFUMAGE:4059666
In: Niveau 0
Type - Material: <Unnamed>
Pset_QuantityTakeOff - Reference: DESENFUMAGE

# IfcDistributionControlElement: Centrale aspiration:Centrale aspiration, Centrale aspiration:Centrale aspiration:4064362
In: Niveau 0
Type - Material: A-FINITION BOITIER ASPIRATION, A-VOYANT JAUNE ASPIRATION, A-VOYANT ROUGE ASPIRATION, A-VOYANT VERT ASPIRATION
Pset_QuantityTakeOff - Reference: Centrale aspiration
Group: Génie climatique Soufflage 1

# IfcDistributionControlElement: Diffuseur sonore et visuel:Diffuseur sonore et visuel, Diffuseur sonore et visuel:Diffuseur sonore et visuel:4033679
In: Niveau 0
Type - Material: BETCE-DIFFUSEUR VISUEL ET SONORE LED JAUNE, BETCE-DIFFUSEUR VISUEL ET SONORE BLANC, BETCE-DIFFUSEUR VISUEL ET SONORE VITRE
Pset_QuantityTakeOff - Reference: Diffuseur sonore et visuel

# IfcDistributionControlElement: Diffuseur sonore:Diffuseur sonore, Diffuseur sonore:Diffuseur sonore:4042843
In: Niveau 0
Type - Material: BETCE-DIFFUSEUR SONORE-BLANC
Pset_QuantityTakeOff - Reference: Diffuseur sonore

# IfcDistributionControlElement: Diffuseur visuel:Diffuseur visuel, Diffuseur visuel:Diffuseur visuel:4046109
In: Niveau 0
Type - Material: A- PVC - DIFFUSEUR VISUEL - LED - JAUNE, A- PVC - DIFFUSEUR VISUEL - VITRE, A- PVC - DIFFUSEUR VISUEL - BLANC
Pset_QuantityTakeOff - Reference: Diffuseur visuel

# IfcDistributionControlElement: Déclencheur manuel saillie:DM BLANC, Déclencheur manuel saillie:DM BLANC:4029875
In: Niveau 0
Type - Material: BETCE-INCENDIE-VITRE BLANC, BETCE-INCENDIE-DM BLANC
Pset_QuantityTakeOff - Reference: DM BLANC

# IfcDistributionControlElement: Déclencheur manuel saillie:DM BLEU, Déclencheur manuel saillie:DM BLEU:4029785
In: Niveau 0
Type - Material: BETCE-INCENDIE-VITRE BLANC, BETCE-INCENDIE-DM BLEU
Pset_QuantityTakeOff - Reference: DM BLEU

# IfcDistributionControlElement: Déclencheur manuel saillie:DM JAUNE, Déclencheur manuel saillie:DM JAUNE:4029723
In: Niveau 0
Type - Material: BETCE-INCENDIE-VITRE BLANC, BETCE-INCENDIE-DM JAUNE
Pset_QuantityTakeOff - Reference: DM JAUNE

# IfcDistributionControlElement: Déclencheur manuel saillie:DM NOIR, Déclencheur manuel saillie:DM NOIR:4029609
In: Niveau 0
Type - Material: BETCE-INCENDIE-VITRE BLANC, BETCE-INCENDIE-DM NOIR
Pset_QuantityTakeOff - Reference: DM NOIR

# IfcDistributionControlElement: Déclencheur manuel saillie:DM ROUGE, Déclencheur manuel saillie:DM ROUGE:4029373
In: Niveau 0
Type - Material: BETCE-INCENDIE-VITRE BLANC, BETCE-INCENDIE-DM ROUGE
Pset_QuantityTakeOff - Reference: DM ROUGE

# IfcDistributionControlElement: Détecteur de fumée:Détecteur multicapteur, Détecteur de fumée:Détecteur multicapteur:5231830
In: Niveau 0
Type - Material: Color RGB 255-255-255
Pset_QuantityTakeOff - Reference: Détecteur multicapteur

# IfcDistributionControlElement: Détecteur de fumée:Détecteur optique, Détecteur de fumée:Détecteur optique:4011964
In: Niveau 0
Type - Material: Color RGB 255-255-255
Pset_QuantityTakeOff - Reference: Détecteur optique

# IfcDistributionControlElement: Détecteur de fumée:Détecteur thermique, Détecteur de fumée:Détecteur thermique:4017992
In: Niveau 0
Type - Material: Color RGB 255-255-255
Pset_QuantityTakeOff - Reference: Détecteur thermique

# IfcDistributionControlElement: Indicateur d'action:Indicateur d'action, Indicateur d'action:Indicateur d'action:4048048
In: Niveau 0
Type - Material: BETCE-VOYANT-ROUGE, BETCE-ENVELOPPE-BLANC
Pset_QuantityTakeOff - Reference: Indicateur d'action

# IfcDistributionControlElement: Inter à clé encastré:REARMEMENT CLAPET, Inter à clé encastré:REARMEMENT CLAPET:4059414
In: Niveau 0
Type - Material: A-ENJOLIVEUR BLANC, LG - Black, LG - Métal fiche, LG - White
Pset_QuantityTakeOff - Reference: REARMEMENT CLAPET

# IfcDistributionControlElement: Inter à clé encastré:REARMEMENT SKYDOME, Inter à clé encastré:REARMEMENT SKYDOME:4059522
In: Niveau 0
Type - Material: A-ENJOLIVEUR BLANC, LG - Black, LG - Métal fiche, LG - White
Pset_QuantityTakeOff - Reference: REARMEMENT SKYDOME

# IfcDistributionControlElement: Inter à clé encastré:REARMEMENT TRAPPE_VOLET, Inter à clé encastré:REARMEMENT TRAPPE_VOLET:4059529
In: Niveau 0
Type - Material: A-ENJOLIVEUR BLANC, LG - Black, LG - Métal fiche, LG - White
Pset_QuantityTakeOff - Reference: REARMEMENT TRAPPE_VOLET

# IfcDistributionControlElement: Ventouse:Ventouse, Ventouse:Ventouse:4054483
In: Niveau 0
Type - Material: BETCE-INTERIEUR AIMANT-NOIR, BETCE-BOUTON-ROUGE, BETCE-EXTERIEUR AIMANT-CHROME, BETCE-ENVELOPPE-BEIGE
Pset_QuantityTakeOff - Reference: Ventouse

# IfcDistributionPort (754)
Description: Flow; FlowDirection: SOURCEANDSINK
Name
Port_3330831_1
Port_3330832_1
Port_3330833_1
Port_3330834_1
Port_3330834_2
Port_3330835_1
Port_3330835_2
Port_3330836_1
Port_3330836_2
Port_3330837_1
Port_3330837_2
Port_3330838_1
Port_3330838_2
Port_3330839_1
Port_3330839_2
Port_3330844_1
Port_3330847_1
Port_3330848_1
Port_3330849_1
Port_3330850_1
Port_3330851_1
Port_3330852_1
Port_3330853_1
Port_3330854_1
Port_3330855_1
Port_3330867_1
Port_3330869_1
Port_3330869_2
Port_3330870_1
Port_3346601_1
Port_3346927_1
Port_3347101_1
Port_3357135_1
Port_3357379_1
Port_3357553_1
Port_3357773_1
Port_3357899_1
Port_3358027_1
Port_3365082_1
Port_3398740_1
Port_3398969_1
Port_3413893_1
Port_3414011_1
Port_3414143_1
Port_3414243_1
Port_3414325_1
Port_3414375_1
Port_3414495_1
Port_3414607_1
Port_3414757_1
Port_3414851_1
Port_3506113_1
Port_3506451_1
Port_3506462_1
Port_3506600_1
Port_3529603_1
Port_3530009_1
Port_3530017_1
Port_3530025_1
Port_3545034_1
Port_3545483_1
Port_3553720_1
Port_3554039_1
Port_3557888_1
Port_3558010_1
Port_3559803_1
Port_3560243_1
Port_3560383_1
Port_3564143_1
Port_3570143_1
Port_3570247_1
Port_3570343_1
Port_3570447_1
Port_3576240_1
Port_3576512_1
Port_3576580_1
Port_3576718_1
Port_3581269_1
Port_3581483_1
Port_3581579_1
Port_3581651_1
Port_3583584_1
Port_3585801_1
Port_3585883_1
Port_3585891_1
Port_3632311_1
Port_3632639_1
Port_3632827_1
Port_3633167_1
Port_3633327_1
Port_3656159_1
Port_3656253_1
Port_3656383_1
Port_3673031_1
Port_3673153_1
Port_3673241_1
Port_3673353_1
Port_3673449_1
Port_3680745_1
Port_3680845_1
Port_3680963_1
Port_3685381_1
Port_3690249_1
Port_3690371_1
Port_3690519_1
Port_3721877_1
Port_3722263_1
Port_3722389_1
Port_3722491_1
Port_3722617_1
Port_3722703_1
Port_3722799_1
Port_3722949_1
Port_3723111_1
Port_3730585_1
Port_3731126_1
Port_3731238_1
Port_3731320_1
Port_3731462_1
Port_3731564_1
Port_3731682_1
Port_3731790_1
Port_3731898_1
Port_3732062_1
Port_3732238_1
Port_3732346_1
Port_3745585_0
Port_3745587_1
Port_3745585_1
Port_3745586_0
Port_3745587_2
Port_3745586_1
Port_3745589_1
Port_3745588_0
Port_3745589_2
Port_3745588_1
Port_3745591_1
Port_3745590_0
Port_3745591_2
Port_3745590_1
Port_3745593_1
Port_3745592_0
Port_3745593_2
Port_3745592_1
Port_3745595_1
Port_3745594_0
Port_3745595_2
Port_3745594_1
Port_3745597_1
Port_3745596_0
Port_3745601_3
Port_3745596_1
Port_3745603_3
Port_3745597_2
Port_3745600_0
Port_3745598_0
Port_3745601_1
Port_3745598_1
Port_3745599_0
Port_3745599_1
Port_3745601_2
Port_3745600_1
Port_3745601_4
Port_3745602_0
Port_3745603_2
Port_3745602_1
Port_3745605_1
Port_3745603_1
Port_3745604_0
Port_3745604_1
Port_3745605_2
Port_3745606_0
Port_3745608_1
Port_3745606_1
Port_3745607_0
Port_3745608_2
Port_3745607_1
Port_3745610_1
Port_3745609_0
Port_3745610_2
Port_3745609_1
Port_3745612_1
Port_3745611_0
Port_3745612_2
Port_3745611_1
Port_3745614_1
Port_3745613_0
Port_3745614_2
Port_3745613_1
Port_3745616_1
Port_3745615_0
Port_3745616_2
Port_3745615_1
Port_3745618_1
Port_3745617_0
Port_3745622_3
Port_3745617_1
Port_3745624_3
Port_3745618_2
Port_3745621_0
Port_3745619_0
Port_3745622_1
Port_3745619_1
Port_3745620_0
Port_3745620_1
Port_3745622_2
Port_3745621_1
Port_3745622_4
Port_3745623_0
Port_3745624_2
Port_3745623_1
Port_3745626_1
Port_3745624_1
Port_3745625_0
Port_3745625_1
Port_3745626_2
Port_3745629_0
Port_3745631_1
Port_3745629_1
Port_3745630_0
Port_3745631_2
Port_3745630_1
Port_3745633_1
Port_3745632_0
Port_3745633_2
Port_3745632_1
Port_3745635_1
Port_3745634_0
Port_3745635_2
Port_3745634_1
Port_3745637_1
Port_3745636_0
Port_3745637_2
Port_3745636_1
Port_3745639_1
Port_3745638_0
Port_3745639_2
Port_3745638_1
Port_3745641_1
Port_3745640_0
Port_3745645_3
Port_3745640_1
Port_3745647_3
Port_3745641_2
Port_3745644_0
Port_3745642_0
Port_3745645_1
Port_3745642_1
Port_3745643_0
Port_3745643_1
Port_3745645_2
Port_3745644_1
Port_3745645_4
Port_3745646_0
Port_3745647_2
Port_3745646_1
Port_3745649_1
Port_3745647_1
Port_3745648_0
Port_3745648_1
Port_3745649_2
Port_3745651_0
Port_3745653_1
Port_3745651_1
Port_3745652_0
Port_3745653_2
Port_3745652_1
Port_3745655_1
Port_3745654_0
Port_3745655_2
Port_3745654_1
Port_3745657_1
Port_3745656_0
Port_3745657_2
Port_3745656_1
Port_3745659_1
Port_3745658_0
Port_3745659_2
Port_3745658_1
Port_3745661_1
Port_3745660_0
Port_3745661_2
Port_3745660_1
Port_3745663_1
Port_3745662_0
Port_3745667_3
Port_3745662_1
Port_3745669_3
Port_3745663_2
Port_3745666_0
Port_3745664_0
Port_3745667_1
Port_3745664_1
Port_3745665_0
Port_3745665_1
Port_3745667_2
Port_3745666_1
Port_3745667_4
Port_3745668_0
Port_3745669_2
Port_3745668_1
Port_3745671_1
Port_3745669_1
Port_3745670_0
Port_3745670_1
Port_3745671_2
Port_3745675_0
Port_3745675_1
Port_3745677_1
Port_3745676_0
Port_3745677_2
Port_3745676_1
Port_3745679_1
Port_3745678_0
Port_3745679_2
Port_3745678_1
Port_3745681_2
Port_3745680_0
Port_3745681_1
Port_3745680_1
Port_3752997_2
Port_3756315_2
Port_3764059_2
Port_3764155_2
Port_3764259_2
Port_3764377_2
Port_3764463_2
Port_3764539_2
Port_3764741_2
Port_3764872_2
Port_3764956_2
Port_3765030_2
Port_3765112_2
Port_3765176_2
Port_3765222_2
Port_3765284_2
Port_3819586_2
Port_3819668_2
Port_3819814_2
Port_3819902_2
Port_3819940_2
Port_3820030_2
Port_3820094_2
Port_3820204_2
Port_3820268_2
Port_3820328_2
Port_3820378_2
Port_3820458_2
Port_3820532_2
Port_3820628_2
Port_3820691_2
Port_3820913_2
Port_3820987_2
Port_3821031_2
Port_3821117_2
Port_3821167_2
Port_3821225_2
Port_3821305_2
Port_3821385_2
Port_3821455_2
Port_3821519_2
Port_3821597_2
Port_3821673_2
Port_3821861_2
Port_3821965_2
Port_3822077_2
Port_3822133_2
Port_3822183_2
Port_3822249_2
Port_3822303_2
Port_3822351_2
Port_3822429_2
Port_3822505_2
Port_3822561_2
Port_3822651_2
Port_3822775_2
Port_3822825_2
Port_3822917_2
Port_3823025_1
Port_3823026_1
Port_3823027_1
Port_3823028_1
Port_3823029_1
Port_3823030_1
Port_3823031_1
Port_3823032_1
Port_3823033_1
Port_3823034_1
Port_3823035_1
Port_3823036_1
Port_3823037_1
Port_3823038_1
Port_3823039_1
Port_3823040_1
Port_3823041_1
Port_3823042_1
Port_3823043_1
Port_3823044_1
Port_3823045_1
Port_3823046_1
Port_3823047_1
Port_3823048_1
Port_3823049_1
Port_3823050_1
Port_3823051_1
Port_3823052_1
Port_3823053_1
Port_3823054_1
Port_3847412_1
Port_3847472_1
Port_3848919_1
Port_3849035_1
Port_3849077_1
Port_3849157_1
Port_3858523_1
Port_3866377_1
Port_3899268_2
Port_3899923_2
Port_3899994_2
Port_3900092_2
Port_3900166_2
Port_3900232_2
Port_3900298_2
Port_3900346_2
Port_3900402_2
Port_3900450_2
Port_3900518_2
Port_3900584_2
Port_3900668_2
Port_3900822_2
Port_3900910_2
Port_3901002_2
Port_4011964_1
Port_4017992_1
Port_4059414_1
Port_4059522_1
Port_4059529_1
Port_4059600_1
Port_4059666_1
Port_4059825_1
Port_4059929_1
Port_4064362_1 | Group: Génie climatique Soufflage 1
Port_4202468_0 | Group: Génie climatique Soufflage 1
Port_4064362_2 | Group: Génie climatique Soufflage 1
Port_4203012_0 | Group: Génie climatique Soufflage 1
Port_4064362_3 | Group: Génie climatique Soufflage 1
Port_4202402_0 | Group: Génie climatique Soufflage 1
Port_4071387_1
Port_4071387_2
Port_4071500_1
Port_4071500_2
Port_4071507_1
Port_4071507_2
Port_4075321_1
Port_4075321_2
Port_4087308_1
Port_4087595_1
Port_4090489_1
Port_4090489_2
Port_4091872_1
Port_4202402_1 | Group: Génie climatique Soufflage 1
Port_4202468_1 | Group: Génie climatique Soufflage 1
Port_4202490_1 | Group: Génie climatique Soufflage 1
Port_4202481_0 | Group: Génie climatique Soufflage 1
Port_4202490_2 | Group: Génie climatique Soufflage 1
Port_4202481_1 | Group: Génie climatique Soufflage 1
Port_4202521_1 | Group: Génie climatique Soufflage 1
Port_4202511_0 | Group: Génie climatique Soufflage 1
Port_4202521_2 | Group: Génie climatique Soufflage 1
Port_4202511_1 | Group: Génie climatique Soufflage 1
Port_4202549_0 | Group: Génie climatique Soufflage 4
Port_4202945_2 | Group: Génie climatique Soufflage 4
Port_4202549_1 | Group: Génie climatique Soufflage 4
Port_4202570_0 | Group: Génie climatique Soufflage 5
Port_4202609_1 | Group: Génie climatique Soufflage 5
Port_4202570_1 | Group: Génie climatique Soufflage 5
Port_4202589_2 | Group: Génie climatique Soufflage 5
Port_4202579_0 | Group: Génie climatique Soufflage 5
Port_4202589_1 | Group: Génie climatique Soufflage 5
Port_4202579_1 | Group: Génie climatique Soufflage 5
Port_4202601_0 | Group: Génie climatique Soufflage 5
Port_4202609_2 | Group: Génie climatique Soufflage 5
Port_4202601_1 | Group: Génie climatique Soufflage 5
Port_4202635_0 | Group: Génie climatique Soufflage 4
Port_4202947_1 | Group: Génie climatique Soufflage 4
Port_4202635_1 | Group: Génie climatique Soufflage 4
Port_4202637_0 | Group: Génie climatique Soufflage 7
Port_4202645_1 | Group: Génie climatique Soufflage 7
Port_4202637_1 | Group: Génie climatique Soufflage 7
Port_4202641_2 | Group: Génie climatique Soufflage 7
Port_4202639_0 | Group: Génie climatique Soufflage 7
Port_4202641_1 | Group: Génie climatique Soufflage 7
Port_4202639_1 | Group: Génie climatique Soufflage 7
Port_4202643_0 | Group: Génie climatique Soufflage 7
Port_4202645_2 | Group: Génie climatique Soufflage 7
Port_4202643_1 | Group: Génie climatique Soufflage 7
Port_4202879_0 | Group: Génie climatique Soufflage 4
Port_4202945_1 | Group: Génie climatique Soufflage 4
Port_4202879_1 | Group: Génie climatique Soufflage 4
Port_4202947_2 | Group: Génie climatique Soufflage 4
Port_4203012_1 | Group: Génie climatique Soufflage 1
Port_4203433_1 | Group: Génie climatique Soufflage 1
Port_4203025_0 | Group: Génie climatique Soufflage 1
Port_4203433_2 | Group: Génie climatique Soufflage 1
Port_4203025_1 | Group: Génie climatique Soufflage 1
Port_4203435_2 | Group: Génie climatique Soufflage 1
Port_4203343_0 | Group: Génie climatique Soufflage 1
Port_4203435_1 | Group: Génie climatique Soufflage 1
Port_4203343_1 | Group: Génie climatique Soufflage 1
Port_4203345_0 | Group: Génie climatique Soufflage 8
Port_4203371_2 | Group: Génie climatique Soufflage 8
Port_4203345_1 | Group: Génie climatique Soufflage 8
Port_4203347_0 | Group: Génie climatique Soufflage 9
Port_4203355_1 | Group: Génie climatique Soufflage 9
Port_4203347_1 | Group: Génie climatique Soufflage 9
Port_4203351_2 | Group: Génie climatique Soufflage 9
Port_4203349_0 | Group: Génie climatique Soufflage 9
Port_4203351_1 | Group: Génie climatique Soufflage 9
Port_4203349_1 | Group: Génie climatique Soufflage 9
Port_4203353_0 | Group: Génie climatique Soufflage 9
Port_4203355_2 | Group: Génie climatique Soufflage 9
Port_4203353_1 | Group: Génie climatique Soufflage 9
Port_4203357_0 | Group: Génie climatique Soufflage 8
Port_4203373_1 | Group: Génie climatique Soufflage 8
Port_4203357_1 | Group: Génie climatique Soufflage 8
Port_4203359_0 | Group: Génie climatique Soufflage 12
Port_4203367_1 | Group: Génie climatique Soufflage 12
Port_4203359_1 | Group: Génie climatique Soufflage 12
Port_4203363_2 | Group: Génie climatique Soufflage 12
Port_4203361_0 | Group: Génie climatique Soufflage 12
Port_4203363_1 | Group: Génie climatique Soufflage 12
Port_4203361_1 | Group: Génie climatique Soufflage 12
Port_4203365_0 | Group: Génie climatique Soufflage 12
Port_4203367_2 | Group: Génie climatique Soufflage 12
Port_4203365_1 | Group: Génie climatique Soufflage 12
Port_4203369_0 | Group: Génie climatique Soufflage 8
Port_4203371_1 | Group: Génie climatique Soufflage 8
Port_4203369_1 | Group: Génie climatique Soufflage 8
Port_4203373_2 | Group: Génie climatique Soufflage 8
Port_4203506_0 | Group: Génie climatique Soufflage 2
Port_4203506_1 | Group: Génie climatique Soufflage 2
Port_4203557_0 | Group: Génie climatique Soufflage 3
Port_4203557_1 | Group: Génie climatique Soufflage 3
Port_4205913_0
Port_4205913_1
Port_4205926_0
Port_4205926_1
Port_4208709_0
Port_4208709_1
Port_4221181_1
Port_4221182_1
Port_4221183_1
Port_4223120_1
Port_4223128_1
Port_4223136_1
Port_4227278_1
Port_4227286_1
Port_4227294_1
Port_4257692_1
Port_4257699_1
Port_4267560_1
Port_4267690_1
Port_4382763_1
Port_4382859_1
Port_4382979_1
Port_4383095_1
Port_4399463_1
Port_4399695_1
Port_4399769_1
Port_4402927_1
Port_4412169_1
Port_4415379_1
Port_4415447_1
Port_4415525_1
Port_4418678_1
Port_4418870_1
Port_4418932_1
Port_4419034_1
Port_4425468_1
Port_4425746_1
Port_4425830_1
Port_4440135_1
Port_4440235_1
Port_4440297_1
Port_4440375_1
Port_4440417_1
Port_4448483_1
Port_4448583_1
Port_4448655_1
Port_4448725_1
Port_4448783_1
Port_4461397_1
Port_4461497_1
Port_4461595_1
Port_4468843_1
Port_4468927_1
Port_4468957_1
Port_4469027_1
Port_4488466_1
Port_4488660_1
Port_4488764_1
Port_4488874_1
Port_4488932_1
Port_4489018_1
Port_4527114_1
Port_4537468_1
Port_4537518_1
Port_4537566_1
Port_4537632_1
Port_4537684_1
Port_4537720_1
Port_4537782_1
Port_4537844_1
Port_4582846_1
Port_4582964_1
Port_4583016_1
Port_4583098_1
Port_4583148_1
Port_4583192_1
Port_4583274_1
Port_4583340_1
Port_4583398_1
Port_4583454_1
Port_4583504_1
Port_4583590_1
Port_4597341_1
Port_4597485_1
Port_4597599_1
Port_4601629_1
Port_4637624_1
Port_4637788_1
Port_4637868_1
Port_4646416_1
Port_4646642_1
Port_4646722_1
Port_4647020_0
Port_4647020_1
Port_4647022_1
Port_4647021_0
Port_4647022_2
Port_4647021_1
Port_4647024_1
Port_4647023_0
Port_4647024_2
Port_4647023_1
Port_4647026_2
Port_4647025_0
Port_4647026_1
Port_4647025_1
Port_4647034_0
Port_4647034_1
Port_4647036_1
Port_4647035_0
Port_4647036_2
Port_4647035_1
Port_4647038_1
Port_4647037_0
Port_4647038_2
Port_4647037_1
Port_4647040_2
Port_4647039_0
Port_4647040_1
Port_4647039_1
Port_4647048_0
Port_4647048_1
Port_4647050_1
Port_4647049_0
Port_4647050_2
Port_4647049_1
Port_4647052_1
Port_4647051_0
Port_4647052_2
Port_4647051_1
Port_4647054_2
Port_4647053_0
Port_4647054_1
Port_4647053_1
Port_4647383_0
Port_4647383_1
Port_4815699_1
Port_4817656_1
Port_4817803_1
Port_4817851_1
Port_4863526_1
Port_4863674_1
Port_4863776_1
Port_4863844_1
Port_4863922_1
Port_4863998_1
Port_4864106_1
Port_4864210_1
Port_4864274_1
Port_4864326_1
Port_4864370_1
Port_4864414_1
Port_4864462_1
Port_4864554_1
Port_4864604_1
Port_4864670_1
Port_4864718_1
Port_4864768_1
Port_4864820_1
Port_4864896_1
Port_4864942_1
Port_4864988_1
Port_4865034_1
Port_4865098_1
Port_4865144_1
Port_4865304_1
Port_4865360_1
Port_4865424_1
Port_4865510_1
Port_4865580_1
Port_4865660_1
Port_4865702_1
Port_4865734_1
Port_4865820_1
Port_4865894_1
Port_4865970_1
Port_4918342_1
Port_4918342_2
Port_4918420_1
Port_4918420_2
Port_5134745_1
Port_5141581_1
Port_5141752_1
Port_5141893_1
Port_5148815_1
Port_5148930_1
Port_5149087_1
Port_5157137_1
Port_5157296_1
Port_5157393_1
Port_5157482_1
Port_5231830_1
Port_5330841_1
Port_5476180_1
Port_5664248_1
Port_5676465_1
Port_5676513_1
Port_5676583_1
Port_5676653_1
Port_5676711_1
Port_6006362_1
Port_6163932_1
Port_6175141_1
Port_6209736_1
Port_6234142_1
Port_6234843_1
Port_6239915_1
Port_6252051_1
Port_6252059_1
Port_6253580_1
Port_6253986_1

# IfcFlowFitting: Chemin de câbles - Courbure concave:CDC CFA (2)
In: Niveau 0
Type - Material: <Unnamed>
Pset_DistributionFlowElementCommon - Reference: CDC CFA; sets with these values: 2
Name (Chemin de câbles - Courbure concave:CDC CFA:...)
3745593
3745595

# IfcFlowFitting: Chemin de câbles - Courbure concave:CDC CFO (2)
In: Niveau 0
Type - Material: <Unnamed>
Pset_DistributionFlowElementCommon - Reference: CDC CFO; sets with these values: 2
Name (Chemin de câbles - Courbure concave:CDC CFO:...)
3745614
3745616

# IfcFlowFitting: Chemin de câbles - Courbure concave:CDC ENEDIS (2)
In: Niveau 0
Type - Material: <Unnamed>
Pset_DistributionFlowElementCommon - Reference: CDC ENEDIS; sets with these values: 2
Name (Chemin de câbles - Courbure concave:CDC ENEDIS:...)
3745659
3745661

# IfcFlowFitting: Chemin de câbles - Courbure concave:CDC INCENDIE (2)
In: Niveau 0
Type - Material: <Unnamed>
Pset_DistributionFlowElementCommon - Reference: CDC INCENDIE; sets with these values: 2
Name (Chemin de câbles - Courbure concave:CDC INCENDIE:...)
3745637
3745639

# IfcFlowFitting: Chemin de câbles - Courbure concave:GOULOTTE, Chemin de câbles - Courbure concave:GOULOTTE:3745677
In: Niveau 0
Type - Material: <Unnamed>
Pset_DistributionFlowElementCommon - Reference: GOULOTTE; sets with these values: 2

# IfcFlowFitting: Chemin de câbles - Courbure concave:GOULOTTE CONTROLE ACCES, Chemin de câbles - Courbure concave:GOULOTTE CONTROLE ACCES:4647022
In: Niveau 0
Type - Material: <Unnamed>
Pset_DistributionFlowElementCommon - Reference: GOULOTTE CONTROLE ACCES; sets with these values: 2

# IfcFlowFitting: Chemin de câbles - Courbure concave:GOULOTTE INCENDIE, Chemin de câbles - Courbure concave:GOULOTTE INCENDIE:4647036
In: Niveau 0
Type - Material: <Unnamed>
Pset_DistributionFlowElementCommon - Reference: GOULOTTE INCENDIE; sets with these values: 2

# IfcFlowFitting: Chemin de câbles - Courbure concave:GOULOTTE INTRUSION, Chemin de câbles - Courbure concave:GOULOTTE INTRUSION:4647050
In: Niveau 0
Type - Material: <Unnamed>
Pset_DistributionFlowElementCommon - Reference: GOULOTTE INTRUSION; sets with these values: 2

# IfcFlowFitting: Chemin de câbles - Courbure convexe:CDC CFA (2)
In: Niveau 0
Type - Material: <Unnamed>
Pset_DistributionFlowElementCommon - Reference: CDC CFA; sets with these values: 2
Name (Chemin de câbles - Courbure convexe:CDC CFA:...)
3745591
3745597

# IfcFlowFitting: Chemin de câbles - Courbure convexe:CDC CFO (2)
In: Niveau 0
Type - Material: <Unnamed>
Pset_DistributionFlowElementCommon - Reference: CDC CFO; sets with these values: 2
Name (Chemin de câbles - Courbure convexe:CDC CFO:...)
3745612
3745618

# IfcFlowFitting: Chemin de câbles - Courbure convexe:CDC ENEDIS (2)
In: Niveau 0
Type - Material: <Unnamed>
Pset_DistributionFlowElementCommon - Reference: CDC ENEDIS; sets with these values: 2
Name (Chemin de câbles - Courbure convexe:CDC ENEDIS:...)
3745657
3745663

# IfcFlowFitting: Chemin de câbles - Courbure convexe:CDC INCENDIE (2)
In: Niveau 0
Type - Material: <Unnamed>
Pset_DistributionFlowElementCommon - Reference: CDC INCENDIE; sets with these values: 2
Name (Chemin de câbles - Courbure convexe:CDC INCENDIE:...)
3745635
3745641

# IfcFlowFitting: Chemin de câbles - Courbure convexe:GOULOTTE, Chemin de câbles - Courbure convexe:GOULOTTE:3745679
In: Niveau 0
Type - Material: <Unnamed>
Pset_DistributionFlowElementCommon - Reference: GOULOTTE; sets with these values: 2

# IfcFlowFitting: Chemin de câbles - Courbure convexe:GOULOTTE CONTROLE ACCES, Chemin de câbles - Courbure convexe:GOULOTTE CONTROLE ACCES:4647024
In: Niveau 0
Type - Material: <Unnamed>
Pset_DistributionFlowElementCommon - Reference: GOULOTTE CONTROLE ACCES; sets with these values: 2

# IfcFlowFitting: Chemin de câbles - Courbure convexe:GOULOTTE INCENDIE, Chemin de câbles - Courbure convexe:GOULOTTE INCENDIE:4647038
In: Niveau 0
Type - Material: <Unnamed>
Pset_DistributionFlowElementCommon - Reference: GOULOTTE INCENDIE; sets with these values: 2

# IfcFlowFitting: Chemin de câbles - Courbure convexe:GOULOTTE INTRUSION, Chemin de câbles - Courbure convexe:GOULOTTE INTRUSION:4647052
In: Niveau 0
Type - Material: <Unnamed>
Pset_DistributionFlowElementCommon - Reference: GOULOTTE INTRUSION; sets with these values: 2

# IfcFlowFitting: Chemin de câbles - Courbure:CDC CFA, Chemin de câbles - Courbure:CDC CFA:3745587
In: Niveau 0
Type - Material: <Unnamed>
Pset_DistributionFlowElementCommon - Reference: CDC CFA; sets with these values: 2

# IfcFlowFitting: Chemin de câbles - Courbure:CDC CFO, Chemin de câbles - Courbure:CDC CFO:3745608
In: Niveau 0
Type - Material: <Unnamed>
Pset_DistributionFlowElementCommon - Reference: CDC CFO; sets with these values: 2

# IfcFlowFitting: Chemin de câbles - Courbure:CDC ENEDIS, Chemin de câbles - Courbure:CDC ENEDIS:3745653
In: Niveau 0
Type - Material: <Unnamed>
Pset_DistributionFlowElementCommon - Reference: CDC ENEDIS; sets with these values: 2

# IfcFlowFitting: Chemin de câbles - Courbure:CDC INCENDIE, Chemin de câbles - Courbure:CDC INCENDIE:3745631
In: Niveau 0
Type - Material: <Unnamed>
Pset_DistributionFlowElementCommon - Reference: CDC INCENDIE; sets with these values: 2

# IfcFlowFitting: Chemin de câbles - Courbure:GOULOTTE, Chemin de câbles - Courbure:GOULOTTE:3745681
In: Niveau 0
Type - Material: <Unnamed>
Pset_DistributionFlowElementCommon - Reference: GOULOTTE; sets with these values: 2

# IfcFlowFitting: Chemin de câbles - Courbure:GOULOTTE CONTROLE ACCES, Chemin de câbles - Courbure:GOULOTTE CONTROLE ACCES:4647026
In: Niveau 0
Type - Material: <Unnamed>
Pset_DistributionFlowElementCommon - Reference: GOULOTTE CONTROLE ACCES; sets with these values: 2

# IfcFlowFitting: Chemin de câbles - Courbure:GOULOTTE INCENDIE, Chemin de câbles - Courbure:GOULOTTE INCENDIE:4647040
In: Niveau 0
Type - Material: <Unnamed>
Pset_DistributionFlowElementCommon - Reference: GOULOTTE INCENDIE; sets with these values: 2

# IfcFlowFitting: Chemin de câbles - Courbure:GOULOTTE INTRUSION, Chemin de câbles - Courbure:GOULOTTE INTRUSION:4647054
In: Niveau 0
Type - Material: <Unnamed>
Pset_DistributionFlowElementCommon - Reference: GOULOTTE INTRUSION; sets with these values: 2

# IfcFlowFitting: Chemin de câbles - Croix:CDC CFA, Chemin de câbles - Croix:CDC CFA:3745601
In: Niveau 0
Type - Material: <Unnamed>
Pset_DistributionFlowElementCommon - Reference: CDC CFA; sets with these values: 2

# IfcFlowFitting: Chemin de câbles - Croix:CDC CFO, Chemin de câbles - Croix:CDC CFO:3745622
In: Niveau 0
Type - Material: <Unnamed>
Pset_DistributionFlowElementCommon - Reference: CDC CFO; sets with these values: 2

# IfcFlowFitting: Chemin de câbles - Croix:CDC ENEDIS, Chemin de câbles - Croix:CDC ENEDIS:3745667
In: Niveau 0
Type - Material: <Unnamed>
Pset_DistributionFlowElementCommon - Reference: CDC ENEDIS; sets with these values: 2

# IfcFlowFitting: Chemin de câbles - Croix:CDC INCENDIE, Chemin de câbles - Croix:CDC INCENDIE:3745645
In: Niveau 0
Type - Material: <Unnamed>
Pset_DistributionFlowElementCommon - Reference: CDC INCENDIE; sets with these values: 2

# IfcFlowFitting: Chemin de câbles - Réduction:CDC CFA, Chemin de câbles - Réduction:CDC CFA:3745589
In: Niveau 0
Type - Material: <Unnamed>
Pset_DistributionFlowElementCommon - Reference: CDC CFA; sets with these values: 2

# IfcFlowFitting: Chemin de câbles - Réduction:CDC CFO, Chemin de câbles - Réduction:CDC CFO:3745610
In: Niveau 0
Type - Material: <Unnamed>
Pset_DistributionFlowElementCommon - Reference: CDC CFO; sets with these values: 2
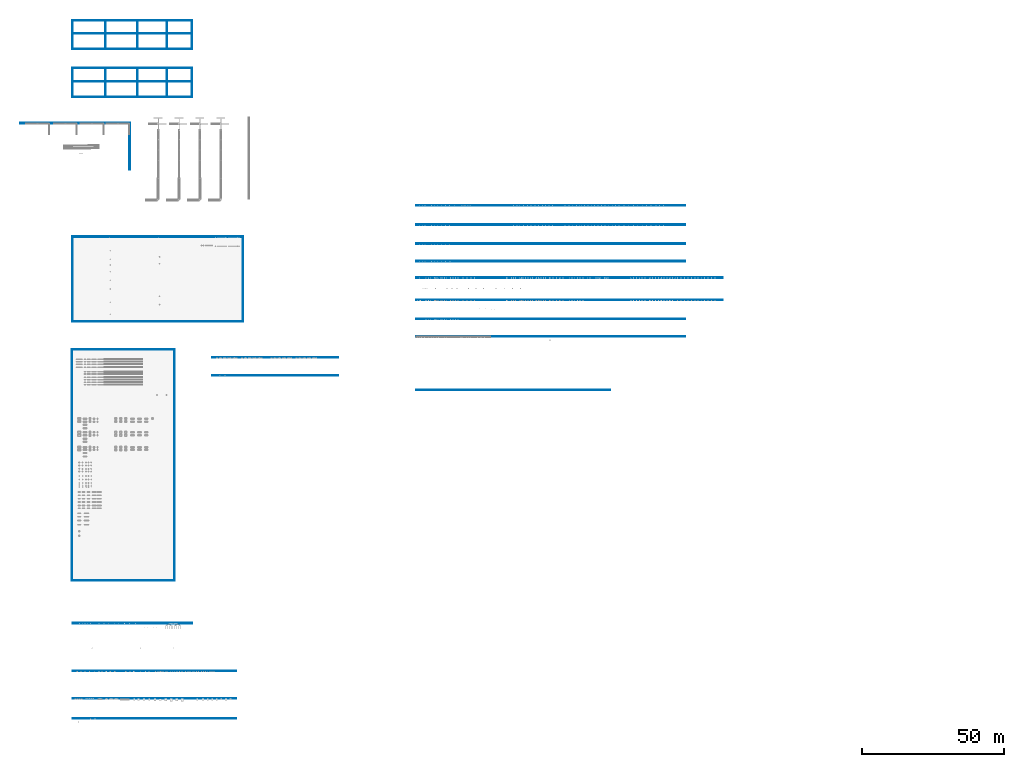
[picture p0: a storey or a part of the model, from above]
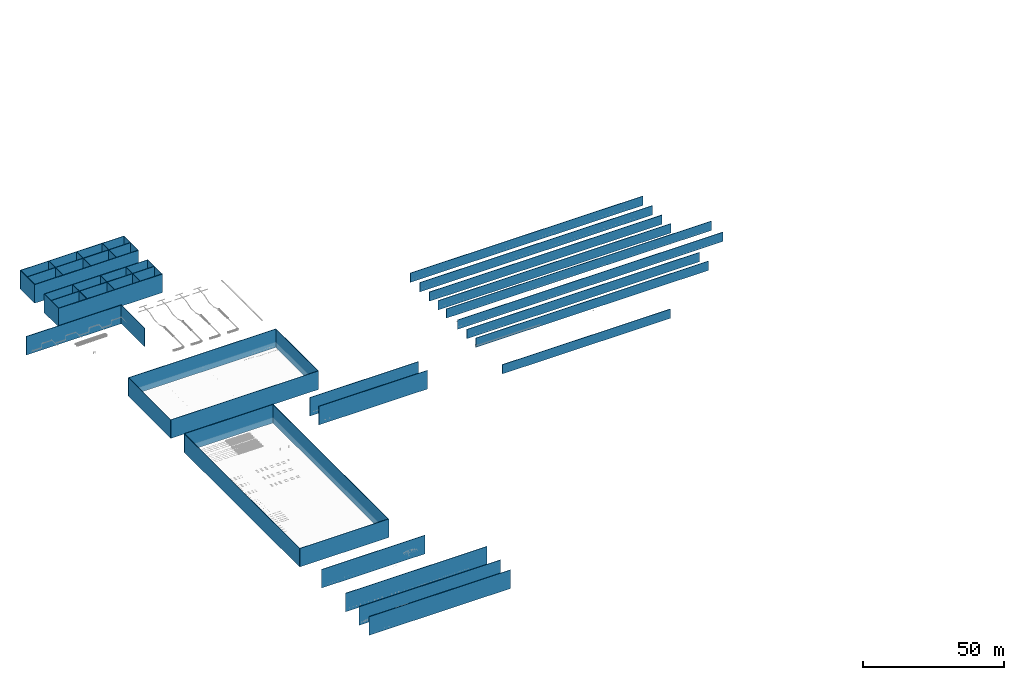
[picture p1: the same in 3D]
Properties of the parts of a building model (IFC2X3), part 4 of 5

# IfcFlowFitting: Chemin de câbles - Réduction:CDC ENEDIS, Chemin de câbles - Réduction:CDC ENEDIS:3745655
In: Niveau 0
Type - Material: <Unnamed>
Pset_DistributionFlowElementCommon - Reference: CDC ENEDIS; sets with these values: 2

# IfcFlowFitting: Chemin de câbles - Réduction:CDC INCENDIE, Chemin de câbles - Réduction:CDC INCENDIE:3745633
In: Niveau 0
Type - Material: <Unnamed>
Pset_DistributionFlowElementCommon - Reference: CDC INCENDIE; sets with these values: 2

# IfcFlowFitting: Chemin de câbles - Té:CDC CFA, Chemin de câbles - Té:CDC CFA:3745603
In: Niveau 0
Type - Material: <Unnamed>
Pset_DistributionFlowElementCommon - Reference: CDC CFA; sets with these values: 2

# IfcFlowFitting: Chemin de câbles - Té:CDC CFO, Chemin de câbles - Té:CDC CFO:3745624
In: Niveau 0
Type - Material: <Unnamed>
Pset_DistributionFlowElementCommon - Reference: CDC CFO; sets with these values: 2

# IfcFlowFitting: Chemin de câbles - Té:CDC ENEDIS, Chemin de câbles - Té:CDC ENEDIS:3745669
In: Niveau 0
Type - Material: <Unnamed>
Pset_DistributionFlowElementCommon - Reference: CDC ENEDIS; sets with these values: 2

# IfcFlowFitting: Chemin de câbles - Té:CDC INCENDIE, Chemin de câbles - Té:CDC INCENDIE:3745647
In: Niveau 0
Type - Material: <Unnamed>
Pset_DistributionFlowElementCommon - Reference: CDC INCENDIE; sets with these values: 2

# IfcFlowFitting: Chemin de câbles - Union:CDC CFA, Chemin de câbles - Union:CDC CFA:3745605
In: Niveau 0
Type - Material: <Unnamed>
Pset_DistributionFlowElementCommon - Reference: CDC CFA; sets with these values: 2

# IfcFlowFitting: Chemin de câbles - Union:CDC CFO, Chemin de câbles - Union:CDC CFO:3745626
In: Niveau 0
Type - Material: <Unnamed>
Pset_DistributionFlowElementCommon - Reference: CDC CFO; sets with these values: 2

# IfcFlowFitting: Chemin de câbles - Union:CDC ENEDIS, Chemin de câbles - Union:CDC ENEDIS:3745671
In: Niveau 0
Type - Material: <Unnamed>
Pset_DistributionFlowElementCommon - Reference: CDC ENEDIS; sets with these values: 2

# IfcFlowFitting: Chemin de câbles - Union:CDC INCENDIE, Chemin de câbles - Union:CDC INCENDIE:3745649
In: Niveau 0
Type - Material: <Unnamed>
Pset_DistributionFlowElementCommon - Reference: CDC INCENDIE; sets with these values: 2

# IfcFlowFitting: Coude circulaire:Tubulure-Aspiration (16)
In: Niveau 0
Type - Material: <Unnamed>
Pset_DistributionFlowElementCommon - Reference: Tubulure-Aspiration; sets with these values: 2
Name (Coude circulaire:Tubulure-Aspiration:...) | Group
4202490 | Génie climatique Soufflage 1
4202521 | Génie climatique Soufflage 1
4202589 | Génie climatique Soufflage 5
4202609 | Génie climatique Soufflage 5
4202641 | Génie climatique Soufflage 7
4202645 | Génie climatique Soufflage 7
4202945 | Génie climatique Soufflage 4
4202947 | Génie climatique Soufflage 4
4203351 | Génie climatique Soufflage 9
4203355 | Génie climatique Soufflage 9
4203363 | Génie climatique Soufflage 12
4203367 | Génie climatique Soufflage 12
4203371 | Génie climatique Soufflage 8
4203373 | Génie climatique Soufflage 8
4203433 | Génie climatique Soufflage 1
4203435 | Génie climatique Soufflage 1

# IfcFlowSegment: Chemin de câbles avec raccords:CDC CFA (12)
In: Niveau 0
Type - PredefinedType: CABLETRAYSEGMENT
Pset_DistributionFlowElementCommon - Reference: CDC CFA; sets with these values: 2
Pset_FlowSegmentDuctSegment - sets with these values: 2
Name (Chemin de câbles avec raccords:CDC CFA:...) | Length (m)
3745585 | 0.1
3745586 | 0.1
3745588 | 0.1
3745590 | 0.15
3745592 | 0.1
3745594 | 0.15
3745596 | 0.1
3745598 | 0.1
3745599 | 0.1
3745600 | 0.1
3745602 | 0.1
3745604 | 0.1

# IfcFlowSegment: Chemin de câbles avec raccords:CDC CFO (12)
In: Niveau 0
Type - PredefinedType: CABLETRAYSEGMENT
Pset_DistributionFlowElementCommon - Reference: CDC CFO; sets with these values: 2
Pset_FlowSegmentDuctSegment - sets with these values: 2
Name (Chemin de câbles avec raccords:CDC CFO:...) | Length (m)
3745606 | 0.1
3745607 | 0.1
3745609 | 0.1
3745611 | 0.15
3745613 | 0.1
3745615 | 0.15
3745617 | 0.1
3745619 | 0.1
3745620 | 0.1
3745621 | 0.1
3745623 | 0.1
3745625 | 0.1

# IfcFlowSegment: Chemin de câbles avec raccords:CDC ENEDIS (12)
In: Niveau 0
Type - PredefinedType: CABLETRAYSEGMENT
Pset_DistributionFlowElementCommon - Reference: CDC ENEDIS; sets with these values: 2
Pset_FlowSegmentDuctSegment - sets with these values: 2
Name (Chemin de câbles avec raccords:CDC ENEDIS:...) | Length (m)
3745651 | 0.1
3745652 | 0.1
3745654 | 0.1
3745656 | 0.15
3745658 | 0.1
3745660 | 0.15
3745662 | 0.1
3745664 | 0.1
3745665 | 0.1
3745666 | 0.1
3745668 | 0.1
3745670 | 0.1

# IfcFlowSegment: Chemin de câbles avec raccords:CDC INCENDIE (12)
In: Niveau 0
Type - PredefinedType: CABLETRAYSEGMENT
Pset_DistributionFlowElementCommon - Reference: CDC INCENDIE; sets with these values: 2
Pset_FlowSegmentDuctSegment - sets with these values: 2
Name (Chemin de câbles avec raccords:CDC INCENDIE:...) | Length (m)
3745629 | 0.1
3745630 | 0.1
3745632 | 0.1
3745634 | 0.15
3745636 | 0.1
3745638 | 0.15
3745640 | 0.1
3745642 | 0.1
3745643 | 0.1
3745644 | 0.1
3745646 | 0.1
3745648 | 0.1

# IfcFlowSegment: Chemin de câbles avec raccords:GAINE A BARRES, Chemin de câbles avec raccords:GAINE A BARRES:4647383
In: Niveau 0
Type - PredefinedType: CABLETRAYSEGMENT
Pset_DistributionFlowElementCommon - Reference: GAINE A BARRES; sets with these values: 2
Pset_FlowSegmentDuctSegment - Length: 0.1 m; sets with these values: 2

# IfcFlowSegment: Chemin de câbles avec raccords:GOULOTTE (5)
In: Niveau 0
Type - PredefinedType: CABLETRAYSEGMENT
Pset_DistributionFlowElementCommon - Reference: GOULOTTE; sets with these values: 2
Pset_FlowSegmentDuctSegment - sets with these values: 2
Name (Chemin de câbles avec raccords:GOULOTTE:...) | Length (m)
3745675 | 0.15
3745676 | 1.225
3745678 | 0.15
3745680 | 0.15
4208709 | 0.18

# IfcFlowSegment: Chemin de câbles avec raccords:GOULOTTE CONTROLE ACCES (4)
In: Niveau 0
Type - PredefinedType: CABLETRAYSEGMENT
Pset_DistributionFlowElementCommon - Reference: GOULOTTE CONTROLE ACCES; sets with these values: 2
Pset_FlowSegmentDuctSegment - sets with these values: 2
Name (Chemin de câbles avec raccords:GOULOTTE CONTROLE ACCES:...) | Length (m)
4647020 | 0.15
4647021 | 1.225
4647023 | 0.15
4647025 | 0.15

# IfcFlowSegment: Chemin de câbles avec raccords:GOULOTTE INCENDIE (4)
In: Niveau 0
Type - PredefinedType: CABLETRAYSEGMENT
Pset_DistributionFlowElementCommon - Reference: GOULOTTE INCENDIE; sets with these values: 2
Pset_FlowSegmentDuctSegment - sets with these values: 2
Name (Chemin de câbles avec raccords:GOULOTTE INCENDIE:...) | Length (m)
4647034 | 0.15
4647035 | 1.225
4647037 | 0.15
4647039 | 0.15

# IfcFlowSegment: Chemin de câbles avec raccords:GOULOTTE INTRUSION (4)
In: Niveau 0
Type - PredefinedType: CABLETRAYSEGMENT
Pset_DistributionFlowElementCommon - Reference: GOULOTTE INTRUSION; sets with these values: 2
Pset_FlowSegmentDuctSegment - sets with these values: 2
Name (Chemin de câbles avec raccords:GOULOTTE INTRUSION:...) | Length (m)
4647048 | 0.15
4647049 | 1.225
4647051 | 0.15
4647053 | 0.15

# IfcFlowSegment: Conduit avec raccords:Traversé dalle-CFA, Conduit avec raccords:Traversé dalle-CFA:4205913
In: Niveau 0
Type - PredefinedType: CONDUITSEGMENT
Pset_DistributionFlowElementCommon - Reference: Traversé dalle-CFA; sets with these values: 2
Pset_FlowSegmentDuctSegment - Length: 0.745 m; sets with these values: 2

# IfcFlowSegment: Conduit avec raccords:Traversé dalle-CFO, Conduit avec raccords:Traversé dalle-CFO:4205926
In: Niveau 0
Type - PredefinedType: CONDUITSEGMENT
Pset_DistributionFlowElementCommon - Reference: Traversé dalle-CFO; sets with these values: 2
Pset_FlowSegmentDuctSegment - Length: 0.745 m; sets with these values: 2

# IfcFlowSegment: Gaine circulaire:Tubulure-Aspiration (24)
In: Niveau 0
Pset_DistributionFlowElementCommon - Reference: Tubulure-Aspiration; sets with these values: 2
Pset_FlowSegmentDuctSegment - sets with these values: 2
Name (Gaine circulaire:Tubulure-Aspiration:...) | Length (m) | Group
4202468 | 2.1 | Génie climatique Soufflage 1
4202481 | 1.492 | Génie climatique Soufflage 1
4202511 | 0.347 | Génie climatique Soufflage 1
4202549 | 0.317 | Génie climatique Soufflage 4
4202570 | 0.714 | Génie climatique Soufflage 5
4202579 | 1.014 | Génie climatique Soufflage 5
4202601 | 1.014 | Génie climatique Soufflage 5
4202635 | 0.317 | Génie climatique Soufflage 4
4202637 | 0.754 | Génie climatique Soufflage 7
4202639 | 1.014 | Génie climatique Soufflage 7
4202643 | 1.014 | Génie climatique Soufflage 7
4202879 | 1.401 | Génie climatique Soufflage 4
4203012 | 2.1 | Génie climatique Soufflage 1
4203025 | 1.516 | Génie climatique Soufflage 1
4203343 | 0.347 | Génie climatique Soufflage 1
4203345 | 0.317 | Génie climatique Soufflage 8
4203347 | 0.714 | Génie climatique Soufflage 9
4203349 | 1.014 | Génie climatique Soufflage 9
4203353 | 1.014 | Génie climatique Soufflage 9
4203357 | 0.317 | Génie climatique Soufflage 8
4203359 | 0.754 | Génie climatique Soufflage 12
4203361 | 1.014 | Génie climatique Soufflage 12
4203365 | 1.014 | Génie climatique Soufflage 12
4203369 | 1.401 | Génie climatique Soufflage 8

# IfcFlowSegment: Gaine circulaire:Tubulure-Retour air, Gaine circulaire:Tubulure-Retour air:4202402
In: Niveau 0
Pset_DistributionFlowElementCommon - Reference: Tubulure-Retour air; sets with these values: 2
Pset_FlowSegmentDuctSegment - Length: 0.25 m; sets with these values: 2
Group: Génie climatique Soufflage 1

# IfcFlowSegment: Gaine flexible circulaire:Fourreau-CFA, Gaine flexible circulaire:Fourreau-CFA:4203506
In: Niveau 0
Type - PredefinedType: FLEXIBLESEGMENT
Pset_DistributionFlowElementCommon - Reference: Fourreau-CFA; sets with these values: 2
Group: Génie climatique Soufflage 2

# IfcFlowSegment: Gaine flexible circulaire:Fourreau-CFO, Gaine flexible circulaire:Fourreau-CFO:4203557
In: Niveau 0
Type - PredefinedType: FLEXIBLESEGMENT
Pset_DistributionFlowElementCommon - Reference: Fourreau-CFO; sets with these values: 2
Group: Génie climatique Soufflage 3

# IfcFlowTerminal: Borne ronde Ø160-ht 468:EXTERIEUR-Borne ronde Ø160-ht 468 (4)
In: Niveau 0
Type - Material: BETCE-BASE-NOIR
Pset_DistributionFlowElementCommon - Reference: EXTERIEUR-Borne ronde Ø160-ht 468; sets with these values: 2
Name (Borne ronde Ø160-ht 468:EXTERIEUR-Borne ronde Ø160-ht 468:...)
6235740
6235816
6235826
6235838

# IfcFlowTerminal: Downlight encastré_saillie:ENCASTRE - Ø150, Downlight encastré_saillie:ENCASTRE - Ø150:3823070
In: Niveau 0
Type - Material: <Unnamed>
Pset_DistributionFlowElementCommon - Reference: ENCASTRE - Ø150; sets with these values: 2

# IfcFlowTerminal: Downlight encastré_saillie:ENCASTRE - Ø165, Downlight encastré_saillie:ENCASTRE - Ø165:3823069
In: Niveau 0
Type - Material: <Unnamed>
Pset_DistributionFlowElementCommon - Reference: ENCASTRE - Ø165; sets with these values: 2

# IfcFlowTerminal: Downlight encastré_saillie:ENCASTRE - Ø175, Downlight encastré_saillie:ENCASTRE - Ø175:3823068
In: Niveau 0
Type - Material: <Unnamed>
Pset_DistributionFlowElementCommon - Reference: ENCASTRE - Ø175; sets with these values: 2

# IfcFlowTerminal: Downlight encastré_saillie:ENCASTRE - Ø205, Downlight encastré_saillie:ENCASTRE - Ø205:3823067
In: Niveau 0
Type - Material: <Unnamed>
Pset_DistributionFlowElementCommon - Reference: ENCASTRE - Ø205; sets with these values: 2

# IfcFlowTerminal: Downlight encastré_saillie:ENCASTRE - Ø225, Downlight encastré_saillie:ENCASTRE - Ø225:3823066
In: Niveau 0
Type - Material: <Unnamed>
Pset_DistributionFlowElementCommon - Reference: ENCASTRE - Ø225; sets with these values: 2

# IfcFlowTerminal: Downlight encastré_saillie:ENCASTRE DALI - Ø150, Downlight encastré_saillie:ENCASTRE DALI - Ø150:3823075
In: Niveau 0
Type - Material: <Unnamed>
Pset_DistributionFlowElementCommon - Reference: ENCASTRE DALI - Ø150; sets with these values: 2

# IfcFlowTerminal: Downlight encastré_saillie:ENCASTRE DALI - Ø165, Downlight encastré_saillie:ENCASTRE DALI - Ø165:3823074
In: Niveau 0
Type - Material: <Unnamed>
Pset_DistributionFlowElementCommon - Reference: ENCASTRE DALI - Ø165; sets with these values: 2

# IfcFlowTerminal: Downlight encastré_saillie:ENCASTRE DALI - Ø175, Downlight encastré_saillie:ENCASTRE DALI - Ø175:3823073
In: Niveau 0
Type - Material: <Unnamed>
Pset_DistributionFlowElementCommon - Reference: ENCASTRE DALI - Ø175; sets with these values: 2

# IfcFlowTerminal: Downlight encastré_saillie:ENCASTRE DALI - Ø205, Downlight encastré_saillie:ENCASTRE DALI - Ø205:3823072
In: Niveau 0
Type - Material: <Unnamed>
Pset_DistributionFlowElementCommon - Reference: ENCASTRE DALI - Ø205; sets with these values: 2

# IfcFlowTerminal: Downlight encastré_saillie:ENCASTRE DALI - Ø225, Downlight encastré_saillie:ENCASTRE DALI - Ø225:3823071
In: Niveau 0
Type - Material: <Unnamed>
Pset_DistributionFlowElementCommon - Reference: ENCASTRE DALI - Ø225; sets with these values: 2

# IfcFlowTerminal: Downlight encastré_saillie:SAILLIE - Ø150, Downlight encastré_saillie:SAILLIE - Ø150:3851519
In: Niveau 0
Type - Material: <Unnamed>
Pset_DistributionFlowElementCommon - Reference: SAILLIE - Ø150; sets with these values: 2

# IfcFlowTerminal: Downlight encastré_saillie:SAILLIE - Ø165, Downlight encastré_saillie:SAILLIE - Ø165:3851655
In: Niveau 0
Type - Material: <Unnamed>
Pset_DistributionFlowElementCommon - Reference: SAILLIE - Ø165; sets with these values: 2

# IfcFlowTerminal: Downlight encastré_saillie:SAILLIE - Ø175, Downlight encastré_saillie:SAILLIE - Ø175:3851705
In: Niveau 0
Type - Material: <Unnamed>
Pset_DistributionFlowElementCommon - Reference: SAILLIE - Ø175; sets with these values: 2

# IfcFlowTerminal: Downlight encastré_saillie:SAILLIE - Ø205, Downlight encastré_saillie:SAILLIE - Ø205:3851765
In: Niveau 0
Type - Material: <Unnamed>
Pset_DistributionFlowElementCommon - Reference: SAILLIE - Ø205; sets with these values: 2

# IfcFlowTerminal: Downlight encastré_saillie:SAILLIE - Ø225, Downlight encastré_saillie:SAILLIE - Ø225:3851811
In: Niveau 0
Type - Material: <Unnamed>
Pset_DistributionFlowElementCommon - Reference: SAILLIE - Ø225; sets with these values: 2

# IfcFlowTerminal: Downlight encastré_saillie:SAILLIE DALI - Ø150, Downlight encastré_saillie:SAILLIE DALI - Ø150:3854129
In: Niveau 0
Type - Material: <Unnamed>
Pset_DistributionFlowElementCommon - Reference: SAILLIE DALI - Ø150; sets with these values: 2

# IfcFlowTerminal: Downlight encastré_saillie:SAILLIE DALI - Ø165, Downlight encastré_saillie:SAILLIE DALI - Ø165:3854247
In: Niveau 0
Type - Material: <Unnamed>
Pset_DistributionFlowElementCommon - Reference: SAILLIE DALI - Ø165; sets with these values: 2

# IfcFlowTerminal: Downlight encastré_saillie:SAILLIE DALI - Ø175, Downlight encastré_saillie:SAILLIE DALI - Ø175:3854379
In: Niveau 0
Type - Material: <Unnamed>
Pset_DistributionFlowElementCommon - Reference: SAILLIE DALI - Ø175; sets with these values: 2

# IfcFlowTerminal: Downlight encastré_saillie:SAILLIE DALI - Ø205, Downlight encastré_saillie:SAILLIE DALI - Ø205:3854471
In: Niveau 0
Type - Material: <Unnamed>
Pset_DistributionFlowElementCommon - Reference: SAILLIE DALI - Ø205; sets with these values: 2

# IfcFlowTerminal: Downlight encastré_saillie:SAILLIE DALI - Ø225, Downlight encastré_saillie:SAILLIE DALI - Ø225:3854511
In: Niveau 0
Type - Material: <Unnamed>
Pset_DistributionFlowElementCommon - Reference: SAILLIE DALI - Ø225; sets with these values: 2

# IfcFlowTerminal: Ecran tactile:Ecran tactil encastré-BLEU, Ecran tactile:Ecran tactil encastré-BLEU:5283898
In: Niveau 0
Type - Material: <Unnamed>, Steel, Black Screen
Type - Pset_ManufacturerOccurrence - BarCode: 8004487964963
Type - Pset_ManufacturerTypeInformation - ModelReference: XTS/5IP; Manufacturer: CAME S.p.A.
Type - Pset_ProductRequirements - Name: XTS 5IP Video Intercom Monitor; Category: Ss_75_40_02_94
Pset_DistributionFlowElementCommon - Reference: Ecran tactil encastré-BLEU; sets with these values: 2

# IfcFlowTerminal: Ecran tactile:Ecran tactil encastré-MAGENTA, Ecran tactile:Ecran tactil encastré-MAGENTA:5284000
In: Niveau 0
Type - Material: <Unnamed>, Steel, Black Screen
Type - Pset_ManufacturerOccurrence - BarCode: 8004487964963
Type - Pset_ManufacturerTypeInformation - ModelReference: XTS/5IP; Manufacturer: CAME S.p.A.
Type - Pset_ProductRequirements - Name: XTS 5IP Video Intercom Monitor; Category: Ss_75_40_02_94
Pset_DistributionFlowElementCommon - Reference: Ecran tactil encastré-MAGENTA; sets with these values: 2

# IfcFlowTerminal: Ecran tactile:Ecran tactil encastré-MARRON, Ecran tactile:Ecran tactil encastré-MARRON:5284047
In: Niveau 0
Type - Material: <Unnamed>, Steel, Black Screen
Type - Pset_ManufacturerOccurrence - BarCode: 8004487964963
Type - Pset_ManufacturerTypeInformation - ModelReference: XTS/5IP; Manufacturer: CAME S.p.A.
Type - Pset_ProductRequirements - Name: XTS 5IP Video Intercom Monitor; Category: Ss_75_40_02_94
Pset_DistributionFlowElementCommon - Reference: Ecran tactil encastré-MARRON; sets with these values: 2

# IfcFlowTerminal: Ecran tactile:Ecran tactil encastré-NOIR, Ecran tactile:Ecran tactil encastré-NOIR:5284077
In: Niveau 0
Type - Material: <Unnamed>, Steel, Black Screen
Type - Pset_ManufacturerOccurrence - BarCode: 8004487964963
Type - Pset_ManufacturerTypeInformation - ModelReference: XTS/5IP; Manufacturer: CAME S.p.A.
Type - Pset_ProductRequirements - Name: XTS 5IP Video Intercom Monitor; Category: Ss_75_40_02_94
Pset_DistributionFlowElementCommon - Reference: Ecran tactil encastré-NOIR; sets with these values: 2

# IfcFlowTerminal: Ecran tactile:Ecran tactil encastré-ORANGE, Ecran tactile:Ecran tactil encastré-ORANGE:5284136
In: Niveau 0
Type - Material: <Unnamed>, Steel, Black Screen
Type - Pset_ManufacturerOccurrence - BarCode: 8004487964963
Type - Pset_ManufacturerTypeInformation - ModelReference: XTS/5IP; Manufacturer: CAME S.p.A.
Type - Pset_ProductRequirements - Name: XTS 5IP Video Intercom Monitor; Category: Ss_75_40_02_94
Pset_DistributionFlowElementCommon - Reference: Ecran tactil encastré-ORANGE; sets with these values: 2

# IfcFlowTerminal: Ecran tactile:Ecran tactil encastré-ROUGE, Ecran tactile:Ecran tactil encastré-ROUGE:5284182
In: Niveau 0
Type - Material: <Unnamed>, Steel, Black Screen
Type - Pset_ManufacturerOccurrence - BarCode: 8004487964963
Type - Pset_ManufacturerTypeInformation - ModelReference: XTS/5IP; Manufacturer: CAME S.p.A.
Type - Pset_ProductRequirements - Name: XTS 5IP Video Intercom Monitor; Category: Ss_75_40_02_94
Pset_DistributionFlowElementCommon - Reference: Ecran tactil encastré-ROUGE; sets with these values: 2

# IfcFlowTerminal: Ecran tactile:Ecran tactil encastré-VERT, Ecran tactile:Ecran tactil encastré-VERT:5284226
In: Niveau 0
Type - Material: <Unnamed>, Steel, Black Screen
Type - Pset_ManufacturerOccurrence - BarCode: 8004487964963
Type - Pset_ManufacturerTypeInformation - ModelReference: XTS/5IP; Manufacturer: CAME S.p.A.
Type - Pset_ProductRequirements - Name: XTS 5IP Video Intercom Monitor; Category: Ss_75_40_02_94
Pset_DistributionFlowElementCommon - Reference: Ecran tactil encastré-VERT; sets with these values: 2

# IfcFlowTerminal: Ecran tactile:Ecran tactil saillie-BLEU, Ecran tactile:Ecran tactil saillie-BLEU:5284284
In: Niveau 0
Type - Material: <Unnamed>, Black Screen
Type - Pset_ManufacturerOccurrence - BarCode: 8004487964963
Type - Pset_ManufacturerTypeInformation - ModelReference: XTS/5IP; Manufacturer: CAME S.p.A.
Type - Pset_ProductRequirements - Name: XTS 5IP Video Intercom Monitor; Category: Ss_75_40_02_94
Pset_DistributionFlowElementCommon - Reference: Ecran tactil saillie-BLEU; sets with these values: 2

# IfcFlowTerminal: Ecran tactile:Ecran tactil saillie-MAGENTA, Ecran tactile:Ecran tactil saillie-MAGENTA:5284384
In: Niveau 0
Type - Material: <Unnamed>, Black Screen
Type - Pset_ManufacturerOccurrence - BarCode: 8004487964963
Type - Pset_ManufacturerTypeInformation - ModelReference: XTS/5IP; Manufacturer: CAME S.p.A.
Type - Pset_ProductRequirements - Name: XTS 5IP Video Intercom Monitor; Category: Ss_75_40_02_94
Pset_DistributionFlowElementCommon - Reference: Ecran tactil saillie-MAGENTA; sets with these values: 2

# IfcFlowTerminal: Ecran tactile:Ecran tactil saillie-MARRON, Ecran tactile:Ecran tactil saillie-MARRON:5284414
In: Niveau 0
Type - Material: <Unnamed>, Black Screen
Type - Pset_ManufacturerOccurrence - BarCode: 8004487964963
Type - Pset_ManufacturerTypeInformation - ModelReference: XTS/5IP; Manufacturer: CAME S.p.A.
Type - Pset_ProductRequirements - Name: XTS 5IP Video Intercom Monitor; Category: Ss_75_40_02_94
Pset_DistributionFlowElementCommon - Reference: Ecran tactil saillie-MARRON; sets with these values: 2

# IfcFlowTerminal: Ecran tactile:Ecran tactil saillie-NOIR, Ecran tactile:Ecran tactil saillie-NOIR:5284445
In: Niveau 0
Type - Material: <Unnamed>, Black Screen
Type - Pset_ManufacturerOccurrence - BarCode: 8004487964963
Type - Pset_ManufacturerTypeInformation - ModelReference: XTS/5IP; Manufacturer: CAME S.p.A.
Type - Pset_ProductRequirements - Name: XTS 5IP Video Intercom Monitor; Category: Ss_75_40_02_94
Pset_DistributionFlowElementCommon - Reference: Ecran tactil saillie-NOIR; sets with these values: 2

# IfcFlowTerminal: Ecran tactile:Ecran tactil saillie-ORANGE, Ecran tactile:Ecran tactil saillie-ORANGE:5284473
In: Niveau 0
Type - Material: <Unnamed>, Black Screen
Type - Pset_ManufacturerOccurrence - BarCode: 8004487964963
Type - Pset_ManufacturerTypeInformation - ModelReference: XTS/5IP; Manufacturer: CAME S.p.A.
Type - Pset_ProductRequirements - Name: XTS 5IP Video Intercom Monitor; Category: Ss_75_40_02_94
Pset_DistributionFlowElementCommon - Reference: Ecran tactil saillie-ORANGE; sets with these values: 2

# IfcFlowTerminal: Ecran tactile:Ecran tactil saillie-ROUGE, Ecran tactile:Ecran tactil saillie-ROUGE:5284501
In: Niveau 0
Type - Material: <Unnamed>, Black Screen
Type - Pset_ManufacturerOccurrence - BarCode: 8004487964963
Type - Pset_ManufacturerTypeInformation - ModelReference: XTS/5IP; Manufacturer: CAME S.p.A.
Type - Pset_ProductRequirements - Name: XTS 5IP Video Intercom Monitor; Category: Ss_75_40_02_94
Pset_DistributionFlowElementCommon - Reference: Ecran tactil saillie-ROUGE; sets with these values: 2

# IfcFlowTerminal: Ecran tactile:Ecran tactil saillie-VERT, Ecran tactile:Ecran tactil saillie-VERT:5284533
In: Niveau 0
Type - Material: <Unnamed>, Black Screen
Type - Pset_ManufacturerOccurrence - BarCode: 8004487964963
Type - Pset_ManufacturerTypeInformation - ModelReference: XTS/5IP; Manufacturer: CAME S.p.A.
Type - Pset_ProductRequirements - Name: XTS 5IP Video Intercom Monitor; Category: Ss_75_40_02_94
Pset_DistributionFlowElementCommon - Reference: Ecran tactil saillie-VERT; sets with these values: 2

# IfcFlowTerminal: Haut parleur encastré:HP, Haut parleur encastré:HP:5330841
In: Niveau 0
Type - PredefinedType: USERDEFINED; Material: Metal_RAL9010, Metal_Grille_RAL9010
Type - Pset_ManufacturerTypeInformation - Manufacturer: Bosch Security Systems
Classification: E1010 Commercial Equipment (Uniformat)
Pset_DistributionFlowElementCommon - Reference: HP; sets with these values: 2

# IfcFlowTerminal: Hublot rond plafond:SAILLIE, Hublot rond plafond:SAILLIE:3924420
In: Niveau 0
Type - Material: <Unnamed>
Pset_DistributionFlowElementCommon - Reference: SAILLIE; sets with these values: 2

# IfcFlowTerminal: Hublot rond plafond:SAILLIE DALI, Hublot rond plafond:SAILLIE DALI:3927256
In: Niveau 0
Type - Material: <Unnamed>
Pset_DistributionFlowElementCommon - Reference: SAILLIE DALI; sets with these values: 2

# IfcFlowTerminal: Hublot rond:SAILLIE, Hublot rond:SAILLIE:3915728
In: Niveau 0
Type - Material: <Unnamed>
Pset_DistributionFlowElementCommon - Reference: SAILLIE; sets with these values: 2

# IfcFlowTerminal: Hublot rond:SAILLIE DALI, Hublot rond:SAILLIE DALI:3919425
In: Niveau 0
Type - Material: <Unnamed>
Pset_DistributionFlowElementCommon - Reference: SAILLIE DALI; sets with these values: 2

# IfcFlowTerminal: Luminaire extérieur-borne en L:EXTERIEUR-Borne en L, Luminaire extérieur-borne en L:EXTERIEUR-Borne en L:3858523
In: Niveau 0
Type - Material: A-PLASTIQUE GRIS, Verre
Pset_DistributionFlowElementCommon - Reference: EXTERIEUR-Borne en L; sets with these values: 2

# IfcFlowTerminal: Luminaire extérieur-borne rectangulaire:EXTERIEUR-borne rectangulaire, Luminaire extérieur-borne rectangulaire:EXTERIEUR-borne rectangulaire:3866377
In: Niveau 0
Type - Material: BEGA_lighting_medium_matt, BEGA_reflector, BEGA_glass_clear, BEGA_finishes_graphite_matt
Type - Pset_ManufacturerTypeInformation - Manufacturer: BEGA
Pset_DistributionFlowElementCommon - Reference: EXTERIEUR-borne rectangulaire; sets with these values: 2

# IfcFlowTerminal: Luminaire étanche saillie_suspendu:LUM ETA-SAILLIE -1200MM, Luminaire étanche saillie_suspendu:LUM ETA-SAILLIE -1200MM:3833475
In: Niveau 0
Type - Material: <Unnamed>, A-FIXATION LUM., A-ENVELOPPE LUM., A-DIFFUSEUR LUM.
Pset_DistributionFlowElementCommon - Reference: LUM ETA-SAILLIE -1200MM; sets with these values: 2

# IfcFlowTerminal: Luminaire étanche saillie_suspendu:LUM ETA-SAILLIE -1500MM, Luminaire étanche saillie_suspendu:LUM ETA-SAILLIE -1500MM:3836040
In: Niveau 0
Type - Material: <Unnamed>, A-FIXATION LUM., A-ENVELOPPE LUM., A-DIFFUSEUR LUM.
Pset_DistributionFlowElementCommon - Reference: LUM ETA-SAILLIE -1500MM; sets with these values: 2

# IfcFlowTerminal: Luminaire étanche saillie_suspendu:LUM ETA-SAILLIE DALI -1200MM, Luminaire étanche saillie_suspendu:LUM ETA-SAILLIE DALI -1200MM:3836090
In: Niveau 0
Type - Material: <Unnamed>, A-FIXATION LUM., A-ENVELOPPE LUM., A-DIFFUSEUR LUM.
Pset_DistributionFlowElementCommon - Reference: LUM ETA-SAILLIE DALI -1200MM; sets with these values: 2

# IfcFlowTerminal: Luminaire étanche saillie_suspendu:LUM ETA-SAILLIE DALI -1500MM, Luminaire étanche saillie_suspendu:LUM ETA-SAILLIE DALI -1500MM:3836170
In: Niveau 0
Type - Material: <Unnamed>, A-FIXATION LUM., A-ENVELOPPE LUM., A-DIFFUSEUR LUM.
Pset_DistributionFlowElementCommon - Reference: LUM ETA-SAILLIE DALI -1500MM; sets with these values: 2

# IfcFlowTerminal: Luminaire étanche saillie_suspendu:LUM ETA-SUSPENDU -1200MM, Luminaire étanche saillie_suspendu:LUM ETA-SUSPENDU -1200MM:3836212
In: Niveau 0
Type - Material: <Unnamed>, A-FIXATION LUM., A-ENVELOPPE LUM., A-DIFFUSEUR LUM.
Pset_DistributionFlowElementCommon - Reference: LUM ETA-SUSPENDU -1200MM; sets with these values: 2

# IfcFlowTerminal: Luminaire étanche saillie_suspendu:LUM ETA-SUSPENDU -1500MM, Luminaire étanche saillie_suspendu:LUM ETA-SUSPENDU -1500MM:3836316
In: Niveau 0
Type - Material: <Unnamed>, A-FIXATION LUM., A-ENVELOPPE LUM., A-DIFFUSEUR LUM.
Pset_DistributionFlowElementCommon - Reference: LUM ETA-SUSPENDU -1500MM; sets with these values: 2

# IfcFlowTerminal: Luminaire étanche saillie_suspendu:LUM ETA-SUSPENDU DALI -1200MM, Luminaire étanche saillie_suspendu:LUM ETA-SUSPENDU DALI -1200MM:3836374
In: Niveau 0
Type - Material: <Unnamed>, A-FIXATION LUM., A-ENVELOPPE LUM., A-DIFFUSEUR LUM.
Pset_DistributionFlowElementCommon - Reference: LUM ETA-SUSPENDU DALI -1200MM; sets with these values: 2

# IfcFlowTerminal: Luminaire étanche saillie_suspendu:LUM ETA-SUSPENDU DALI -1500MM, Luminaire étanche saillie_suspendu:LUM ETA-SUSPENDU DALI -1500MM:3836484
In: Niveau 0
Type - Material: <Unnamed>, A-FIXATION LUM., A-ENVELOPPE LUM., A-DIFFUSEUR LUM.
Pset_DistributionFlowElementCommon - Reference: LUM ETA-SUSPENDU DALI -1500MM; sets with these values: 2

# IfcFlowTerminal: Luminaire étanche tubulaire mural sailli_suspendu_engravure:TUB MU-ENGRAVURE -1000MM, Luminaire étanche tubulaire mural sailli_suspendu_engravure:TUB MU-ENGRAVURE -1000MM:3910048
In: Niveau 0
Type - Material: <Unnamed>, A-EMBOUT, A-LED, A-PVC BLANC, A-PVC TRANSPARENT
Pset_DistributionFlowElementCommon - Reference: TUB MU-ENGRAVURE -1000MM; sets with these values: 2

# IfcFlowTerminal: Luminaire étanche tubulaire mural sailli_suspendu_engravure:TUB MU-ENGRAVURE -1200MM, Luminaire étanche tubulaire mural sailli_suspendu_engravure:TUB MU-ENGRAVURE -1200MM:3910049
In: Niveau 0
Type - Material: <Unnamed>, A-EMBOUT, A-LED, A-PVC BLANC, A-PVC TRANSPARENT
Pset_DistributionFlowElementCommon - Reference: TUB MU-ENGRAVURE -1200MM; sets with these values: 2

# IfcFlowTerminal: Luminaire étanche tubulaire mural sailli_suspendu_engravure:TUB MU-ENGRAVURE -1500MM, Luminaire étanche tubulaire mural sailli_suspendu_engravure:TUB MU-ENGRAVURE -1500MM:3910050
In: Niveau 0
Type - Material: <Unnamed>, A-EMBOUT, A-LED, A-PVC BLANC, A-PVC TRANSPARENT
Pset_DistributionFlowElementCommon - Reference: TUB MU-ENGRAVURE -1500MM; sets with these values: 2

# IfcFlowTerminal: Luminaire étanche tubulaire mural sailli_suspendu_engravure:TUB MU-ENGRAVURE -600MM, Luminaire étanche tubulaire mural sailli_suspendu_engravure:TUB MU-ENGRAVURE -600MM:3910046
In: Niveau 0
Type - Material: <Unnamed>, A-EMBOUT, A-LED, A-PVC BLANC, A-PVC TRANSPARENT
Pset_DistributionFlowElementCommon - Reference: TUB MU-ENGRAVURE -600MM; sets with these values: 2

# IfcFlowTerminal: Luminaire étanche tubulaire mural sailli_suspendu_engravure:TUB MU-ENGRAVURE -900MM, Luminaire étanche tubulaire mural sailli_suspendu_engravure:TUB MU-ENGRAVURE -900MM:3910047
In: Niveau 0
Type - Material: <Unnamed>, A-EMBOUT, A-LED, A-PVC BLANC, A-PVC TRANSPARENT
Pset_DistributionFlowElementCommon - Reference: TUB MU-ENGRAVURE -900MM; sets with these values: 2

# IfcFlowTerminal: Luminaire étanche tubulaire mural sailli_suspendu_engravure:TUB MU-ENGRAVURE DALI -1000MM, Luminaire étanche tubulaire mural sailli_suspendu_engravure:TUB MU-ENGRAVURE DALI -1000MM:3910053
In: Niveau 0
Type - Material: <Unnamed>, A-EMBOUT, A-LED, A-PVC BLANC, A-PVC TRANSPARENT
Pset_DistributionFlowElementCommon - Reference: TUB MU-ENGRAVURE DALI -1000MM; sets with these values: 2

# IfcFlowTerminal: Luminaire étanche tubulaire mural sailli_suspendu_engravure:TUB MU-ENGRAVURE DALI -1200MM, Luminaire étanche tubulaire mural sailli_suspendu_engravure:TUB MU-ENGRAVURE DALI -1200MM:3910054
In: Niveau 0
Type - Material: <Unnamed>, A-EMBOUT, A-LED, A-PVC BLANC, A-PVC TRANSPARENT
Pset_DistributionFlowElementCommon - Reference: TUB MU-ENGRAVURE DALI -1200MM; sets with these values: 2

# IfcFlowTerminal: Luminaire étanche tubulaire mural sailli_suspendu_engravure:TUB MU-ENGRAVURE DALI -1500MM, Luminaire étanche tubulaire mural sailli_suspendu_engravure:TUB MU-ENGRAVURE DALI -1500MM:3910055
In: Niveau 0
Type - Material: <Unnamed>, A-EMBOUT, A-LED, A-PVC BLANC, A-PVC TRANSPARENT
Pset_DistributionFlowElementCommon - Reference: TUB MU-ENGRAVURE DALI -1500MM; sets with these values: 2

# IfcFlowTerminal: Luminaire étanche tubulaire mural sailli_suspendu_engravure:TUB MU-ENGRAVURE DALI -600MM, Luminaire étanche tubulaire mural sailli_suspendu_engravure:TUB MU-ENGRAVURE DALI -600MM:3910051
In: Niveau 0
Type - Material: <Unnamed>, A-EMBOUT, A-LED, A-PVC BLANC, A-PVC TRANSPARENT
Pset_DistributionFlowElementCommon - Reference: TUB MU-ENGRAVURE DALI -600MM; sets with these values: 2

# IfcFlowTerminal: Luminaire étanche tubulaire mural sailli_suspendu_engravure:TUB MU-ENGRAVURE DALI -900MM, Luminaire étanche tubulaire mural sailli_suspendu_engravure:TUB MU-ENGRAVURE DALI -900MM:3910052
In: Niveau 0
Type - Material: <Unnamed>, A-EMBOUT, A-LED, A-PVC BLANC, A-PVC TRANSPARENT
Pset_DistributionFlowElementCommon - Reference: TUB MU-ENGRAVURE DALI -900MM; sets with these values: 2

# IfcFlowTerminal: Luminaire étanche tubulaire mural sailli_suspendu_engravure:TUB MU-SAILLIE -1000MM, Luminaire étanche tubulaire mural sailli_suspendu_engravure:TUB MU-SAILLIE -1000MM:3909213
In: Niveau 0
Type - Material: <Unnamed>, A-EMBOUT, A-LED, A-PVC BLANC, A-PVC TRANSPARENT
Pset_DistributionFlowElementCommon - Reference: TUB MU-SAILLIE -1000MM; sets with these values: 2

# IfcFlowTerminal: Luminaire étanche tubulaire mural sailli_suspendu_engravure:TUB MU-SAILLIE -1200MM, Luminaire étanche tubulaire mural sailli_suspendu_engravure:TUB MU-SAILLIE -1200MM:3909221
In: Niveau 0
Type - Material: <Unnamed>, A-EMBOUT, A-LED, A-PVC BLANC, A-PVC TRANSPARENT
Pset_DistributionFlowElementCommon - Reference: TUB MU-SAILLIE -1200MM; sets with these values: 2

# IfcFlowTerminal: Luminaire étanche tubulaire mural sailli_suspendu_engravure:TUB MU-SAILLIE -1500MM, Luminaire étanche tubulaire mural sailli_suspendu_engravure:TUB MU-SAILLIE -1500MM:3909229
In: Niveau 0
Type - Material: <Unnamed>, A-EMBOUT, A-LED, A-PVC BLANC, A-PVC TRANSPARENT
Pset_DistributionFlowElementCommon - Reference: TUB MU-SAILLIE -1500MM; sets with these values: 2

# IfcFlowTerminal: Luminaire étanche tubulaire mural sailli_suspendu_engravure:TUB MU-SAILLIE -600MM, Luminaire étanche tubulaire mural sailli_suspendu_engravure:TUB MU-SAILLIE -600MM:3903454
In: Niveau 0
Type - Material: <Unnamed>, A-EMBOUT, A-LED, A-PVC BLANC, A-PVC TRANSPARENT
Pset_DistributionFlowElementCommon - Reference: TUB MU-SAILLIE -600MM; sets with these values: 2

# IfcFlowTerminal: Luminaire étanche tubulaire mural sailli_suspendu_engravure:TUB MU-SAILLIE -900MM, Luminaire étanche tubulaire mural sailli_suspendu_engravure:TUB MU-SAILLIE -900MM:3909205
In: Niveau 0
Type - Material: <Unnamed>, A-EMBOUT, A-LED, A-PVC BLANC, A-PVC TRANSPARENT
Pset_DistributionFlowElementCommon - Reference: TUB MU-SAILLIE -900MM; sets with these values: 2

# IfcFlowTerminal: Luminaire étanche tubulaire mural sailli_suspendu_engravure:TUB MU-SAILLIE DALI -1000MM (2)
In: Niveau 0
Type - Material: <Unnamed>, A-EMBOUT, A-LED, A-PVC BLANC, A-PVC TRANSPARENT
Pset_DistributionFlowElementCommon - Reference: TUB MU-SAILLIE DALI -1000MM; sets with these values: 2
Name (Luminaire étanche tubulaire mural sailli_suspendu_engravure:TUB MU-SAILLIE DALI -1000MM:...)
3909688
3909689

# IfcFlowTerminal: Luminaire étanche tubulaire mural sailli_suspendu_engravure:TUB MU-SAILLIE DALI -1200MM, Luminaire étanche tubulaire mural sailli_suspendu_engravure:TUB MU-SAILLIE DALI -1200MM:3909690
In: Niveau 0
Type - Material: <Unnamed>, A-EMBOUT, A-LED, A-PVC BLANC, A-PVC TRANSPARENT
Pset_DistributionFlowElementCommon - Reference: TUB MU-SAILLIE DALI -1200MM; sets with these values: 2

# IfcFlowTerminal: Luminaire étanche tubulaire mural sailli_suspendu_engravure:TUB MU-SAILLIE DALI -1500MM, Luminaire étanche tubulaire mural sailli_suspendu_engravure:TUB MU-SAILLIE DALI -1500MM:3909691
In: Niveau 0
Type - Material: <Unnamed>, A-EMBOUT, A-LED, A-PVC BLANC, A-PVC TRANSPARENT
Pset_DistributionFlowElementCommon - Reference: TUB MU-SAILLIE DALI -1500MM; sets with these values: 2

# IfcFlowTerminal: Luminaire étanche tubulaire mural sailli_suspendu_engravure:TUB MU-SAILLIE DALI -600MM, Luminaire étanche tubulaire mural sailli_suspendu_engravure:TUB MU-SAILLIE DALI -600MM:3909687
In: Niveau 0
Type - Material: <Unnamed>, A-EMBOUT, A-LED, A-PVC BLANC, A-PVC TRANSPARENT
Pset_DistributionFlowElementCommon - Reference: TUB MU-SAILLIE DALI -600MM; sets with these values: 2

# IfcFlowTerminal: Luminaire étanche tubulaire sailli_suspendu_engravure:TUB-ENGRAVURE -1000MM, Luminaire étanche tubulaire sailli_suspendu_engravure:TUB-ENGRAVURE -1000MM:3829444
In: Niveau 0
Type - Material: <Unnamed>, A-EMBOUT, A-LED, A-PVC BLANC, A-PVC TRANSPARENT
Pset_DistributionFlowElementCommon - Reference: TUB-ENGRAVURE -1000MM; sets with these values: 2

# IfcFlowTerminal: Luminaire étanche tubulaire sailli_suspendu_engravure:TUB-ENGRAVURE -1200MM, Luminaire étanche tubulaire sailli_suspendu_engravure:TUB-ENGRAVURE -1200MM:3827271
In: Niveau 0
Type - Material: <Unnamed>, A-EMBOUT, A-LED, A-PVC BLANC, A-PVC TRANSPARENT
Pset_DistributionFlowElementCommon - Reference: TUB-ENGRAVURE -1200MM; sets with these values: 2

# IfcFlowTerminal: Luminaire étanche tubulaire sailli_suspendu_engravure:TUB-ENGRAVURE -1500MM, Luminaire étanche tubulaire sailli_suspendu_engravure:TUB-ENGRAVURE -1500MM:3827345
In: Niveau 0
Type - Material: <Unnamed>, A-EMBOUT, A-LED, A-PVC BLANC, A-PVC TRANSPARENT
Pset_DistributionFlowElementCommon - Reference: TUB-ENGRAVURE -1500MM; sets with these values: 2

# IfcFlowTerminal: Luminaire étanche tubulaire sailli_suspendu_engravure:TUB-ENGRAVURE -600MM, Luminaire étanche tubulaire sailli_suspendu_engravure:TUB-ENGRAVURE -600MM:3827125
In: Niveau 0
Type - Material: <Unnamed>, A-EMBOUT, A-LED, A-PVC BLANC, A-PVC TRANSPARENT
Pset_DistributionFlowElementCommon - Reference: TUB-ENGRAVURE -600MM; sets with these values: 2

# IfcFlowTerminal: Luminaire étanche tubulaire sailli_suspendu_engravure:TUB-ENGRAVURE -900MM, Luminaire étanche tubulaire sailli_suspendu_engravure:TUB-ENGRAVURE -900MM:3827195
In: Niveau 0
Type - Material: <Unnamed>, A-EMBOUT, A-LED, A-PVC BLANC, A-PVC TRANSPARENT
Pset_DistributionFlowElementCommon - Reference: TUB-ENGRAVURE -900MM; sets with these values: 2

# IfcFlowTerminal: Luminaire étanche tubulaire sailli_suspendu_engravure:TUB-ENGRAVURE DALI -1000MM, Luminaire étanche tubulaire sailli_suspendu_engravure:TUB-ENGRAVURE DALI -1000MM:3827637
In: Niveau 0
Type - Material: <Unnamed>, A-EMBOUT, A-LED, A-PVC BLANC, A-PVC TRANSPARENT
Pset_DistributionFlowElementCommon - Reference: TUB-ENGRAVURE DALI -1000MM; sets with these values: 2

# IfcFlowTerminal: Luminaire étanche tubulaire sailli_suspendu_engravure:TUB-ENGRAVURE DALI -1200MM, Luminaire étanche tubulaire sailli_suspendu_engravure:TUB-ENGRAVURE DALI -1200MM:3827745
In: Niveau 0
Type - Material: <Unnamed>, A-EMBOUT, A-LED, A-PVC BLANC, A-PVC TRANSPARENT
Pset_DistributionFlowElementCommon - Reference: TUB-ENGRAVURE DALI -1200MM; sets with these values: 2

# IfcFlowTerminal: Luminaire étanche tubulaire sailli_suspendu_engravure:TUB-ENGRAVURE DALI -1500MM, Luminaire étanche tubulaire sailli_suspendu_engravure:TUB-ENGRAVURE DALI -1500MM:3827825
In: Niveau 0
Type - Material: <Unnamed>, A-EMBOUT, A-LED, A-PVC BLANC, A-PVC TRANSPARENT
Pset_DistributionFlowElementCommon - Reference: TUB-ENGRAVURE DALI -1500MM; sets with these values: 2

# IfcFlowTerminal: Luminaire étanche tubulaire sailli_suspendu_engravure:TUB-ENGRAVURE DALI -600MM, Luminaire étanche tubulaire sailli_suspendu_engravure:TUB-ENGRAVURE DALI -600MM:3827439
In: Niveau 0
Type - Material: <Unnamed>, A-EMBOUT, A-LED, A-PVC BLANC, A-PVC TRANSPARENT
Pset_DistributionFlowElementCommon - Reference: TUB-ENGRAVURE DALI -600MM; sets with these values: 2

# IfcFlowTerminal: Luminaire étanche tubulaire sailli_suspendu_engravure:TUB-ENGRAVURE DALI -900MM, Luminaire étanche tubulaire sailli_suspendu_engravure:TUB-ENGRAVURE DALI -900MM:3827527
In: Niveau 0
Type - Material: <Unnamed>, A-EMBOUT, A-LED, A-PVC BLANC, A-PVC TRANSPARENT
Pset_DistributionFlowElementCommon - Reference: TUB-ENGRAVURE DALI -900MM; sets with these values: 2

# IfcFlowTerminal: Luminaire étanche tubulaire sailli_suspendu_engravure:TUB-SAILLIE -1000MM, Luminaire étanche tubulaire sailli_suspendu_engravure:TUB-SAILLIE -1000MM:3825337
In: Niveau 0
Type - Material: <Unnamed>, A-EMBOUT, A-LED, A-PVC BLANC, A-PVC TRANSPARENT
Pset_DistributionFlowElementCommon - Reference: TUB-SAILLIE -1000MM; sets with these values: 2

# IfcFlowTerminal: Luminaire étanche tubulaire sailli_suspendu_engravure:TUB-SAILLIE -1200MM, Luminaire étanche tubulaire sailli_suspendu_engravure:TUB-SAILLIE -1200MM:3825481
In: Niveau 0
Type - Material: <Unnamed>, A-EMBOUT, A-LED, A-PVC BLANC, A-PVC TRANSPARENT
Pset_DistributionFlowElementCommon - Reference: TUB-SAILLIE -1200MM; sets with these values: 2

# IfcFlowTerminal: Luminaire étanche tubulaire sailli_suspendu_engravure:TUB-SAILLIE -1500MM, Luminaire étanche tubulaire sailli_suspendu_engravure:TUB-SAILLIE -1500MM:3825559
In: Niveau 0
Type - Material: <Unnamed>, A-EMBOUT, A-LED, A-PVC BLANC, A-PVC TRANSPARENT
Pset_DistributionFlowElementCommon - Reference: TUB-SAILLIE -1500MM; sets with these values: 2

# IfcFlowTerminal: Luminaire étanche tubulaire sailli_suspendu_engravure:TUB-SAILLIE -600MM, Luminaire étanche tubulaire sailli_suspendu_engravure:TUB-SAILLIE -600MM:3824711
In: Niveau 0
Type - Material: <Unnamed>, A-EMBOUT, A-LED, A-PVC BLANC, A-PVC TRANSPARENT
Pset_DistributionFlowElementCommon - Reference: TUB-SAILLIE -600MM; sets with these values: 2

# IfcFlowTerminal: Luminaire étanche tubulaire sailli_suspendu_engravure:TUB-SAILLIE -900MM, Luminaire étanche tubulaire sailli_suspendu_engravure:TUB-SAILLIE -900MM:3825179
In: Niveau 0
Type - Material: <Unnamed>, A-EMBOUT, A-LED, A-PVC BLANC, A-PVC TRANSPARENT
Pset_DistributionFlowElementCommon - Reference: TUB-SAILLIE -900MM; sets with these values: 2

# IfcFlowTerminal: Luminaire étanche tubulaire sailli_suspendu_engravure:TUB-SAILLIE DALI -1000MM, Luminaire étanche tubulaire sailli_suspendu_engravure:TUB-SAILLIE DALI -1000MM:3825809
In: Niveau 0
Type - Material: <Unnamed>, A-EMBOUT, A-LED, A-PVC BLANC, A-PVC TRANSPARENT
Pset_DistributionFlowElementCommon - Reference: TUB-SAILLIE DALI -1000MM; sets with these values: 2

# IfcFlowTerminal: Luminaire étanche tubulaire sailli_suspendu_engravure:TUB-SAILLIE DALI -1200MM, Luminaire étanche tubulaire sailli_suspendu_engravure:TUB-SAILLIE DALI -1200MM:3825943
In: Niveau 0
Type - Material: <Unnamed>, A-EMBOUT, A-LED, A-PVC BLANC, A-PVC TRANSPARENT
Pset_DistributionFlowElementCommon - Reference: TUB-SAILLIE DALI -1200MM; sets with these values: 2

# IfcFlowTerminal: Luminaire étanche tubulaire sailli_suspendu_engravure:TUB-SAILLIE DALI -1500MM, Luminaire étanche tubulaire sailli_suspendu_engravure:TUB-SAILLIE DALI -1500MM:3826009
In: Niveau 0
Type - Material: <Unnamed>, A-EMBOUT, A-LED, A-PVC BLANC, A-PVC TRANSPARENT
Pset_DistributionFlowElementCommon - Reference: TUB-SAILLIE DALI -1500MM; sets with these values: 2

# IfcFlowTerminal: Luminaire étanche tubulaire sailli_suspendu_engravure:TUB-SAILLIE DALI -600MM, Luminaire étanche tubulaire sailli_suspendu_engravure:TUB-SAILLIE DALI -600MM:3825625
In: Niveau 0
Type - Material: <Unnamed>, A-EMBOUT, A-LED, A-PVC BLANC, A-PVC TRANSPARENT
Pset_DistributionFlowElementCommon - Reference: TUB-SAILLIE DALI -600MM; sets with these values: 2

# IfcFlowTerminal: Luminaire étanche tubulaire sailli_suspendu_engravure:TUB-SAILLIE DALI -900MM, Luminaire étanche tubulaire sailli_suspendu_engravure:TUB-SAILLIE DALI -900MM:3825697
In: Niveau 0
Type - Material: <Unnamed>, A-EMBOUT, A-LED, A-PVC BLANC, A-PVC TRANSPARENT
Pset_DistributionFlowElementCommon - Reference: TUB-SAILLIE DALI -900MM; sets with these values: 2

# IfcFlowTerminal: Luminaire étanche tubulaire sailli_suspendu_engravure:TUB-SUSPENDU -1000MM, Luminaire étanche tubulaire sailli_suspendu_engravure:TUB-SUSPENDU -1000MM:3826333
In: Niveau 0
Type - Material: <Unnamed>, A-EMBOUT, A-LED, A-PVC BLANC, A-PVC TRANSPARENT
Pset_DistributionFlowElementCommon - Reference: TUB-SUSPENDU -1000MM; sets with these values: 2

# IfcFlowTerminal: Luminaire étanche tubulaire sailli_suspendu_engravure:TUB-SUSPENDU -1200MM, Luminaire étanche tubulaire sailli_suspendu_engravure:TUB-SUSPENDU -1200MM:3826393
In: Niveau 0
Type - Material: <Unnamed>, A-EMBOUT, A-LED, A-PVC BLANC, A-PVC TRANSPARENT
Pset_DistributionFlowElementCommon - Reference: TUB-SUSPENDU -1200MM; sets with these values: 2

# IfcFlowTerminal: Luminaire étanche tubulaire sailli_suspendu_engravure:TUB-SUSPENDU -1500MM, Luminaire étanche tubulaire sailli_suspendu_engravure:TUB-SUSPENDU -1500MM:3826521
In: Niveau 0
Type - Material: <Unnamed>, A-EMBOUT, A-LED, A-PVC BLANC, A-PVC TRANSPARENT
Pset_DistributionFlowElementCommon - Reference: TUB-SUSPENDU -1500MM; sets with these values: 2

# IfcFlowTerminal: Luminaire étanche tubulaire sailli_suspendu_engravure:TUB-SUSPENDU -600MM, Luminaire étanche tubulaire sailli_suspendu_engravure:TUB-SUSPENDU -600MM:3826127
In: Niveau 0
Type - Material: <Unnamed>, A-EMBOUT, A-LED, A-PVC BLANC, A-PVC TRANSPARENT
Pset_DistributionFlowElementCommon - Reference: TUB-SUSPENDU -600MM; sets with these values: 2

# IfcFlowTerminal: Luminaire étanche tubulaire sailli_suspendu_engravure:TUB-SUSPENDU -900MM, Luminaire étanche tubulaire sailli_suspendu_engravure:TUB-SUSPENDU -900MM:3826247
In: Niveau 0
Type - Material: <Unnamed>, A-EMBOUT, A-LED, A-PVC BLANC, A-PVC TRANSPARENT
Pset_DistributionFlowElementCommon - Reference: TUB-SUSPENDU -900MM; sets with these values: 2

# IfcFlowTerminal: Luminaire étanche tubulaire sailli_suspendu_engravure:TUB-SUSPENDU DALI -1000MM, Luminaire étanche tubulaire sailli_suspendu_engravure:TUB-SUSPENDU DALI -1000MM:3826829
In: Niveau 0
Type - Material: <Unnamed>, A-EMBOUT, A-LED, A-PVC BLANC, A-PVC TRANSPARENT
Pset_DistributionFlowElementCommon - Reference: TUB-SUSPENDU DALI -1000MM; sets with these values: 2

# IfcFlowTerminal: Luminaire étanche tubulaire sailli_suspendu_engravure:TUB-SUSPENDU DALI -1200MM, Luminaire étanche tubulaire sailli_suspendu_engravure:TUB-SUSPENDU DALI -1200MM:3826937
In: Niveau 0
Type - Material: <Unnamed>, A-EMBOUT, A-LED, A-PVC BLANC, A-PVC TRANSPARENT
Pset_DistributionFlowElementCommon - Reference: TUB-SUSPENDU DALI -1200MM; sets with these values: 2

# IfcFlowTerminal: Luminaire étanche tubulaire sailli_suspendu_engravure:TUB-SUSPENDU DALI -1500MM, Luminaire étanche tubulaire sailli_suspendu_engravure:TUB-SUSPENDU DALI -1500MM:3827023
In: Niveau 0
Type - Material: <Unnamed>, A-EMBOUT, A-LED, A-PVC BLANC, A-PVC TRANSPARENT
Pset_DistributionFlowElementCommon - Reference: TUB-SUSPENDU DALI -1500MM; sets with these values: 2

# IfcFlowTerminal: Luminaire étanche tubulaire sailli_suspendu_engravure:TUB-SUSPENDU DALI -600MM, Luminaire étanche tubulaire sailli_suspendu_engravure:TUB-SUSPENDU DALI -600MM:3826577
In: Niveau 0
Type - Material: <Unnamed>, A-EMBOUT, A-LED, A-PVC BLANC, A-PVC TRANSPARENT
Pset_DistributionFlowElementCommon - Reference: TUB-SUSPENDU DALI -600MM; sets with these values: 2

# IfcFlowTerminal: Luminaire étanche tubulaire sailli_suspendu_engravure:TUB-SUSPENDU DALI -900MM, Luminaire étanche tubulaire sailli_suspendu_engravure:TUB-SUSPENDU DALI -900MM:3826685
In: Niveau 0
Type - Material: <Unnamed>, A-EMBOUT, A-LED, A-PVC BLANC, A-PVC TRANSPARENT
Pset_DistributionFlowElementCommon - Reference: TUB-SUSPENDU DALI -900MM; sets with these values: 2

# IfcFlowTerminal: Pavé LED encastré_saillie_suspendu:ENCASTRE - 1200X300, Pavé LED encastré_saillie_suspendu:ENCASTRE - 1200X300:3823026
In: Niveau 0
Type - Material: <Unnamed>
Pset_DistributionFlowElementCommon - Reference: ENCASTRE - 1200X300; sets with these values: 2

# IfcFlowTerminal: Pavé LED encastré_saillie_suspendu:ENCASTRE - 1200X600, Pavé LED encastré_saillie_suspendu:ENCASTRE - 1200X600:3823025
In: Niveau 0
Type - Material: <Unnamed>
Pset_DistributionFlowElementCommon - Reference: ENCASTRE - 1200X600; sets with these values: 2

# IfcFlowTerminal: Pavé LED encastré_saillie_suspendu:ENCASTRE - 300X300, Pavé LED encastré_saillie_suspendu:ENCASTRE - 300X300:3823029
In: Niveau 0
Type - Material: <Unnamed>
Pset_DistributionFlowElementCommon - Reference: ENCASTRE - 300X300; sets with these values: 2

# IfcFlowTerminal: Pavé LED encastré_saillie_suspendu:ENCASTRE - 400X400, Pavé LED encastré_saillie_suspendu:ENCASTRE - 400X400:3823028
In: Niveau 0
Type - Material: <Unnamed>
Pset_DistributionFlowElementCommon - Reference: ENCASTRE - 400X400; sets with these values: 2

# IfcFlowTerminal: Pavé LED encastré_saillie_suspendu:ENCASTRE - 600X600, Pavé LED encastré_saillie_suspendu:ENCASTRE - 600X600:3823027
In: Niveau 0
Type - Material: <Unnamed>
Pset_DistributionFlowElementCommon - Reference: ENCASTRE - 600X600; sets with these values: 2

# IfcFlowTerminal: Pavé LED encastré_saillie_suspendu:ENCASTRE ASYMETRIQUE - 1200X300, Pavé LED encastré_saillie_suspendu:ENCASTRE ASYMETRIQUE - 1200X300:3847412
In: Niveau 0
Type - Material: <Unnamed>
Pset_DistributionFlowElementCommon - Reference: ENCASTRE ASYMETRIQUE - 1200X300; sets with these values: 2

# IfcFlowTerminal: Pavé LED encastré_saillie_suspendu:ENCASTRE ASYMETRIQUE DALI - 1200X300, Pavé LED encastré_saillie_suspendu:ENCASTRE ASYMETRIQUE DALI - 1200X300:3847472
In: Niveau 0
Type - Material: <Unnamed>
Pset_DistributionFlowElementCommon - Reference: ENCASTRE ASYMETRIQUE DALI - 1200X300; sets with these values: 2

# IfcFlowTerminal: Pavé LED encastré_saillie_suspendu:ENCASTRE DALI - 1200X300, Pavé LED encastré_saillie_suspendu:ENCASTRE DALI - 1200X300:3823033
In: Niveau 0
Type - Material: <Unnamed>
Pset_DistributionFlowElementCommon - Reference: ENCASTRE DALI - 1200X300; sets with these values: 2

# IfcFlowTerminal: Pavé LED encastré_saillie_suspendu:ENCASTRE DALI - 1200X600, Pavé LED encastré_saillie_suspendu:ENCASTRE DALI - 1200X600:3823034
In: Niveau 0
Type - Material: <Unnamed>
Pset_DistributionFlowElementCommon - Reference: ENCASTRE DALI - 1200X600; sets with these values: 2

# IfcFlowTerminal: Pavé LED encastré_saillie_suspendu:ENCASTRE DALI - 300X300, Pavé LED encastré_saillie_suspendu:ENCASTRE DALI - 300X300:3823030
In: Niveau 0
Type - Material: <Unnamed>
Pset_DistributionFlowElementCommon - Reference: ENCASTRE DALI - 300X300; sets with these values: 2

# IfcFlowTerminal: Pavé LED encastré_saillie_suspendu:ENCASTRE DALI - 400X400, Pavé LED encastré_saillie_suspendu:ENCASTRE DALI - 400X400:3823031
In: Niveau 0
Type - Material: <Unnamed>
Pset_DistributionFlowElementCommon - Reference: ENCASTRE DALI - 400X400; sets with these values: 2

# IfcFlowTerminal: Pavé LED encastré_saillie_suspendu:ENCASTRE DALI - 600X600, Pavé LED encastré_saillie_suspendu:ENCASTRE DALI - 600X600:3823032
In: Niveau 0
Type - Material: <Unnamed>
Pset_DistributionFlowElementCommon - Reference: ENCASTRE DALI - 600X600; sets with these values: 2

# IfcFlowTerminal: Pavé LED encastré_saillie_suspendu:SAILLIE - 1200X300, Pavé LED encastré_saillie_suspendu:SAILLIE - 1200X300:3823036
In: Niveau 0
Type - Material: <Unnamed>
Pset_DistributionFlowElementCommon - Reference: SAILLIE - 1200X300; sets with these values: 2

# IfcFlowTerminal: Pavé LED encastré_saillie_suspendu:SAILLIE - 1200X600, Pavé LED encastré_saillie_suspendu:SAILLIE - 1200X600:3823035
In: Niveau 0
Type - Material: <Unnamed>
Pset_DistributionFlowElementCommon - Reference: SAILLIE - 1200X600; sets with these values: 2

# IfcFlowTerminal: Pavé LED encastré_saillie_suspendu:SAILLIE - 300X300, Pavé LED encastré_saillie_suspendu:SAILLIE - 300X300:3823039
In: Niveau 0
Type - Material: <Unnamed>
Pset_DistributionFlowElementCommon - Reference: SAILLIE - 300X300; sets with these values: 2

# IfcFlowTerminal: Pavé LED encastré_saillie_suspendu:SAILLIE - 400X400, Pavé LED encastré_saillie_suspendu:SAILLIE - 400X400:3823038
In: Niveau 0
Type - Material: <Unnamed>
Pset_DistributionFlowElementCommon - Reference: SAILLIE - 400X400; sets with these values: 2

# IfcFlowTerminal: Pavé LED encastré_saillie_suspendu:SAILLIE - 600X600, Pavé LED encastré_saillie_suspendu:SAILLIE - 600X600:3823037
In: Niveau 0
Type - Material: <Unnamed>
Pset_DistributionFlowElementCommon - Reference: SAILLIE - 600X600; sets with these values: 2

# IfcFlowTerminal: Pavé LED encastré_saillie_suspendu:SAILLIE ASYMETRIQUE - 1200X300, Pavé LED encastré_saillie_suspendu:SAILLIE ASYMETRIQUE - 1200X300:3848919
In: Niveau 0
Type - Material: <Unnamed>
Pset_DistributionFlowElementCommon - Reference: SAILLIE ASYMETRIQUE - 1200X300; sets with these values: 2

# IfcFlowTerminal: Pavé LED encastré_saillie_suspendu:SAILLIE DALI - 1200X300, Pavé LED encastré_saillie_suspendu:SAILLIE DALI - 1200X300:3823043
In: Niveau 0
Type - Material: <Unnamed>
Pset_DistributionFlowElementCommon - Reference: SAILLIE DALI - 1200X300; sets with these values: 2

# IfcFlowTerminal: Pavé LED encastré_saillie_suspendu:SAILLIE DALI - 1200X600, Pavé LED encastré_saillie_suspendu:SAILLIE DALI - 1200X600:3823044
In: Niveau 0
Type - Material: <Unnamed>
Pset_DistributionFlowElementCommon - Reference: SAILLIE DALI - 1200X600; sets with these values: 2

# IfcFlowTerminal: Pavé LED encastré_saillie_suspendu:SAILLIE DALI - 300X300, Pavé LED encastré_saillie_suspendu:SAILLIE DALI - 300X300:3823040
In: Niveau 0
Type - Material: <Unnamed>
Pset_DistributionFlowElementCommon - Reference: SAILLIE DALI - 300X300; sets with these values: 2

# IfcFlowTerminal: Pavé LED encastré_saillie_suspendu:SAILLIE DALI - 400X400, Pavé LED encastré_saillie_suspendu:SAILLIE DALI - 400X400:3823041
In: Niveau 0
Type - Material: <Unnamed>
Pset_DistributionFlowElementCommon - Reference: SAILLIE DALI - 400X400; sets with these values: 2

# IfcFlowTerminal: Pavé LED encastré_saillie_suspendu:SAILLIE DALI - 600X600, Pavé LED encastré_saillie_suspendu:SAILLIE DALI - 600X600:3823042
In: Niveau 0
Type - Material: <Unnamed>
Pset_DistributionFlowElementCommon - Reference: SAILLIE DALI - 600X600; sets with these values: 2

# IfcFlowTerminal: Pavé LED encastré_saillie_suspendu:SAILLIE DALI ASYMETRIQUE - 1200X300, Pavé LED encastré_saillie_suspendu:SAILLIE DALI ASYMETRIQUE - 1200X300:3849035
In: Niveau 0
Type - Material: <Unnamed>
Pset_DistributionFlowElementCommon - Reference: SAILLIE DALI ASYMETRIQUE - 1200X300; sets with these values: 2

# IfcFlowTerminal: Pavé LED encastré_saillie_suspendu:SUSPENDU - 1200X300, Pavé LED encastré_saillie_suspendu:SUSPENDU - 1200X300:3823048
In: Niveau 0
Type - Material: <Unnamed>
Pset_DistributionFlowElementCommon - Reference: SUSPENDU - 1200X300; sets with these values: 2

# IfcFlowTerminal: Pavé LED encastré_saillie_suspendu:SUSPENDU - 1200X600, Pavé LED encastré_saillie_suspendu:SUSPENDU - 1200X600:3823049
In: Niveau 0
Type - Material: <Unnamed>
Pset_DistributionFlowElementCommon - Reference: SUSPENDU - 1200X600; sets with these values: 2

# IfcFlowTerminal: Pavé LED encastré_saillie_suspendu:SUSPENDU - 300X300, Pavé LED encastré_saillie_suspendu:SUSPENDU - 300X300:3823045
In: Niveau 0
Type - Material: <Unnamed>
Pset_DistributionFlowElementCommon - Reference: SUSPENDU - 300X300; sets with these values: 2

# IfcFlowTerminal: Pavé LED encastré_saillie_suspendu:SUSPENDU - 400X400, Pavé LED encastré_saillie_suspendu:SUSPENDU - 400X400:3823046
In: Niveau 0
Type - Material: <Unnamed>
Pset_DistributionFlowElementCommon - Reference: SUSPENDU - 400X400; sets with these values: 2

# IfcFlowTerminal: Pavé LED encastré_saillie_suspendu:SUSPENDU - 600X600, Pavé LED encastré_saillie_suspendu:SUSPENDU - 600X600:3823047
In: Niveau 0
Type - Material: <Unnamed>
Pset_DistributionFlowElementCommon - Reference: SUSPENDU - 600X600; sets with these values: 2

# IfcFlowTerminal: Pavé LED encastré_saillie_suspendu:SUSPENDU ASYMETRIQUE - 1200X300, Pavé LED encastré_saillie_suspendu:SUSPENDU ASYMETRIQUE - 1200X300:3849077
In: Niveau 0
Type - Material: <Unnamed>
Pset_DistributionFlowElementCommon - Reference: SUSPENDU ASYMETRIQUE - 1200X300; sets with these values: 2

# IfcFlowTerminal: Pavé LED encastré_saillie_suspendu:SUSPENDU DALI - 1200X300, Pavé LED encastré_saillie_suspendu:SUSPENDU DALI - 1200X300:3823053
In: Niveau 0
Type - Material: <Unnamed>
Pset_DistributionFlowElementCommon - Reference: SUSPENDU DALI - 1200X300; sets with these values: 2

# IfcFlowTerminal: Pavé LED encastré_saillie_suspendu:SUSPENDU DALI - 1200X600, Pavé LED encastré_saillie_suspendu:SUSPENDU DALI - 1200X600:3823054
In: Niveau 0
Type - Material: <Unnamed>
Pset_DistributionFlowElementCommon - Reference: SUSPENDU DALI - 1200X600; sets with these values: 2

# IfcFlowTerminal: Pavé LED encastré_saillie_suspendu:SUSPENDU DALI - 300X300, Pavé LED encastré_saillie_suspendu:SUSPENDU DALI - 300X300:3823050
In: Niveau 0
Type - Material: <Unnamed>
Pset_DistributionFlowElementCommon - Reference: SUSPENDU DALI - 300X300; sets with these values: 2

# IfcFlowTerminal: Pavé LED encastré_saillie_suspendu:SUSPENDU DALI - 400X400, Pavé LED encastré_saillie_suspendu:SUSPENDU DALI - 400X400:3823051
In: Niveau 0
Type - Material: <Unnamed>
Pset_DistributionFlowElementCommon - Reference: SUSPENDU DALI - 400X400; sets with these values: 2

# IfcFlowTerminal: Pavé LED encastré_saillie_suspendu:SUSPENDU DALI - 600X600, Pavé LED encastré_saillie_suspendu:SUSPENDU DALI - 600X600:3823052
In: Niveau 0
Type - Material: <Unnamed>
Pset_DistributionFlowElementCommon - Reference: SUSPENDU DALI - 600X600; sets with these values: 2

# IfcFlowTerminal: Pavé LED encastré_saillie_suspendu:SUSPENDU DALI ASYMETRIQUE - 1200X300, Pavé LED encastré_saillie_suspendu:SUSPENDU DALI ASYMETRIQUE - 1200X300:3849157
In: Niveau 0
Type - Material: <Unnamed>
Pset_DistributionFlowElementCommon - Reference: SUSPENDU DALI ASYMETRIQUE - 1200X300; sets with these values: 2

# IfcFlowTerminal: Pavé LED lentille encastré_saillie_suspendu:ENCASTRE - 1200X300 - 1L DE 16, Pavé LED lentille encastré_saillie_suspendu:ENCASTRE - 1200X300 - 1L DE 16:4863844
In: Niveau 0
Type - Material: <Unnamed>, BETCE-DIFFUSEUR-BLANC, BETCE-ENVELOPPE-BLANC
Pset_DistributionFlowElementCommon - Reference: ENCASTRE - 1200X300 - 1L DE 16; sets with these values: 2

# IfcFlowTerminal: Pavé LED lentille encastré_saillie_suspendu:ENCASTRE - 1200X300 - 2L DE 16, Pavé LED lentille encastré_saillie_suspendu:ENCASTRE - 1200X300 - 2L DE 16:4863998
In: Niveau 0
Type - Material: <Unnamed>, BETCE-DIFFUSEUR-BLANC, BETCE-ENVELOPPE-BLANC
Pset_DistributionFlowElementCommon - Reference: ENCASTRE - 1200X300 - 2L DE 16; sets with these values: 2

# IfcFlowTerminal: Pavé LED lentille encastré_saillie_suspendu:ENCASTRE - 1200X300 - 2L DE 8, Pavé LED lentille encastré_saillie_suspendu:ENCASTRE - 1200X300 - 2L DE 8:4863922
In: Niveau 0
Type - Material: <Unnamed>, BETCE-DIFFUSEUR-BLANC, BETCE-ENVELOPPE-BLANC
Pset_DistributionFlowElementCommon - Reference: ENCASTRE - 1200X300 - 2L DE 8; sets with these values: 2

# IfcFlowTerminal: Pavé LED lentille encastré_saillie_suspendu:ENCASTRE - 600X600 - 2L DE 8 (2)
In: Niveau 0
Type - Material: <Unnamed>, BETCE-DIFFUSEUR-BLANC, BETCE-ENVELOPPE-BLANC
Pset_DistributionFlowElementCommon - Reference: ENCASTRE - 600X600 - 2L DE 8; sets with these values: 2
Name (Pavé LED lentille encastré_saillie_suspendu:ENCASTRE - 600X600 - 2L DE 8:...)
4863526
6163932

# IfcFlowTerminal: Pavé LED lentille encastré_saillie_suspendu:ENCASTRE - 600X600 - 3L DE 8, Pavé LED lentille encastré_saillie_suspendu:ENCASTRE - 600X600 - 3L DE 8:4863674
In: Niveau 0
Type - Material: <Unnamed>, BETCE-DIFFUSEUR-BLANC, BETCE-ENVELOPPE-BLANC
Pset_DistributionFlowElementCommon - Reference: ENCASTRE - 600X600 - 3L DE 8; sets with these values: 2

# IfcFlowTerminal: Pavé LED lentille encastré_saillie_suspendu:ENCASTRE - 600X600 - 4L DE 4, Pavé LED lentille encastré_saillie_suspendu:ENCASTRE - 600X600 - 4L DE 4:4863776
In: Niveau 0
Type - Material: <Unnamed>, BETCE-DIFFUSEUR-BLANC, BETCE-ENVELOPPE-BLANC
Pset_DistributionFlowElementCommon - Reference: ENCASTRE - 600X600 - 4L DE 4; sets with these values: 2

# IfcFlowTerminal: Pavé LED lentille encastré_saillie_suspendu:ENCASTRE DALI - 1200X300 - 1L DE 16, Pavé LED lentille encastré_saillie_suspendu:ENCASTRE DALI - 1200X300 - 1L DE 16:4864326
In: Niveau 0
Type - Material: <Unnamed>, BETCE-DIFFUSEUR-BLANC, BETCE-ENVELOPPE-BLANC
Pset_DistributionFlowElementCommon - Reference: ENCASTRE DALI - 1200X300 - 1L DE 16; sets with these values: 2

# IfcFlowTerminal: Pavé LED lentille encastré_saillie_suspendu:ENCASTRE DALI - 1200X300 - 2L DE 16, Pavé LED lentille encastré_saillie_suspendu:ENCASTRE DALI - 1200X300 - 2L DE 16:4864414
In: Niveau 0
Type - Material: <Unnamed>, BETCE-DIFFUSEUR-BLANC, BETCE-ENVELOPPE-BLANC
Pset_DistributionFlowElementCommon - Reference: ENCASTRE DALI - 1200X300 - 2L DE 16; sets with these values: 2

# IfcFlowTerminal: Pavé LED lentille encastré_saillie_suspendu:ENCASTRE DALI - 1200X300 - 2L DE 8, Pavé LED lentille encastré_saillie_suspendu:ENCASTRE DALI - 1200X300 - 2L DE 8:4864370
In: Niveau 0
Type - Material: <Unnamed>, BETCE-DIFFUSEUR-BLANC, BETCE-ENVELOPPE-BLANC
Pset_DistributionFlowElementCommon - Reference: ENCASTRE DALI - 1200X300 - 2L DE 8; sets with these values: 2

# IfcFlowTerminal: Pavé LED lentille encastré_saillie_suspendu:ENCASTRE DALI - 600X600 - 2L DE 8, Pavé LED lentille encastré_saillie_suspendu:ENCASTRE DALI - 600X600 - 2L DE 8:4864106
In: Niveau 0
Type - Material: <Unnamed>, BETCE-DIFFUSEUR-BLANC, BETCE-ENVELOPPE-BLANC
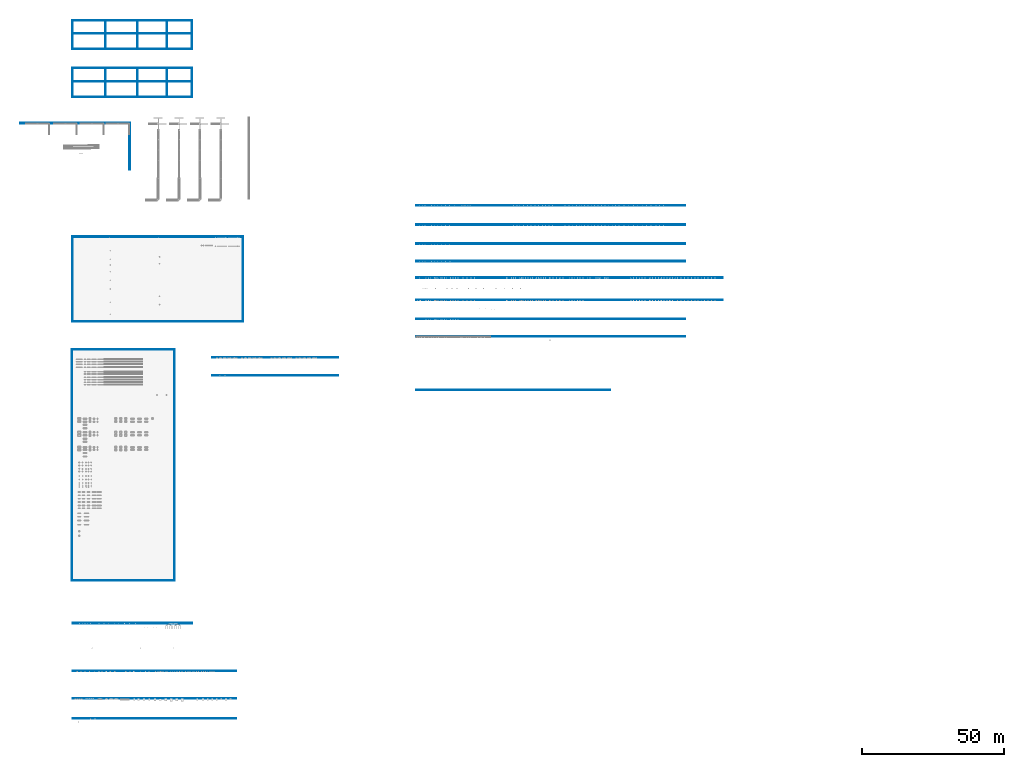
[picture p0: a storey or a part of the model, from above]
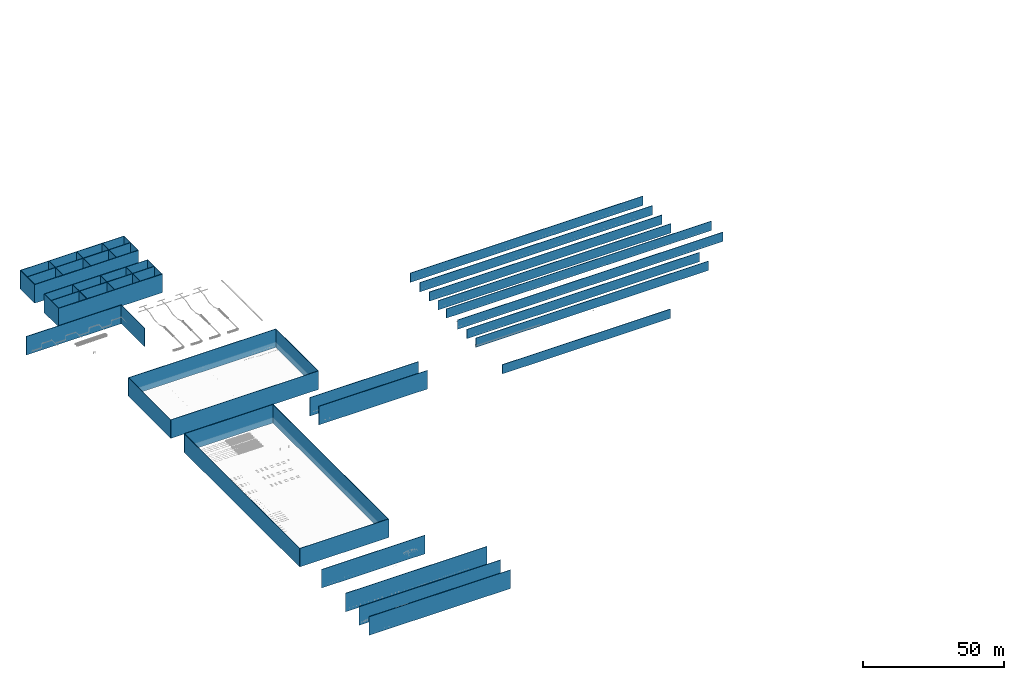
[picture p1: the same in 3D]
Properties of the parts of a building model (IFC2X3), part 5 of 5

# IfcFlowTerminal: Pavé LED lentille encastré_saillie_suspendu:ENCASTRE DALI - 600X600 - 2L DE 8, Pavé LED lentille encastré_saillie_suspendu:ENCASTRE DALI - 600X600 - 2L DE 8:4864106
Pset_DistributionFlowElementCommon - Reference: ENCASTRE DALI - 600X600 - 2L DE 8; sets with these values: 2

# IfcFlowTerminal: Pavé LED lentille encastré_saillie_suspendu:ENCASTRE DALI - 600X600 - 3L DE 8, Pavé LED lentille encastré_saillie_suspendu:ENCASTRE DALI - 600X600 - 3L DE 8:4864210
In: Niveau 0
Type - Material: <Unnamed>, BETCE-DIFFUSEUR-BLANC, BETCE-ENVELOPPE-BLANC
Pset_DistributionFlowElementCommon - Reference: ENCASTRE DALI - 600X600 - 3L DE 8; sets with these values: 2

# IfcFlowTerminal: Pavé LED lentille encastré_saillie_suspendu:ENCASTRE DALI - 600X600 - 4L DE 4, Pavé LED lentille encastré_saillie_suspendu:ENCASTRE DALI - 600X600 - 4L DE 4:4864274
In: Niveau 0
Type - Material: <Unnamed>, BETCE-DIFFUSEUR-BLANC, BETCE-ENVELOPPE-BLANC
Pset_DistributionFlowElementCommon - Reference: ENCASTRE DALI - 600X600 - 4L DE 4; sets with these values: 2

# IfcFlowTerminal: Pavé LED lentille encastré_saillie_suspendu:SAILLIE - 1200X300 - 1L DE 16, Pavé LED lentille encastré_saillie_suspendu:SAILLIE - 1200X300 - 1L DE 16:4864670
In: Niveau 0
Type - Material: <Unnamed>, BETCE-DIFFUSEUR-BLANC, BETCE-ENVELOPPE-BLANC
Pset_DistributionFlowElementCommon - Reference: SAILLIE - 1200X300 - 1L DE 16; sets with these values: 2

# IfcFlowTerminal: Pavé LED lentille encastré_saillie_suspendu:SAILLIE - 1200X300 - 2L DE 16, Pavé LED lentille encastré_saillie_suspendu:SAILLIE - 1200X300 - 2L DE 16:4864768
In: Niveau 0
Type - Material: <Unnamed>, BETCE-DIFFUSEUR-BLANC, BETCE-ENVELOPPE-BLANC
Pset_DistributionFlowElementCommon - Reference: SAILLIE - 1200X300 - 2L DE 16; sets with these values: 2

# IfcFlowTerminal: Pavé LED lentille encastré_saillie_suspendu:SAILLIE - 1200X300 - 2L DE 8, Pavé LED lentille encastré_saillie_suspendu:SAILLIE - 1200X300 - 2L DE 8:4864718
In: Niveau 0
Type - Material: <Unnamed>, BETCE-DIFFUSEUR-BLANC, BETCE-ENVELOPPE-BLANC
Pset_DistributionFlowElementCommon - Reference: SAILLIE - 1200X300 - 2L DE 8; sets with these values: 2

# IfcFlowTerminal: Pavé LED lentille encastré_saillie_suspendu:SAILLIE - 600X600 - 2L DE 8, Pavé LED lentille encastré_saillie_suspendu:SAILLIE - 600X600 - 2L DE 8:4864462
In: Niveau 0
Type - Material: <Unnamed>, BETCE-DIFFUSEUR-BLANC, BETCE-ENVELOPPE-BLANC
Pset_DistributionFlowElementCommon - Reference: SAILLIE - 600X600 - 2L DE 8; sets with these values: 2

# IfcFlowTerminal: Pavé LED lentille encastré_saillie_suspendu:SAILLIE - 600X600 - 3L DE 8 (2)
In: Niveau 0
Type - Material: <Unnamed>, BETCE-DIFFUSEUR-BLANC, BETCE-ENVELOPPE-BLANC
Pset_DistributionFlowElementCommon - Reference: SAILLIE - 600X600 - 3L DE 8; sets with these values: 2
Name (Pavé LED lentille encastré_saillie_suspendu:SAILLIE - 600X600 - 3L DE 8:...)
4864554
4864896

# IfcFlowTerminal: Pavé LED lentille encastré_saillie_suspendu:SAILLIE - 600X600 - 4L DE 4, Pavé LED lentille encastré_saillie_suspendu:SAILLIE - 600X600 - 4L DE 4:4864604
In: Niveau 0
Type - Material: <Unnamed>, BETCE-DIFFUSEUR-BLANC, BETCE-ENVELOPPE-BLANC
Pset_DistributionFlowElementCommon - Reference: SAILLIE - 600X600 - 4L DE 4; sets with these values: 2

# IfcFlowTerminal: Pavé LED lentille encastré_saillie_suspendu:SAILLIE DALI - 1200X300 - 1L DE 16, Pavé LED lentille encastré_saillie_suspendu:SAILLIE DALI - 1200X300 - 1L DE 16:4864988
In: Niveau 0
Type - Material: <Unnamed>, BETCE-DIFFUSEUR-BLANC, BETCE-ENVELOPPE-BLANC
Pset_DistributionFlowElementCommon - Reference: SAILLIE DALI - 1200X300 - 1L DE 16; sets with these values: 2

# IfcFlowTerminal: Pavé LED lentille encastré_saillie_suspendu:SAILLIE DALI - 1200X300 - 2L DE 16, Pavé LED lentille encastré_saillie_suspendu:SAILLIE DALI - 1200X300 - 2L DE 16:4865098
In: Niveau 0
Type - Material: <Unnamed>, BETCE-DIFFUSEUR-BLANC, BETCE-ENVELOPPE-BLANC
Pset_DistributionFlowElementCommon - Reference: SAILLIE DALI - 1200X300 - 2L DE 16; sets with these values: 2

# IfcFlowTerminal: Pavé LED lentille encastré_saillie_suspendu:SAILLIE DALI - 1200X300 - 2L DE 8, Pavé LED lentille encastré_saillie_suspendu:SAILLIE DALI - 1200X300 - 2L DE 8:4865034
In: Niveau 0
Type - Material: <Unnamed>, BETCE-DIFFUSEUR-BLANC, BETCE-ENVELOPPE-BLANC
Pset_DistributionFlowElementCommon - Reference: SAILLIE DALI - 1200X300 - 2L DE 8; sets with these values: 2

# IfcFlowTerminal: Pavé LED lentille encastré_saillie_suspendu:SAILLIE DALI - 600X600 - 2L DE 8, Pavé LED lentille encastré_saillie_suspendu:SAILLIE DALI - 600X600 - 2L DE 8:4864820
In: Niveau 0
Type - Material: <Unnamed>, BETCE-DIFFUSEUR-BLANC, BETCE-ENVELOPPE-BLANC
Pset_DistributionFlowElementCommon - Reference: SAILLIE DALI - 600X600 - 2L DE 8; sets with these values: 2

# IfcFlowTerminal: Pavé LED lentille encastré_saillie_suspendu:SAILLIE DALI - 600X600 - 4L DE 4, Pavé LED lentille encastré_saillie_suspendu:SAILLIE DALI - 600X600 - 4L DE 4:4864942
In: Niveau 0
Type - Material: <Unnamed>, BETCE-DIFFUSEUR-BLANC, BETCE-ENVELOPPE-BLANC
Pset_DistributionFlowElementCommon - Reference: SAILLIE DALI - 600X600 - 4L DE 4; sets with these values: 2

# IfcFlowTerminal: Pavé LED lentille encastré_saillie_suspendu:SUSPENDU - 1200X300 - 1L DE 16, Pavé LED lentille encastré_saillie_suspendu:SUSPENDU - 1200X300 - 1L DE 16:4865424
In: Niveau 0
Type - Material: <Unnamed>, BETCE-DIFFUSEUR-BLANC, BETCE-ENVELOPPE-BLANC
Pset_DistributionFlowElementCommon - Reference: SUSPENDU - 1200X300 - 1L DE 16; sets with these values: 2

# IfcFlowTerminal: Pavé LED lentille encastré_saillie_suspendu:SUSPENDU - 1200X300 - 2L DE 16, Pavé LED lentille encastré_saillie_suspendu:SUSPENDU - 1200X300 - 2L DE 16:4865580
In: Niveau 0
Type - Material: <Unnamed>, BETCE-DIFFUSEUR-BLANC, BETCE-ENVELOPPE-BLANC
Pset_DistributionFlowElementCommon - Reference: SUSPENDU - 1200X300 - 2L DE 16; sets with these values: 2

# IfcFlowTerminal: Pavé LED lentille encastré_saillie_suspendu:SUSPENDU - 1200X300 - 2L DE 8, Pavé LED lentille encastré_saillie_suspendu:SUSPENDU - 1200X300 - 2L DE 8:4865510
In: Niveau 0
Type - Material: <Unnamed>, BETCE-DIFFUSEUR-BLANC, BETCE-ENVELOPPE-BLANC
Pset_DistributionFlowElementCommon - Reference: SUSPENDU - 1200X300 - 2L DE 8; sets with these values: 2

# IfcFlowTerminal: Pavé LED lentille encastré_saillie_suspendu:SUSPENDU - 600X600 - 2L DE 8, Pavé LED lentille encastré_saillie_suspendu:SUSPENDU - 600X600 - 2L DE 8:4865144
In: Niveau 0
Type - Material: <Unnamed>, BETCE-DIFFUSEUR-BLANC, BETCE-ENVELOPPE-BLANC
Pset_DistributionFlowElementCommon - Reference: SUSPENDU - 600X600 - 2L DE 8; sets with these values: 2

# IfcFlowTerminal: Pavé LED lentille encastré_saillie_suspendu:SUSPENDU - 600X600 - 3L DE 8, Pavé LED lentille encastré_saillie_suspendu:SUSPENDU - 600X600 - 3L DE 8:4865304
In: Niveau 0
Type - Material: <Unnamed>, BETCE-DIFFUSEUR-BLANC, BETCE-ENVELOPPE-BLANC
Pset_DistributionFlowElementCommon - Reference: SUSPENDU - 600X600 - 3L DE 8; sets with these values: 2

# IfcFlowTerminal: Pavé LED lentille encastré_saillie_suspendu:SUSPENDU - 600X600 - 4L DE 4, Pavé LED lentille encastré_saillie_suspendu:SUSPENDU - 600X600 - 4L DE 4:4865360
In: Niveau 0
Type - Material: <Unnamed>, BETCE-DIFFUSEUR-BLANC, BETCE-ENVELOPPE-BLANC
Pset_DistributionFlowElementCommon - Reference: SUSPENDU - 600X600 - 4L DE 4; sets with these values: 2

# IfcFlowTerminal: Pavé LED lentille encastré_saillie_suspendu:SUSPENDU DALI - 1200X300 - 1L DE 16, Pavé LED lentille encastré_saillie_suspendu:SUSPENDU DALI - 1200X300 - 1L DE 16:4865820
In: Niveau 0
Type - Material: <Unnamed>, BETCE-DIFFUSEUR-BLANC, BETCE-ENVELOPPE-BLANC
Pset_DistributionFlowElementCommon - Reference: SUSPENDU DALI - 1200X300 - 1L DE 16; sets with these values: 2

# IfcFlowTerminal: Pavé LED lentille encastré_saillie_suspendu:SUSPENDU DALI - 1200X300 - 2L DE 16, Pavé LED lentille encastré_saillie_suspendu:SUSPENDU DALI - 1200X300 - 2L DE 16:4865970
In: Niveau 0
Type - Material: <Unnamed>, BETCE-DIFFUSEUR-BLANC, BETCE-ENVELOPPE-BLANC
Pset_DistributionFlowElementCommon - Reference: SUSPENDU DALI - 1200X300 - 2L DE 16; sets with these values: 2

# IfcFlowTerminal: Pavé LED lentille encastré_saillie_suspendu:SUSPENDU DALI - 1200X300 - 2L DE 8, Pavé LED lentille encastré_saillie_suspendu:SUSPENDU DALI - 1200X300 - 2L DE 8:4865894
In: Niveau 0
Type - Material: <Unnamed>, BETCE-DIFFUSEUR-BLANC, BETCE-ENVELOPPE-BLANC
Pset_DistributionFlowElementCommon - Reference: SUSPENDU DALI - 1200X300 - 2L DE 8; sets with these values: 2

# IfcFlowTerminal: Pavé LED lentille encastré_saillie_suspendu:SUSPENDU DALI - 600X600 - 2L DE 8, Pavé LED lentille encastré_saillie_suspendu:SUSPENDU DALI - 600X600 - 2L DE 8:4865660
In: Niveau 0
Type - Material: <Unnamed>, BETCE-DIFFUSEUR-BLANC, BETCE-ENVELOPPE-BLANC
Pset_DistributionFlowElementCommon - Reference: SUSPENDU DALI - 600X600 - 2L DE 8; sets with these values: 2

# IfcFlowTerminal: Pavé LED lentille encastré_saillie_suspendu:SUSPENDU DALI - 600X600 - 3L DE 8, Pavé LED lentille encastré_saillie_suspendu:SUSPENDU DALI - 600X600 - 3L DE 8:4865702
In: Niveau 0
Type - Material: <Unnamed>, BETCE-DIFFUSEUR-BLANC, BETCE-ENVELOPPE-BLANC
Pset_DistributionFlowElementCommon - Reference: SUSPENDU DALI - 600X600 - 3L DE 8; sets with these values: 2

# IfcFlowTerminal: Pavé LED lentille encastré_saillie_suspendu:SUSPENDU DALI - 600X600 - 4L DE 4, Pavé LED lentille encastré_saillie_suspendu:SUSPENDU DALI - 600X600 - 4L DE 4:4865734
In: Niveau 0
Type - Material: <Unnamed>, BETCE-DIFFUSEUR-BLANC, BETCE-ENVELOPPE-BLANC
Pset_DistributionFlowElementCommon - Reference: SUSPENDU DALI - 600X600 - 4L DE 4; sets with these values: 2

# IfcFlowTerminal: Profilé alu encastré-20X20:ENCASTRE, Profilé alu encastré-20X20:ENCASTRE:3752997
In: Niveau 0
Type - Material: <Unnamed>
Pset_DistributionFlowElementCommon - Reference: ENCASTRE; sets with these values: 2

# IfcFlowTerminal: Profilé alu encastré-20X20:ENCASTRE -0.5M, Profilé alu encastré-20X20:ENCASTRE -0.5M:3764059
In: Niveau 0
Type - Material: <Unnamed>
Pset_DistributionFlowElementCommon - Reference: ENCASTRE -0.5M; sets with these values: 2

# IfcFlowTerminal: Profilé alu encastré-20X20:ENCASTRE -1.5M, Profilé alu encastré-20X20:ENCASTRE -1.5M:3764259
In: Niveau 0
Type - Material: <Unnamed>
Pset_DistributionFlowElementCommon - Reference: ENCASTRE -1.5M; sets with these values: 2

# IfcFlowTerminal: Profilé alu encastré-20X20:ENCASTRE -1M, Profilé alu encastré-20X20:ENCASTRE -1M:3764155
In: Niveau 0
Type - Material: <Unnamed>
Pset_DistributionFlowElementCommon - Reference: ENCASTRE -1M; sets with these values: 2

# IfcFlowTerminal: Profilé alu encastré-20X20:ENCASTRE -2M, Profilé alu encastré-20X20:ENCASTRE -2M:3764377
In: Niveau 0
Type - Material: <Unnamed>
Pset_DistributionFlowElementCommon - Reference: ENCASTRE -2M; sets with these values: 2

# IfcFlowTerminal: Profilé alu encastré-20X20:ENCASTRE -3M, Profilé alu encastré-20X20:ENCASTRE -3M:3764463
In: Niveau 0
Type - Material: <Unnamed>
Pset_DistributionFlowElementCommon - Reference: ENCASTRE -3M; sets with these values: 2

# IfcFlowTerminal: Profilé alu encastré-20X20:ENCASTRE -4M, Profilé alu encastré-20X20:ENCASTRE -4M:3764539
In: Niveau 0
Type - Material: <Unnamed>
Pset_DistributionFlowElementCommon - Reference: ENCASTRE -4M; sets with these values: 2

# IfcFlowTerminal: Profilé alu encastré-20X20:ENCASTRE -5M, Profilé alu encastré-20X20:ENCASTRE -5M:3764741
In: Niveau 0
Type - Material: <Unnamed>
Pset_DistributionFlowElementCommon - Reference: ENCASTRE -5M; sets with these values: 2

# IfcFlowTerminal: Profilé alu encastré-20X20:ENCASTRE DALI, Profilé alu encastré-20X20:ENCASTRE DALI:3756315
In: Niveau 0
Type - Material: <Unnamed>
Pset_DistributionFlowElementCommon - Reference: ENCASTRE DALI; sets with these values: 2

# IfcFlowTerminal: Profilé alu encastré-20X20:ENCASTRE DALI -0.5M, Profilé alu encastré-20X20:ENCASTRE DALI -0.5M:3764872
In: Niveau 0
Type - Material: <Unnamed>
Pset_DistributionFlowElementCommon - Reference: ENCASTRE DALI -0.5M; sets with these values: 2

# IfcFlowTerminal: Profilé alu encastré-20X20:ENCASTRE DALI -1.5M, Profilé alu encastré-20X20:ENCASTRE DALI -1.5M:3765030
In: Niveau 0
Type - Material: <Unnamed>
Pset_DistributionFlowElementCommon - Reference: ENCASTRE DALI -1.5M; sets with these values: 2

# IfcFlowTerminal: Profilé alu encastré-20X20:ENCASTRE DALI -1M, Profilé alu encastré-20X20:ENCASTRE DALI -1M:3764956
In: Niveau 0
Type - Material: <Unnamed>
Pset_DistributionFlowElementCommon - Reference: ENCASTRE DALI -1M; sets with these values: 2

# IfcFlowTerminal: Profilé alu encastré-20X20:ENCASTRE DALI -2M, Profilé alu encastré-20X20:ENCASTRE DALI -2M:3765112
In: Niveau 0
Type - Material: <Unnamed>
Pset_DistributionFlowElementCommon - Reference: ENCASTRE DALI -2M; sets with these values: 2

# IfcFlowTerminal: Profilé alu encastré-20X20:ENCASTRE DALI -3M, Profilé alu encastré-20X20:ENCASTRE DALI -3M:3765176
In: Niveau 0
Type - Material: <Unnamed>
Pset_DistributionFlowElementCommon - Reference: ENCASTRE DALI -3M; sets with these values: 2

# IfcFlowTerminal: Profilé alu encastré-20X20:ENCASTRE DALI -4M, Profilé alu encastré-20X20:ENCASTRE DALI -4M:3765222
In: Niveau 0
Type - Material: <Unnamed>
Pset_DistributionFlowElementCommon - Reference: ENCASTRE DALI -4M; sets with these values: 2

# IfcFlowTerminal: Profilé alu encastré-20X20:ENCASTRE DALI -5M, Profilé alu encastré-20X20:ENCASTRE DALI -5M:3765284
In: Niveau 0
Type - Material: <Unnamed>
Pset_DistributionFlowElementCommon - Reference: ENCASTRE DALI -5M; sets with these values: 2

# IfcFlowTerminal: Profilé alu encastré-30X30:ENCASTRE, Profilé alu encastré-30X30:ENCASTRE:3899268
In: Niveau 0
Type - Material: <Unnamed>
Pset_DistributionFlowElementCommon - Reference: ENCASTRE; sets with these values: 2

# IfcFlowTerminal: Profilé alu encastré-30X30:ENCASTRE -0.5M, Profilé alu encastré-30X30:ENCASTRE -0.5M:3899994
In: Niveau 0
Type - Material: <Unnamed>
Pset_DistributionFlowElementCommon - Reference: ENCASTRE -0.5M; sets with these values: 2

# IfcFlowTerminal: Profilé alu encastré-30X30:ENCASTRE -1.5M, Profilé alu encastré-30X30:ENCASTRE -1.5M:3900092
In: Niveau 0
Type - Material: <Unnamed>
Pset_DistributionFlowElementCommon - Reference: ENCASTRE -1.5M; sets with these values: 2

# IfcFlowTerminal: Profilé alu encastré-30X30:ENCASTRE -1M, Profilé alu encastré-30X30:ENCASTRE -1M:3900166
In: Niveau 0
Type - Material: <Unnamed>
Pset_DistributionFlowElementCommon - Reference: ENCASTRE -1M; sets with these values: 2

# IfcFlowTerminal: Profilé alu encastré-30X30:ENCASTRE -2M, Profilé alu encastré-30X30:ENCASTRE -2M:3900232
In: Niveau 0
Type - Material: <Unnamed>
Pset_DistributionFlowElementCommon - Reference: ENCASTRE -2M; sets with these values: 2

# IfcFlowTerminal: Profilé alu encastré-30X30:ENCASTRE -3M, Profilé alu encastré-30X30:ENCASTRE -3M:3900298
In: Niveau 0
Type - Material: <Unnamed>
Pset_DistributionFlowElementCommon - Reference: ENCASTRE -3M; sets with these values: 2

# IfcFlowTerminal: Profilé alu encastré-30X30:ENCASTRE -4M, Profilé alu encastré-30X30:ENCASTRE -4M:3900346
In: Niveau 0
Type - Material: <Unnamed>
Pset_DistributionFlowElementCommon - Reference: ENCASTRE -4M; sets with these values: 2

# IfcFlowTerminal: Profilé alu encastré-30X30:ENCASTRE -5M, Profilé alu encastré-30X30:ENCASTRE -5M:3900402
In: Niveau 0
Type - Material: <Unnamed>
Pset_DistributionFlowElementCommon - Reference: ENCASTRE -5M; sets with these values: 2

# IfcFlowTerminal: Profilé alu encastré-30X30:ENCASTRE DALI, Profilé alu encastré-30X30:ENCASTRE DALI:3899923
In: Niveau 0
Type - Material: <Unnamed>
Pset_DistributionFlowElementCommon - Reference: ENCASTRE DALI; sets with these values: 2

# IfcFlowTerminal: Profilé alu encastré-30X30:ENCASTRE DALI -0.5M, Profilé alu encastré-30X30:ENCASTRE DALI -0.5M:3900450
In: Niveau 0
Type - Material: <Unnamed>
Pset_DistributionFlowElementCommon - Reference: ENCASTRE DALI -0.5M; sets with these values: 2

# IfcFlowTerminal: Profilé alu encastré-30X30:ENCASTRE DALI -1.5M, Profilé alu encastré-30X30:ENCASTRE DALI -1.5M:3900518
In: Niveau 0
Type - Material: <Unnamed>
Pset_DistributionFlowElementCommon - Reference: ENCASTRE DALI -1.5M; sets with these values: 2

# IfcFlowTerminal: Profilé alu encastré-30X30:ENCASTRE DALI -1M, Profilé alu encastré-30X30:ENCASTRE DALI -1M:3900584
In: Niveau 0
Type - Material: <Unnamed>
Pset_DistributionFlowElementCommon - Reference: ENCASTRE DALI -1M; sets with these values: 2

# IfcFlowTerminal: Profilé alu encastré-30X30:ENCASTRE DALI -2M, Profilé alu encastré-30X30:ENCASTRE DALI -2M:3900668
In: Niveau 0
Type - Material: <Unnamed>
Pset_DistributionFlowElementCommon - Reference: ENCASTRE DALI -2M; sets with these values: 2

# IfcFlowTerminal: Profilé alu encastré-30X30:ENCASTRE DALI -3M, Profilé alu encastré-30X30:ENCASTRE DALI -3M:3900822
In: Niveau 0
Type - Material: <Unnamed>
Pset_DistributionFlowElementCommon - Reference: ENCASTRE DALI -3M; sets with these values: 2

# IfcFlowTerminal: Profilé alu encastré-30X30:ENCASTRE DALI -4M, Profilé alu encastré-30X30:ENCASTRE DALI -4M:3900910
In: Niveau 0
Type - Material: <Unnamed>
Pset_DistributionFlowElementCommon - Reference: ENCASTRE DALI -4M; sets with these values: 2

# IfcFlowTerminal: Profilé alu encastré-30X30:ENCASTRE DALI -5M, Profilé alu encastré-30X30:ENCASTRE DALI -5M:3901002
In: Niveau 0
Type - Material: <Unnamed>
Pset_DistributionFlowElementCommon - Reference: ENCASTRE DALI -5M; sets with these values: 2

# IfcFlowTerminal: Profilé alu sailli_suspendu_engravure-20X20:PROF-ENGRAVURE -0.5M, Profilé alu sailli_suspendu_engravure-20X20:PROF-ENGRAVURE -0.5M:3821965
In: Niveau 0
Type - Material: BETCE-DIFFUSEUR-BLANC, <Unnamed>
Pset_DistributionFlowElementCommon - Reference: PROF-ENGRAVURE -0.5M; sets with these values: 2

# IfcFlowTerminal: Profilé alu sailli_suspendu_engravure-20X20:PROF-ENGRAVURE -1.5M, Profilé alu sailli_suspendu_engravure-20X20:PROF-ENGRAVURE -1.5M:3822077
In: Niveau 0
Type - Material: BETCE-DIFFUSEUR-BLANC, <Unnamed>
Pset_DistributionFlowElementCommon - Reference: PROF-ENGRAVURE -1.5M; sets with these values: 2

# IfcFlowTerminal: Profilé alu sailli_suspendu_engravure-20X20:PROF-ENGRAVURE -1M, Profilé alu sailli_suspendu_engravure-20X20:PROF-ENGRAVURE -1M:3822133
In: Niveau 0
Type - Material: BETCE-DIFFUSEUR-BLANC, <Unnamed>
Pset_DistributionFlowElementCommon - Reference: PROF-ENGRAVURE -1M; sets with these values: 2

# IfcFlowTerminal: Profilé alu sailli_suspendu_engravure-20X20:PROF-ENGRAVURE -2M, Profilé alu sailli_suspendu_engravure-20X20:PROF-ENGRAVURE -2M:3822183
In: Niveau 0
Type - Material: BETCE-DIFFUSEUR-BLANC, <Unnamed>
Pset_DistributionFlowElementCommon - Reference: PROF-ENGRAVURE -2M; sets with these values: 2

# IfcFlowTerminal: Profilé alu sailli_suspendu_engravure-20X20:PROF-ENGRAVURE -3M, Profilé alu sailli_suspendu_engravure-20X20:PROF-ENGRAVURE -3M:3822249
In: Niveau 0
Type - Material: BETCE-DIFFUSEUR-BLANC, <Unnamed>
Pset_DistributionFlowElementCommon - Reference: PROF-ENGRAVURE -3M; sets with these values: 2

# IfcFlowTerminal: Profilé alu sailli_suspendu_engravure-20X20:PROF-ENGRAVURE -4M, Profilé alu sailli_suspendu_engravure-20X20:PROF-ENGRAVURE -4M:3822303
In: Niveau 0
Type - Material: BETCE-DIFFUSEUR-BLANC, <Unnamed>
Pset_DistributionFlowElementCommon - Reference: PROF-ENGRAVURE -4M; sets with these values: 2

# IfcFlowTerminal: Profilé alu sailli_suspendu_engravure-20X20:PROF-ENGRAVURE -5M, Profilé alu sailli_suspendu_engravure-20X20:PROF-ENGRAVURE -5M:3822351
In: Niveau 0
Type - Material: BETCE-DIFFUSEUR-BLANC, <Unnamed>
Pset_DistributionFlowElementCommon - Reference: PROF-ENGRAVURE -5M; sets with these values: 2

# IfcFlowTerminal: Profilé alu sailli_suspendu_engravure-20X20:PROF-ENGRAVURE DALI -0.5M, Profilé alu sailli_suspendu_engravure-20X20:PROF-ENGRAVURE DALI -0.5M:3822429
In: Niveau 0
Type - Material: BETCE-DIFFUSEUR-BLANC, <Unnamed>
Pset_DistributionFlowElementCommon - Reference: PROF-ENGRAVURE DALI -0.5M; sets with these values: 2

# IfcFlowTerminal: Profilé alu sailli_suspendu_engravure-20X20:PROF-ENGRAVURE DALI -1.5M, Profilé alu sailli_suspendu_engravure-20X20:PROF-ENGRAVURE DALI -1.5M:3822505
In: Niveau 0
Type - Material: BETCE-DIFFUSEUR-BLANC, <Unnamed>
Pset_DistributionFlowElementCommon - Reference: PROF-ENGRAVURE DALI -1.5M; sets with these values: 2

# IfcFlowTerminal: Profilé alu sailli_suspendu_engravure-20X20:PROF-ENGRAVURE DALI -1M, Profilé alu sailli_suspendu_engravure-20X20:PROF-ENGRAVURE DALI -1M:3822561
In: Niveau 0
Type - Material: BETCE-DIFFUSEUR-BLANC, <Unnamed>
Pset_DistributionFlowElementCommon - Reference: PROF-ENGRAVURE DALI -1M; sets with these values: 2

# IfcFlowTerminal: Profilé alu sailli_suspendu_engravure-20X20:PROF-ENGRAVURE DALI -2M, Profilé alu sailli_suspendu_engravure-20X20:PROF-ENGRAVURE DALI -2M:3822651
In: Niveau 0
Type - Material: BETCE-DIFFUSEUR-BLANC, <Unnamed>
Pset_DistributionFlowElementCommon - Reference: PROF-ENGRAVURE DALI -2M; sets with these values: 2

# IfcFlowTerminal: Profilé alu sailli_suspendu_engravure-20X20:PROF-ENGRAVURE DALI -3M, Profilé alu sailli_suspendu_engravure-20X20:PROF-ENGRAVURE DALI -3M:3822775
In: Niveau 0
Type - Material: BETCE-DIFFUSEUR-BLANC, <Unnamed>
Pset_DistributionFlowElementCommon - Reference: PROF-ENGRAVURE DALI -3M; sets with these values: 2

# IfcFlowTerminal: Profilé alu sailli_suspendu_engravure-20X20:PROF-ENGRAVURE DALI -4M, Profilé alu sailli_suspendu_engravure-20X20:PROF-ENGRAVURE DALI -4M:3822825
In: Niveau 0
Type - Material: BETCE-DIFFUSEUR-BLANC, <Unnamed>
Pset_DistributionFlowElementCommon - Reference: PROF-ENGRAVURE DALI -4M; sets with these values: 2

# IfcFlowTerminal: Profilé alu sailli_suspendu_engravure-20X20:PROF-ENGRAVURE DALI -5M, Profilé alu sailli_suspendu_engravure-20X20:PROF-ENGRAVURE DALI -5M:3822917
In: Niveau 0
Type - Material: BETCE-DIFFUSEUR-BLANC, <Unnamed>
Pset_DistributionFlowElementCommon - Reference: PROF-ENGRAVURE DALI -5M; sets with these values: 2

# IfcFlowTerminal: Profilé alu sailli_suspendu_engravure-20X20:PROF-SAILLIE -0.5M, Profilé alu sailli_suspendu_engravure-20X20:PROF-SAILLIE -0.5M:3819586
In: Niveau 0
Type - Material: BETCE-DIFFUSEUR-BLANC, <Unnamed>
Pset_DistributionFlowElementCommon - Reference: PROF-SAILLIE -0.5M; sets with these values: 2

# IfcFlowTerminal: Profilé alu sailli_suspendu_engravure-20X20:PROF-SAILLIE -1.5M, Profilé alu sailli_suspendu_engravure-20X20:PROF-SAILLIE -1.5M:3819814
In: Niveau 0
Type - Material: BETCE-DIFFUSEUR-BLANC, <Unnamed>
Pset_DistributionFlowElementCommon - Reference: PROF-SAILLIE -1.5M; sets with these values: 2

# IfcFlowTerminal: Profilé alu sailli_suspendu_engravure-20X20:PROF-SAILLIE -1M, Profilé alu sailli_suspendu_engravure-20X20:PROF-SAILLIE -1M:3819668
In: Niveau 0
Type - Material: BETCE-DIFFUSEUR-BLANC, <Unnamed>
Pset_DistributionFlowElementCommon - Reference: PROF-SAILLIE -1M; sets with these values: 2

# IfcFlowTerminal: Profilé alu sailli_suspendu_engravure-20X20:PROF-SAILLIE -2M, Profilé alu sailli_suspendu_engravure-20X20:PROF-SAILLIE -2M:3819902
In: Niveau 0
Type - Material: BETCE-DIFFUSEUR-BLANC, <Unnamed>
Pset_DistributionFlowElementCommon - Reference: PROF-SAILLIE -2M; sets with these values: 2

# IfcFlowTerminal: Profilé alu sailli_suspendu_engravure-20X20:PROF-SAILLIE -3M, Profilé alu sailli_suspendu_engravure-20X20:PROF-SAILLIE -3M:3819940
In: Niveau 0
Type - Material: BETCE-DIFFUSEUR-BLANC, <Unnamed>
Pset_DistributionFlowElementCommon - Reference: PROF-SAILLIE -3M; sets with these values: 2

# IfcFlowTerminal: Profilé alu sailli_suspendu_engravure-20X20:PROF-SAILLIE -4M, Profilé alu sailli_suspendu_engravure-20X20:PROF-SAILLIE -4M:3820030
In: Niveau 0
Type - Material: BETCE-DIFFUSEUR-BLANC, <Unnamed>
Pset_DistributionFlowElementCommon - Reference: PROF-SAILLIE -4M; sets with these values: 2

# IfcFlowTerminal: Profilé alu sailli_suspendu_engravure-20X20:PROF-SAILLIE -5M, Profilé alu sailli_suspendu_engravure-20X20:PROF-SAILLIE -5M:3820094
In: Niveau 0
Type - Material: BETCE-DIFFUSEUR-BLANC, <Unnamed>
Pset_DistributionFlowElementCommon - Reference: PROF-SAILLIE -5M; sets with these values: 2

# IfcFlowTerminal: Profilé alu sailli_suspendu_engravure-20X20:PROF-SAILLIE DALI -0.5M, Profilé alu sailli_suspendu_engravure-20X20:PROF-SAILLIE DALI -0.5M:3820204
In: Niveau 0
Type - Material: BETCE-DIFFUSEUR-BLANC, <Unnamed>
Pset_DistributionFlowElementCommon - Reference: PROF-SAILLIE DALI -0.5M; sets with these values: 2

# IfcFlowTerminal: Profilé alu sailli_suspendu_engravure-20X20:PROF-SAILLIE DALI -1.5M, Profilé alu sailli_suspendu_engravure-20X20:PROF-SAILLIE DALI -1.5M:3820268
In: Niveau 0
Type - Material: BETCE-DIFFUSEUR-BLANC, <Unnamed>
Pset_DistributionFlowElementCommon - Reference: PROF-SAILLIE DALI -1.5M; sets with these values: 2

# IfcFlowTerminal: Profilé alu sailli_suspendu_engravure-20X20:PROF-SAILLIE DALI -1M, Profilé alu sailli_suspendu_engravure-20X20:PROF-SAILLIE DALI -1M:3820328
In: Niveau 0
Type - Material: BETCE-DIFFUSEUR-BLANC, <Unnamed>
Pset_DistributionFlowElementCommon - Reference: PROF-SAILLIE DALI -1M; sets with these values: 2

# IfcFlowTerminal: Profilé alu sailli_suspendu_engravure-20X20:PROF-SAILLIE DALI -2M, Profilé alu sailli_suspendu_engravure-20X20:PROF-SAILLIE DALI -2M:3820378
In: Niveau 0
Type - Material: BETCE-DIFFUSEUR-BLANC, <Unnamed>
Pset_DistributionFlowElementCommon - Reference: PROF-SAILLIE DALI -2M; sets with these values: 2

# IfcFlowTerminal: Profilé alu sailli_suspendu_engravure-20X20:PROF-SAILLIE DALI -3M, Profilé alu sailli_suspendu_engravure-20X20:PROF-SAILLIE DALI -3M:3820458
In: Niveau 0
Type - Material: BETCE-DIFFUSEUR-BLANC, <Unnamed>
Pset_DistributionFlowElementCommon - Reference: PROF-SAILLIE DALI -3M; sets with these values: 2

# IfcFlowTerminal: Profilé alu sailli_suspendu_engravure-20X20:PROF-SAILLIE DALI -4M, Profilé alu sailli_suspendu_engravure-20X20:PROF-SAILLIE DALI -4M:3820532
In: Niveau 0
Type - Material: BETCE-DIFFUSEUR-BLANC, <Unnamed>
Pset_DistributionFlowElementCommon - Reference: PROF-SAILLIE DALI -4M; sets with these values: 2

# IfcFlowTerminal: Profilé alu sailli_suspendu_engravure-20X20:PROF-SAILLIE DALI -5M, Profilé alu sailli_suspendu_engravure-20X20:PROF-SAILLIE DALI -5M:3820628
In: Niveau 0
Type - Material: BETCE-DIFFUSEUR-BLANC, <Unnamed>
Pset_DistributionFlowElementCommon - Reference: PROF-SAILLIE DALI -5M; sets with these values: 2

# IfcFlowTerminal: Profilé alu sailli_suspendu_engravure-20X20:PROF-SUSPENDU -0.5M, Profilé alu sailli_suspendu_engravure-20X20:PROF-SUSPENDU -0.5M:3820691
In: Niveau 0
Type - Material: BETCE-DIFFUSEUR-BLANC, <Unnamed>
Pset_DistributionFlowElementCommon - Reference: PROF-SUSPENDU -0.5M; sets with these values: 2

# IfcFlowTerminal: Profilé alu sailli_suspendu_engravure-20X20:PROF-SUSPENDU -1.5M, Profilé alu sailli_suspendu_engravure-20X20:PROF-SUSPENDU -1.5M:3820913
In: Niveau 0
Type - Material: BETCE-DIFFUSEUR-BLANC, <Unnamed>
Pset_DistributionFlowElementCommon - Reference: PROF-SUSPENDU -1.5M; sets with these values: 2

# IfcFlowTerminal: Profilé alu sailli_suspendu_engravure-20X20:PROF-SUSPENDU -1M, Profilé alu sailli_suspendu_engravure-20X20:PROF-SUSPENDU -1M:3820987
In: Niveau 0
Type - Material: BETCE-DIFFUSEUR-BLANC, <Unnamed>
Pset_DistributionFlowElementCommon - Reference: PROF-SUSPENDU -1M; sets with these values: 2

# IfcFlowTerminal: Profilé alu sailli_suspendu_engravure-20X20:PROF-SUSPENDU -2M, Profilé alu sailli_suspendu_engravure-20X20:PROF-SUSPENDU -2M:3821031
In: Niveau 0
Type - Material: BETCE-DIFFUSEUR-BLANC, <Unnamed>
Pset_DistributionFlowElementCommon - Reference: PROF-SUSPENDU -2M; sets with these values: 2

# IfcFlowTerminal: Profilé alu sailli_suspendu_engravure-20X20:PROF-SUSPENDU -3M, Profilé alu sailli_suspendu_engravure-20X20:PROF-SUSPENDU -3M:3821117
In: Niveau 0
Type - Material: BETCE-DIFFUSEUR-BLANC, <Unnamed>
Pset_DistributionFlowElementCommon - Reference: PROF-SUSPENDU -3M; sets with these values: 2

# IfcFlowTerminal: Profilé alu sailli_suspendu_engravure-20X20:PROF-SUSPENDU -4M, Profilé alu sailli_suspendu_engravure-20X20:PROF-SUSPENDU -4M:3821167
In: Niveau 0
Type - Material: BETCE-DIFFUSEUR-BLANC, <Unnamed>
Pset_DistributionFlowElementCommon - Reference: PROF-SUSPENDU -4M; sets with these values: 2

# IfcFlowTerminal: Profilé alu sailli_suspendu_engravure-20X20:PROF-SUSPENDU -5M, Profilé alu sailli_suspendu_engravure-20X20:PROF-SUSPENDU -5M:3821225
In: Niveau 0
Type - Material: BETCE-DIFFUSEUR-BLANC, <Unnamed>
Pset_DistributionFlowElementCommon - Reference: PROF-SUSPENDU -5M; sets with these values: 2

# IfcFlowTerminal: Profilé alu sailli_suspendu_engravure-20X20:PROF-SUSPENDU DALI -0.5M, Profilé alu sailli_suspendu_engravure-20X20:PROF-SUSPENDU DALI -0.5M:3821305
In: Niveau 0
Type - Material: BETCE-DIFFUSEUR-BLANC, <Unnamed>
Pset_DistributionFlowElementCommon - Reference: PROF-SUSPENDU DALI -0.5M; sets with these values: 2

# IfcFlowTerminal: Profilé alu sailli_suspendu_engravure-20X20:PROF-SUSPENDU DALI -1.5M, Profilé alu sailli_suspendu_engravure-20X20:PROF-SUSPENDU DALI -1.5M:3821385
In: Niveau 0
Type - Material: BETCE-DIFFUSEUR-BLANC, <Unnamed>
Pset_DistributionFlowElementCommon - Reference: PROF-SUSPENDU DALI -1.5M; sets with these values: 2

# IfcFlowTerminal: Profilé alu sailli_suspendu_engravure-20X20:PROF-SUSPENDU DALI -1M, Profilé alu sailli_suspendu_engravure-20X20:PROF-SUSPENDU DALI -1M:3821455
In: Niveau 0
Type - Material: BETCE-DIFFUSEUR-BLANC, <Unnamed>
Pset_DistributionFlowElementCommon - Reference: PROF-SUSPENDU DALI -1M; sets with these values: 2

# IfcFlowTerminal: Profilé alu sailli_suspendu_engravure-20X20:PROF-SUSPENDU DALI -2M, Profilé alu sailli_suspendu_engravure-20X20:PROF-SUSPENDU DALI -2M:3821519
In: Niveau 0
Type - Material: BETCE-DIFFUSEUR-BLANC, <Unnamed>
Pset_DistributionFlowElementCommon - Reference: PROF-SUSPENDU DALI -2M; sets with these values: 2

# IfcFlowTerminal: Profilé alu sailli_suspendu_engravure-20X20:PROF-SUSPENDU DALI -3M, Profilé alu sailli_suspendu_engravure-20X20:PROF-SUSPENDU DALI -3M:3821597
In: Niveau 0
Type - Material: BETCE-DIFFUSEUR-BLANC, <Unnamed>
Pset_DistributionFlowElementCommon - Reference: PROF-SUSPENDU DALI -3M; sets with these values: 2

# IfcFlowTerminal: Profilé alu sailli_suspendu_engravure-20X20:PROF-SUSPENDU DALI -4M, Profilé alu sailli_suspendu_engravure-20X20:PROF-SUSPENDU DALI -4M:3821673
In: Niveau 0
Type - Material: BETCE-DIFFUSEUR-BLANC, <Unnamed>
Pset_DistributionFlowElementCommon - Reference: PROF-SUSPENDU DALI -4M; sets with these values: 2

# IfcFlowTerminal: Profilé alu sailli_suspendu_engravure-20X20:PROF-SUSPENDU DALI -5M, Profilé alu sailli_suspendu_engravure-20X20:PROF-SUSPENDU DALI -5M:3821861
In: Niveau 0
Type - Material: BETCE-DIFFUSEUR-BLANC, <Unnamed>
Pset_DistributionFlowElementCommon - Reference: PROF-SUSPENDU DALI -5M; sets with these values: 2

# IfcFlowTerminal: Spot encastré_saillie:ENCASTRE - Ø111, Spot encastré_saillie:ENCASTRE - Ø111:3823078
In: Niveau 0
Type - Material: <Unnamed>
Pset_DistributionFlowElementCommon - Reference: ENCASTRE - Ø111; sets with these values: 2

# IfcFlowTerminal: Spot encastré_saillie:ENCASTRE - Ø50, Spot encastré_saillie:ENCASTRE - Ø50:3823082
In: Niveau 0
Type - Material: <Unnamed>
Pset_DistributionFlowElementCommon - Reference: ENCASTRE - Ø50; sets with these values: 2

# IfcFlowTerminal: Spot encastré_saillie:ENCASTRE - Ø76, Spot encastré_saillie:ENCASTRE - Ø76:3823081
In: Niveau 0
Type - Material: <Unnamed>
Pset_DistributionFlowElementCommon - Reference: ENCASTRE - Ø76; sets with these values: 2

# IfcFlowTerminal: Spot encastré_saillie:ENCASTRE - Ø81, Spot encastré_saillie:ENCASTRE - Ø81:3823080
In: Niveau 0
Type - Material: <Unnamed>
Pset_DistributionFlowElementCommon - Reference: ENCASTRE - Ø81; sets with these values: 2

# IfcFlowTerminal: Spot encastré_saillie:ENCASTRE - Ø86, Spot encastré_saillie:ENCASTRE - Ø86:3823079
In: Niveau 0
Type - Material: <Unnamed>
Pset_DistributionFlowElementCommon - Reference: ENCASTRE - Ø86; sets with these values: 2

# IfcFlowTerminal: Spot encastré_saillie:ENCASTRE DALI - Ø111, Spot encastré_saillie:ENCASTRE DALI - Ø111:3823083
In: Niveau 0
Type - Material: <Unnamed>
Pset_DistributionFlowElementCommon - Reference: ENCASTRE DALI - Ø111; sets with these values: 2

# IfcFlowTerminal: Spot encastré_saillie:ENCASTRE DALI - Ø50, Spot encastré_saillie:ENCASTRE DALI - Ø50:3823087
In: Niveau 0
Type - Material: <Unnamed>
Pset_DistributionFlowElementCommon - Reference: ENCASTRE DALI - Ø50; sets with these values: 2

# IfcFlowTerminal: Spot encastré_saillie:ENCASTRE DALI - Ø76, Spot encastré_saillie:ENCASTRE DALI - Ø76:3823086
In: Niveau 0
Type - Material: <Unnamed>
Pset_DistributionFlowElementCommon - Reference: ENCASTRE DALI - Ø76; sets with these values: 2

# IfcFlowTerminal: Spot encastré_saillie:ENCASTRE DALI - Ø81, Spot encastré_saillie:ENCASTRE DALI - Ø81:3823085
In: Niveau 0
Type - Material: <Unnamed>
Pset_DistributionFlowElementCommon - Reference: ENCASTRE DALI - Ø81; sets with these values: 2

# IfcFlowTerminal: Spot encastré_saillie:ENCASTRE DALI - Ø86, Spot encastré_saillie:ENCASTRE DALI - Ø86:3823084
In: Niveau 0
Type - Material: <Unnamed>
Pset_DistributionFlowElementCommon - Reference: ENCASTRE DALI - Ø86; sets with these values: 2

# IfcFlowTerminal: Spot encastré_saillie:ENCASTRE ETANCHE - Ø111, Spot encastré_saillie:ENCASTRE ETANCHE - Ø111:3823088
In: Niveau 0
Type - Material: <Unnamed>
Pset_DistributionFlowElementCommon - Reference: ENCASTRE ETANCHE - Ø111; sets with these values: 2

# IfcFlowTerminal: Spot encastré_saillie:ENCASTRE ETANCHE - Ø50, Spot encastré_saillie:ENCASTRE ETANCHE - Ø50:3823092
In: Niveau 0
Type - Material: <Unnamed>
Pset_DistributionFlowElementCommon - Reference: ENCASTRE ETANCHE - Ø50; sets with these values: 2

# IfcFlowTerminal: Spot encastré_saillie:ENCASTRE ETANCHE - Ø76, Spot encastré_saillie:ENCASTRE ETANCHE - Ø76:3823091
In: Niveau 0
Type - Material: <Unnamed>
Pset_DistributionFlowElementCommon - Reference: ENCASTRE ETANCHE - Ø76; sets with these values: 2

# IfcFlowTerminal: Spot encastré_saillie:ENCASTRE ETANCHE - Ø81, Spot encastré_saillie:ENCASTRE ETANCHE - Ø81:3823090
In: Niveau 0
Type - Material: <Unnamed>
Pset_DistributionFlowElementCommon - Reference: ENCASTRE ETANCHE - Ø81; sets with these values: 2

# IfcFlowTerminal: Spot encastré_saillie:ENCASTRE ETANCHE - Ø86, Spot encastré_saillie:ENCASTRE ETANCHE - Ø86:3823089
In: Niveau 0
Type - Material: <Unnamed>
Pset_DistributionFlowElementCommon - Reference: ENCASTRE ETANCHE - Ø86; sets with these values: 2

# IfcFlowTerminal: Spot encastré_saillie:SAILLIE - Ø111, Spot encastré_saillie:SAILLIE - Ø111:3856385
In: Niveau 0
Type - Material: <Unnamed>
Pset_DistributionFlowElementCommon - Reference: SAILLIE - Ø111; sets with these values: 2

# IfcFlowTerminal: Spot encastré_saillie:SAILLIE - Ø50, Spot encastré_saillie:SAILLIE - Ø50:3856155
In: Niveau 0
Type - Material: <Unnamed>
Pset_DistributionFlowElementCommon - Reference: SAILLIE - Ø50; sets with these values: 2

# IfcFlowTerminal: Spot encastré_saillie:SAILLIE - Ø76, Spot encastré_saillie:SAILLIE - Ø76:3856253
In: Niveau 0
Type - Material: <Unnamed>
Pset_DistributionFlowElementCommon - Reference: SAILLIE - Ø76; sets with these values: 2

# IfcFlowTerminal: Spot encastré_saillie:SAILLIE - Ø81, Spot encastré_saillie:SAILLIE - Ø81:3856299
In: Niveau 0
Type - Material: <Unnamed>
Pset_DistributionFlowElementCommon - Reference: SAILLIE - Ø81; sets with these values: 2

# IfcFlowTerminal: Spot encastré_saillie:SAILLIE - Ø86, Spot encastré_saillie:SAILLIE - Ø86:3856345
In: Niveau 0
Type - Material: <Unnamed>
Pset_DistributionFlowElementCommon - Reference: SAILLIE - Ø86; sets with these values: 2

# IfcFlowTerminal: Spot encastré_saillie:SAILLIE DALI - Ø111, Spot encastré_saillie:SAILLIE DALI - Ø111:3856649
In: Niveau 0
Type - Material: <Unnamed>
Pset_DistributionFlowElementCommon - Reference: SAILLIE DALI - Ø111; sets with these values: 2

# IfcFlowTerminal: Spot encastré_saillie:SAILLIE DALI - Ø50, Spot encastré_saillie:SAILLIE DALI - Ø50:3856425
In: Niveau 0
Type - Material: <Unnamed>
Pset_DistributionFlowElementCommon - Reference: SAILLIE DALI - Ø50; sets with these values: 2

# IfcFlowTerminal: Spot encastré_saillie:SAILLIE DALI - Ø76, Spot encastré_saillie:SAILLIE DALI - Ø76:3856467
In: Niveau 0
Type - Material: <Unnamed>
Pset_DistributionFlowElementCommon - Reference: SAILLIE DALI - Ø76; sets with these values: 2

# IfcFlowTerminal: Spot encastré_saillie:SAILLIE DALI - Ø81, Spot encastré_saillie:SAILLIE DALI - Ø81:3856521
In: Niveau 0
Type - Material: <Unnamed>
Pset_DistributionFlowElementCommon - Reference: SAILLIE DALI - Ø81; sets with these values: 2

# IfcFlowTerminal: Spot encastré_saillie:SAILLIE DALI - Ø86, Spot encastré_saillie:SAILLIE DALI - Ø86:3856587
In: Niveau 0
Type - Material: <Unnamed>
Pset_DistributionFlowElementCommon - Reference: SAILLIE DALI - Ø86; sets with these values: 2

# IfcFlowTerminal: Structure encastré_saillie_suspendu_engravure-45X 80:ENCASTRE-655mmX85mm (4)
In: Niveau 0
Type - Material: BETCE-ENVELOPPE-NOIR, BETCE-DIFFUSEUR-BLANC
Pset_DistributionFlowElementCommon - Reference: ENCASTRE-655mmX85mm; sets with these values: 2
Name (Structure encastré_saillie_suspendu_engravure-45X 80:ENCASTRE-655mmX85mm:...)
6171611
6171782
6171798
6171818

# IfcOpeningElement: Opening (6)
In: Niveau 0
Pset_OpeningElementCommon - Reference: Générique - 200 mm; sets with these values: 2
Name (Mur de base:Générique - 200 mm:...)
3743049:1
3743049:2
3743049:3
3744158:1
3744158:2
3744158:3

# IfcWallStandardCase: Mur de base:Générique - 200 mm (41)
In: Niveau 0
Type - PredefinedType: STANDARD; Material: Mur par défaut 0.2 m
Pset_QuantityTakeOff - Reference: Générique - 200 mm; sets with these values: 2
Pset_WallCommon - Reference: Générique - 200 mm; IsExternal: yes; ExtendToStructure: no; LoadBearing: no
Name (Mur de base:Générique - 200 mm:...)
3329403
3329404
3329405
3330858
3330859
3330860
3330861
3330862
3330873
3494351
3494352
3494353
3494354
3742945
3742946
3742948
3742980
3742988
3742996
3743049
3743057
3744151
3744152
3744154
3744155
3744156
3744157
3744158
3744159
3745673
3745674
3745757
3745758
3745759
3745760
3909040
3911534
3927510
3927512
4090543
5307218

# IfcZone, Par défaut:293242
Pset_ZoneCommon - Reference: Par défaut
